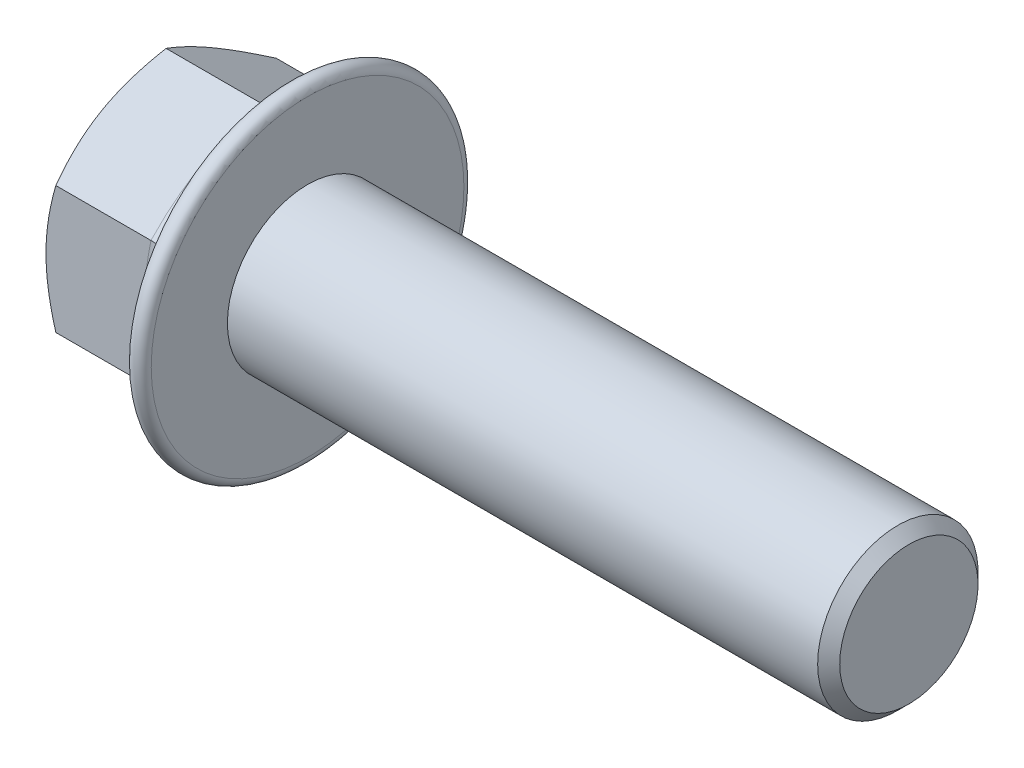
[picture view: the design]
ISO-10303-21;
HEADER;
FILE_DESCRIPTION(('STEP AP214'),'2;1');
FILE_NAME('part.step','',(''),(''),'','','');
FILE_SCHEMA(('AUTOMOTIVE_DESIGN { 1 0 10303 214 1 1 1 1 }'));
ENDSEC;
DATA;
#1=APPLICATION_CONTEXT('core data for automotive mechanical design processes');
#2=APPLICATION_PROTOCOL_DEFINITION('international standard','automotive_design',2000,#1);
#3=PRODUCT_CONTEXT('',#1,'mechanical');
#4=PRODUCT('Part','Part','',(#3));
#5=PRODUCT_RELATED_PRODUCT_CATEGORY('part','',(#4));
#6=PRODUCT_DEFINITION_FORMATION('','',#4);
#7=PRODUCT_DEFINITION_CONTEXT('part definition',#1,'design');
#8=PRODUCT_DEFINITION('design','',#6,#7);
#9=PRODUCT_DEFINITION_SHAPE('','',#8);
#10=(LENGTH_UNIT() NAMED_UNIT(*) SI_UNIT(.MILLI.,.METRE.));
#11=(NAMED_UNIT(*) PLANE_ANGLE_UNIT() SI_UNIT($,.RADIAN.));
#12=(NAMED_UNIT(*) SI_UNIT($,.STERADIAN.) SOLID_ANGLE_UNIT());
#13=UNCERTAINTY_MEASURE_WITH_UNIT(LENGTH_MEASURE(1.E-05),#10,'distance_accuracy_value','');
#14=(GEOMETRIC_REPRESENTATION_CONTEXT(3) GLOBAL_UNCERTAINTY_ASSIGNED_CONTEXT((#13)) GLOBAL_UNIT_ASSIGNED_CONTEXT((#10,
#11,#12)) REPRESENTATION_CONTEXT('',''));
#15=CARTESIAN_POINT('',(0.,0.,0.));
#16=DIRECTION('',(0.,0.,1.));
#17=DIRECTION('',(1.,0.,0.));
#18=AXIS2_PLACEMENT_3D('',#15,#16,#17);
#19=CARTESIAN_POINT('',(15.1,12.7017059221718,0.));
#20=DIRECTION('',(1.,0.,0.));
#21=DIRECTION('',(0.,0.,-1.));
#22=AXIS2_PLACEMENT_3D('',#19,#20,#21);
#23=PLANE('',#22);
#24=CARTESIAN_POINT('',(15.1,0.,0.));
#25=DIRECTION('',(1.,0.,0.));
#26=DIRECTION('',(0.,0.,-1.));
#27=AXIS2_PLACEMENT_3D('',#24,#25,#26);
#28=CIRCLE('',#27,8.);
#29=CARTESIAN_POINT('',(15.1,0.,-8.));
#30=VERTEX_POINT('',#29);
#31=EDGE_CURVE('E510',#30,#30,#28,.F.);
#32=ORIENTED_EDGE('',*,*,#31,.T.);
#33=EDGE_LOOP('',(#32));
#34=FACE_BOUND('',#33,.T.);
#35=CARTESIAN_POINT('',(15.1,0.,0.));
#36=DIRECTION('',(-1.,0.,0.));
#37=DIRECTION('',(0.,0.,1.));
#38=AXIS2_PLACEMENT_3D('',#35,#36,#37);
#39=CIRCLE('',#38,15.6);
#40=CARTESIAN_POINT('',(15.1,0.,15.6));
#41=VERTEX_POINT('',#40);
#42=EDGE_CURVE('E472',#41,#41,#39,.T.);
#43=ORIENTED_EDGE('',*,*,#42,.F.);
#44=EDGE_LOOP('',(#43));
#45=FACE_BOUND('',#44,.T.);
#46=ADVANCED_FACE('F43',(#34,#45),#23,.T.);
#47=CARTESIAN_POINT('',(0.,0.,0.));
#48=DIRECTION('',(-1.,0.,0.));
#49=DIRECTION('',(0.,0.,1.));
#50=AXIS2_PLACEMENT_3D('',#47,#48,#49);
#51=CYLINDRICAL_SURFACE('',#50,8.);
#52=ORIENTED_EDGE('',*,*,#31,.F.);
#53=EDGE_LOOP('',(#52));
#54=FACE_BOUND('',#53,.T.);
#55=CARTESIAN_POINT('',(73.9985,0.,0.));
#56=DIRECTION('',(-1.,0.,0.));
#57=DIRECTION('',(0.,0.,1.));
#58=AXIS2_PLACEMENT_3D('',#55,#56,#57);
#59=CIRCLE('',#58,8.);
#60=CARTESIAN_POINT('',(73.9985,0.,8.));
#61=VERTEX_POINT('',#60);
#62=EDGE_CURVE('E514',#61,#61,#59,.T.);
#63=ORIENTED_EDGE('',*,*,#62,.T.);
#64=EDGE_LOOP('',(#63));
#65=FACE_BOUND('',#64,.T.);
#66=ADVANCED_FACE('F614',(#54,#65),#51,.T.);
#67=CARTESIAN_POINT('',(75.1,0.,0.));
#68=DIRECTION('',(-1.,0.,0.));
#69=DIRECTION('',(0.,0.,1.));
#70=AXIS2_PLACEMENT_3D('',#67,#68,#69);
#71=CONICAL_SURFACE('',#70,6.8985,0.78539816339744);
#72=ORIENTED_EDGE('',*,*,#62,.F.);
#73=EDGE_LOOP('',(#72));
#74=FACE_BOUND('',#73,.T.);
#75=CARTESIAN_POINT('',(75.1,0.,0.));
#76=DIRECTION('',(-1.,0.,0.));
#77=DIRECTION('',(0.,0.,1.));
#78=AXIS2_PLACEMENT_3D('',#75,#76,#77);
#79=CIRCLE('',#78,6.8985);
#80=CARTESIAN_POINT('',(75.1,0.,6.8985));
#81=VERTEX_POINT('',#80);
#82=EDGE_CURVE('E600',#81,#81,#79,.T.);
#83=ORIENTED_EDGE('',*,*,#82,.T.);
#84=EDGE_LOOP('',(#83));
#85=FACE_BOUND('',#84,.T.);
#86=ADVANCED_FACE('F623',(#74,#85),#71,.T.);
#87=CARTESIAN_POINT('',(75.1,0.,0.));
#88=DIRECTION('',(-1.,0.,0.));
#89=DIRECTION('',(0.,0.,1.));
#90=AXIS2_PLACEMENT_3D('',#87,#88,#89);
#91=PLANE('',#90);
#92=ORIENTED_EDGE('',*,*,#82,.F.);
#93=EDGE_LOOP('',(#92));
#94=FACE_BOUND('',#93,.T.);
#95=ADVANCED_FACE('F231',(#94),#91,.F.);
#96=CARTESIAN_POINT('',(13.384322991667,0.,0.));
#97=DIRECTION('',(1.,0.,0.));
#98=DIRECTION('',(0.,0.,-1.));
#99=AXIS2_PLACEMENT_3D('',#96,#97,#98);
#100=CONICAL_SURFACE('',#99,15.9803564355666,1.13446401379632);
#101=CARTESIAN_POINT('',(11.5596455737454,10.6409962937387,-11.));
#102=CARTESIAN_POINT('',(12.9255632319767,10.2375579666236,-11.));
#103=CARTESIAN_POINT('',(13.3722611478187,10.105620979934,-12.345937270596));
#104=CARTESIAN_POINT('',(11.4305304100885,10.2037041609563,-11.));
#105=CARTESIAN_POINT('',(12.7912029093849,9.81274196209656,-11.));
#106=CARTESIAN_POINT('',(13.2431459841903,9.68149724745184,-12.3351734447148));
#107=CARTESIAN_POINT('',(11.3057081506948,9.76509659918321,-11.));
#108=CARTESIAN_POINT('',(12.660771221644,9.3863333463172,-11.));
#109=CARTESIAN_POINT('',(13.1183237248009,9.25708569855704,-12.3242034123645));
#110=CARTESIAN_POINT('',(11.0664512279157,8.88489794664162,-11.));
#111=CARTESIAN_POINT('',(12.4104363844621,8.53196876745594,-11.));
#112=CARTESIAN_POINT('',(12.8790668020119,8.40759481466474,-12.3021680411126));
#113=CARTESIAN_POINT('',(10.9520202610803,8.44330585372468,-11.));
#114=CARTESIAN_POINT('',(12.2904947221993,8.10402124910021,-11.));
#115=CARTESIAN_POINT('',(12.7646358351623,7.98251529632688,-12.2911026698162));
#116=CARTESIAN_POINT('',(10.7349947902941,7.55526586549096,-11.));
#117=CARTESIAN_POINT('',(12.0627180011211,7.24484434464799,-11.));
#118=CARTESIAN_POINT('',(12.5476103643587,7.13014121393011,-12.2691566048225));
#119=CARTESIAN_POINT('',(10.6324510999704,7.10880545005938,-11.));
#120=CARTESIAN_POINT('',(11.9548696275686,6.81356056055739,-11.));
#121=CARTESIAN_POINT('',(12.4450666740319,6.70284474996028,-12.258276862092));
#122=CARTESIAN_POINT('',(10.4419306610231,6.21280862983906,-11.));
#123=CARTESIAN_POINT('',(11.7542777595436,5.9495408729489,-11.));
#124=CARTESIAN_POINT('',(12.2545462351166,5.8479153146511,-12.2372354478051));
#125=CARTESIAN_POINT('',(10.3539525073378,5.76327252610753,-11.));
#126=CARTESIAN_POINT('',(11.6614471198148,5.51668928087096,-11.));
#127=CARTESIAN_POINT('',(12.1665680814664,5.42028237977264,-12.2270737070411));
#128=CARTESIAN_POINT('',(10.1969867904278,4.87337908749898,-11.));
#129=CARTESIAN_POINT('',(11.4956925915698,4.66129336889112,-11.));
#130=CARTESIAN_POINT('',(12.0096023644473,4.57628560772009,-12.2083200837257));
#131=CARTESIAN_POINT('',(10.1275507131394,4.43310153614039,-11.));
#132=CARTESIAN_POINT('',(11.4222119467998,4.23863121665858,-11.));
#133=CARTESIAN_POINT('',(11.9401662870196,4.15992916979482,-12.1996932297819));
#134=CARTESIAN_POINT('',(10.0066902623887,3.55005293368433,-11.));
#135=CARTESIAN_POINT('',(11.2942720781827,3.39227440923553,-11.));
#136=CARTESIAN_POINT('',(11.8193058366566,3.3270376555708,-12.1842941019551));
#137=CARTESIAN_POINT('',(9.95526596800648,3.10728187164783,-11.));
#138=CARTESIAN_POINT('',(11.2397180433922,2.96829897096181,-11.));
#139=CARTESIAN_POINT('',(11.7678815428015,2.91050257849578,-12.1775218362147));
#140=CARTESIAN_POINT('',(9.8722924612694,2.22075700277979,-11.));
#141=CARTESIAN_POINT('',(11.1517130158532,2.12056938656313,-11.));
#142=CARTESIAN_POINT('',(11.6849080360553,2.07816925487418,-12.1664198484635));
#143=CARTESIAN_POINT('',(9.84070353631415,1.77700695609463,-11.));
#144=CARTESIAN_POINT('',(11.1181411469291,1.69645468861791,-11.));
#145=CARTESIAN_POINT('',(11.6533191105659,1.66237120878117,-12.1620852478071));
#146=CARTESIAN_POINT('',(9.79845162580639,0.88850703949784,-11.));
#147=CARTESIAN_POINT('',(11.0732713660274,0.84811919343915,-11.));
#148=CARTESIAN_POINT('',(11.6110671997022,0.830739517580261,-12.1562559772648));
#149=CARTESIAN_POINT('',(9.7877882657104,0.443757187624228,-11.));
#150=CARTESIAN_POINT('',(11.0619277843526,0.423474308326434,-11.));
#151=CARTESIAN_POINT('',(11.6004038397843,0.414905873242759,-12.1547612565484));
#152=CARTESIAN_POINT('',(9.78782004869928,-0.446623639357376,-11.));
#153=CARTESIAN_POINT('',(11.0619615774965,-0.426210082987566,-11.));
#154=CARTESIAN_POINT('',(11.6004356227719,-0.417585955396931,-12.1547657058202));
#155=CARTESIAN_POINT('',(9.79855757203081,-0.892254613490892,-11.));
#156=CARTESIAN_POINT('',(11.0733840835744,-0.851697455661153,-11.));
#157=CARTESIAN_POINT('',(11.6111731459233,-0.834244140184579,-12.1562708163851));
#158=CARTESIAN_POINT('',(9.84103825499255,-1.7825096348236,-11.));
#159=CARTESIAN_POINT('',(11.118496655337,-1.70171175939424,-11.));
#160=CARTESIAN_POINT('',(11.6536538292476,-1.6675247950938,-12.1621312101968));
#161=CARTESIAN_POINT('',(9.87278180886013,-2.22713366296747,-11.));
#162=CARTESIAN_POINT('',(11.1522328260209,-2.12666516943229,-11.));
#163=CARTESIAN_POINT('',(11.6853973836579,-2.0841472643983,-12.1664865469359));
#164=CARTESIAN_POINT('',(9.95613528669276,-3.115400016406,-11.));
#165=CARTESIAN_POINT('',(11.2406400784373,-2.97606905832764,-11.));
#166=CARTESIAN_POINT('',(11.7687508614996,-2.91813348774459,-12.1776369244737));
#167=CARTESIAN_POINT('',(10.0077852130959,-3.55903854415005,-11.));
#168=CARTESIAN_POINT('',(11.2954329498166,-3.40088181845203,-11.));
#169=CARTESIAN_POINT('',(11.820400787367,-3.33549703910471,-12.1844368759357));
#170=CARTESIAN_POINT('',(10.129154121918,-4.44380840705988,-11.));
#171=CARTESIAN_POINT('',(11.4239089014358,-4.24890494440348,-11.));
#172=CARTESIAN_POINT('',(11.941769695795,-4.17004410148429,-12.1998942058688));
#173=CARTESIAN_POINT('',(10.1988730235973,-4.88493975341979,-11.));
#174=CARTESIAN_POINT('',(11.4976874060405,-4.67239710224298,-11.));
#175=CARTESIAN_POINT('',(12.0114885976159,-4.58722761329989,-12.2085515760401));
#176=CARTESIAN_POINT('',(10.3564610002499,-5.77657736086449,-11.));
#177=CARTESIAN_POINT('',(11.6640948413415,-5.52949439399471,-11.));
#178=CARTESIAN_POINT('',(12.1690765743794,-5.43292471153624,-12.2273669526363));
#179=CARTESIAN_POINT('',(10.444780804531,-6.22700328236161,-11.));
#180=CARTESIAN_POINT('',(11.7572832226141,-5.96321710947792,-11.));
#181=CARTESIAN_POINT('',(12.2573963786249,-5.86143082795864,-12.237559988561));
#182=CARTESIAN_POINT('',(10.6360189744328,-7.1247669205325,-11.));
#183=CARTESIAN_POINT('',(11.9586238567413,-6.82897274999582,-11.));
#184=CARTESIAN_POINT('',(12.4486345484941,-6.71810419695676,-12.2586607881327));
#185=CARTESIAN_POINT('',(10.7389387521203,-7.5721043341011,-11.));
#186=CARTESIAN_POINT('',(12.0668635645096,-7.26112112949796,-11.));
#187=CARTESIAN_POINT('',(12.5515543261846,-7.14627141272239,-12.2695686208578));
#188=CARTESIAN_POINT('',(10.9567359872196,-8.46187507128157,-11.));
#189=CARTESIAN_POINT('',(12.2954406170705,-8.12201010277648,-11.));
#190=CARTESIAN_POINT('',(12.7693515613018,-8.00037188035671,-12.2915659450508));
#191=CARTESIAN_POINT('',(11.0715622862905,-8.904321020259,-11.));
#192=CARTESIAN_POINT('',(12.4157910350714,-8.55080460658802,-11.));
#193=CARTESIAN_POINT('',(12.8841778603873,-8.42630705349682,-12.3026544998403));
#194=CARTESIAN_POINT('',(11.3116248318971,-9.78621842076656,-11.));
#195=CARTESIAN_POINT('',(12.6669566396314,-9.40685918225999,-11.));
#196=CARTESIAN_POINT('',(13.1242404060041,-9.27750557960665,-12.3247314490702));
#197=CARTESIAN_POINT('',(11.4368573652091,-10.225670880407,-11.));
#198=CARTESIAN_POINT('',(12.7978102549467,-9.83411006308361,-11.));
#199=CARTESIAN_POINT('',(13.2494729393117,-9.70276911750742,-12.3357198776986));
#200=CARTESIAN_POINT('',(11.5663866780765,-10.6638049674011,-11.));
#201=CARTESIAN_POINT('',(12.9325938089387,-10.2597638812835,-11.));
#202=CARTESIAN_POINT('',(13.3790022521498,-10.1277433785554,-12.346499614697));
#203=(BOUNDED_SURFACE() B_SPLINE_SURFACE(3,2,((#101,#102,#103),(#104,#105,#106),(#107,#108,
#109),(#110,#111,#112),(#113,#114,#115),(#116,#117,#118),(#119,#120,#121),(#122,#123,#124),
(#125,#126,#127),(#128,#129,#130),(#131,#132,#133),(#134,#135,#136),(#137,#138,#139),(#140,#141,
#142),(#143,#144,#145),(#146,#147,#148),(#149,#150,#151),(#152,#153,#154),(#155,#156,#157),
(#158,#159,#160),(#161,#162,#163),(#164,#165,#166),(#167,#168,#169),(#170,#171,#172),(#173,#174,
#175),(#176,#177,#178),(#179,#180,#181),(#182,#183,#184),(#185,#186,#187),(#188,#189,#190),
(#191,#192,#193),(#194,#195,#196),(#197,#198,#199),(#200,#201,#202)),.UNSPECIFIED.,.F.,.F.,
.F.) B_SPLINE_SURFACE_WITH_KNOTS((4,2,2,2,2,2,2,2,2,2,2,2,2,2,2,2,4),(3,3),(0.,1.36791223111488,
2.73630918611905,4.11035517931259,5.48426854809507,6.82109549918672,8.15792831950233,
9.49207604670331,10.8261998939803,12.1629683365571,13.4997618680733,14.8392558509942,
16.1787438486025,17.5554729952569,18.932335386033,20.3035094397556,21.6741963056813),(0.,1.),
.UNSPECIFIED.) GEOMETRIC_REPRESENTATION_ITEM() RATIONAL_B_SPLINE_SURFACE(((1.,0.814564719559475,
1.),(1.,0.816216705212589,1.),(1.,0.817894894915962,1.),(1.,0.82125557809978,1.),(1.,
0.822938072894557,1.),(1.,0.826264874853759,1.),(1.,0.827908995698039,1.),(1.,0.831079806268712,
1.),(1.,0.832606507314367,1.),(1.,0.835417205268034,1.),(1.,0.836706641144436,1.),(1.,
0.839004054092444,1.),(1.,0.840012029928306,1.),(1.,0.841662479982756,1.),(1.,0.842305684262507,
1.),(1.,0.84317032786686,1.),(1.,0.843391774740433,1.),(1.,0.843391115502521,1.),(1.,
0.843168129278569,1.),(1.,0.842298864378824,1.),(1.,0.841652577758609,1.),(1.,0.839994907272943,
1.),(1.,0.838982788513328,1.),(1.,0.836676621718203,1.),(1.,0.835382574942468,1.),(1.,
0.83256248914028,1.),(1.,0.831031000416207,1.),(1.,0.827851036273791,1.),(1.,0.826202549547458,
1.),(1.,0.82286770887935,1.),(1.,0.821181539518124,1.),(1.,0.817814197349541,1.),(1.,
0.816133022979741,1.),(1.,0.814478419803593,1.))) REPRESENTATION_ITEM('') SURFACE());
#204=CARTESIAN_POINT('',(13.3790022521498,-10.1277433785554,-12.346499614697));
#205=CARTESIAN_POINT('',(13.2494729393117,-9.70276911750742,-12.3357198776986));
#206=CARTESIAN_POINT('',(13.1242404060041,-9.27750557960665,-12.3247314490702));
#207=CARTESIAN_POINT('',(12.8841778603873,-8.42630705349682,-12.3026544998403));
#208=CARTESIAN_POINT('',(12.7693515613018,-8.00037188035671,-12.2915659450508));
#209=CARTESIAN_POINT('',(12.5515543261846,-7.14627141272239,-12.2695686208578));
#210=CARTESIAN_POINT('',(12.4486345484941,-6.71810419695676,-12.2586607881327));
#211=CARTESIAN_POINT('',(12.2573963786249,-5.86143082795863,-12.237559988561));
#212=CARTESIAN_POINT('',(12.1690765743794,-5.43292471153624,-12.2273669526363));
#213=CARTESIAN_POINT('',(12.0114885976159,-4.58722761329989,-12.2085515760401));
#214=CARTESIAN_POINT('',(11.941769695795,-4.17004410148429,-12.1998942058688));
#215=CARTESIAN_POINT('',(11.820400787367,-3.33549703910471,-12.1844368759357));
#216=CARTESIAN_POINT('',(11.7687508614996,-2.91813348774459,-12.1776369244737));
#217=CARTESIAN_POINT('',(11.6853973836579,-2.0841472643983,-12.1664865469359));
#218=CARTESIAN_POINT('',(11.6536538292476,-1.6675247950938,-12.1621312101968));
#219=CARTESIAN_POINT('',(11.6111731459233,-0.834244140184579,-12.1562708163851));
#220=CARTESIAN_POINT('',(11.6004356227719,-0.417585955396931,-12.1547657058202));
#221=CARTESIAN_POINT('',(11.6004038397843,0.414905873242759,-12.1547612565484));
#222=CARTESIAN_POINT('',(11.6110671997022,0.830739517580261,-12.1562559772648));
#223=CARTESIAN_POINT('',(11.6533191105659,1.66237120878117,-12.1620852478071));
#224=CARTESIAN_POINT('',(11.6849080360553,2.07816925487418,-12.1664198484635));
#225=CARTESIAN_POINT('',(11.7678815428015,2.91050257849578,-12.1775218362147));
#226=CARTESIAN_POINT('',(11.8193058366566,3.3270376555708,-12.1842941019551));
#227=CARTESIAN_POINT('',(11.9401662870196,4.15992916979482,-12.1996932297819));
#228=CARTESIAN_POINT('',(12.0096023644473,4.57628560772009,-12.2083200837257));
#229=CARTESIAN_POINT('',(12.1665680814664,5.42028237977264,-12.2270737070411));
#230=CARTESIAN_POINT('',(12.2545462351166,5.8479153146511,-12.2372354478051));
#231=CARTESIAN_POINT('',(12.4450666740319,6.70284474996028,-12.258276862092));
#232=CARTESIAN_POINT('',(12.5476103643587,7.13014121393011,-12.2691566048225));
#233=CARTESIAN_POINT('',(12.7646358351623,7.98251529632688,-12.2911026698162));
#234=CARTESIAN_POINT('',(12.8790668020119,8.40759481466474,-12.3021680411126));
#235=CARTESIAN_POINT('',(13.1183237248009,9.25708569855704,-12.3242034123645));
#236=CARTESIAN_POINT('',(13.2431459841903,9.68149724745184,-12.3351734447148));
#237=CARTESIAN_POINT('',(13.3722611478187,10.105620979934,-12.345937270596));
#238=B_SPLINE_CURVE_WITH_KNOTS('',3,(#204,#205,#206,#207,#208,#209,#210,#211,#212,#213,#214,
#215,#216,#217,#218,#219,#220,#221,#222,#223,#224,#225,#226,#227,#228,#229,#230,#231,#232,#233,
#234,#235,#236,#237),.UNSPECIFIED.,.F.,.F.,(4,2,2,2,2,2,2,2,2,2,2,2,2,2,2,2,4),(0.,
1.37068686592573,2.7418609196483,4.11872331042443,5.49545245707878,6.83494045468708,
8.17443443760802,9.51122796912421,10.847996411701,12.182120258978,13.516267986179,
14.8531008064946,16.1899277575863,17.5638411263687,18.9378871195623,20.3062840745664,
21.6741963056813),.UNSPECIFIED.);
#239=CARTESIAN_POINT('',(12.5382142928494,-7.08293523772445,-12.2680036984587));
#240=VERTEX_POINT('',#239);
#241=CARTESIAN_POINT('',(12.5382142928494,7.08293523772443,-12.2680036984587));
#242=VERTEX_POINT('',#241);
#243=EDGE_CURVE('E559',#240,#242,#238,.T.);
#244=ORIENTED_EDGE('',*,*,#243,.T.);
#245=CARTESIAN_POINT('',(11.5735039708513,14.8702068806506,3.75595383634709));
#246=CARTESIAN_POINT('',(12.9400163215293,14.6678691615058,3.40549462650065));
#247=CARTESIAN_POINT('',(13.3861195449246,15.7684313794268,2.61753972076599));
#248=CARTESIAN_POINT('',(11.443142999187,14.6500285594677,3.3745937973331));
#249=CARTESIAN_POINT('',(12.8043767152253,14.4539536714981,3.0349821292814));
#250=CARTESIAN_POINT('',(13.2557585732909,15.5454701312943,2.25301763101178));
#251=CARTESIAN_POINT('',(11.3171084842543,14.4291853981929,2.99208222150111));
#252=CARTESIAN_POINT('',(12.6726913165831,14.2392320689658,2.66307340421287));
#253=CARTESIAN_POINT('',(13.1297240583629,15.3221782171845,1.88834853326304));
#254=CARTESIAN_POINT('',(11.0755263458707,13.9859880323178,2.22444186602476));
#255=CARTESIAN_POINT('',(12.4199461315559,13.809004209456,1.91789689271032));
#256=CARTESIAN_POINT('',(12.8881419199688,14.8751633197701,1.1584734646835));
#257=CARTESIAN_POINT('',(10.9599825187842,13.7636333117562,1.83931219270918));
#258=CARTESIAN_POINT('',(12.2988476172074,13.5935029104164,1.5446376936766));
#259=CARTESIAN_POINT('',(12.7725980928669,14.651440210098,0.793267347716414));
#260=CARTESIAN_POINT('',(10.7408534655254,13.3164534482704,1.0647739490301));
#261=CARTESIAN_POINT('',(12.0688786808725,13.1608272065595,0.795221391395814));
#262=CARTESIAN_POINT('',(12.5534690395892,14.2030151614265,0.0608038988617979));
#263=CARTESIAN_POINT('',(10.6373204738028,13.091621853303,0.675354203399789));
#264=CARTESIAN_POINT('',(11.9599954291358,12.9436256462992,0.419017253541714));
#265=CARTESIAN_POINT('',(12.4499360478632,13.9783130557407,-0.306455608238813));
#266=CARTESIAN_POINT('',(10.445003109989,12.6403980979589,-0.106188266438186));
#267=CARTESIAN_POINT('',(11.7575202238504,12.5084855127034,-0.334667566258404));
#268=CARTESIAN_POINT('',(12.2576186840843,13.5293618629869,-1.04163160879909));
#269=CARTESIAN_POINT('',(10.3562172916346,12.4140060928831,-0.498310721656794));
#270=CARTESIAN_POINT('',(11.6638394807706,12.2904884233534,-0.712249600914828));
#271=CARTESIAN_POINT('',(12.1688328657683,13.3051127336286,-1.40954803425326));
#272=CARTESIAN_POINT('',(10.1979057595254,11.9658880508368,-1.27447393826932));
#273=CARTESIAN_POINT('',(11.4966667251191,11.8597328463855,-1.45834014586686));
#274=CARTESIAN_POINT('',(12.01052133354,12.8637174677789,-2.13625642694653));
#275=CARTESIAN_POINT('',(10.1279213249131,11.7442028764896,-1.65844392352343));
#276=CARTESIAN_POINT('',(11.4226055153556,11.6469146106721,-1.82695214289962));
#277=CARTESIAN_POINT('',(11.9405368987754,12.6465442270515,-2.49502397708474));
#278=CARTESIAN_POINT('',(10.0062196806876,11.299568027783,-2.42857407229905));
#279=CARTESIAN_POINT('',(11.2937751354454,11.2207552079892,-2.56508188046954));
#280=CARTESIAN_POINT('',(11.8188352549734,12.2137361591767,-3.21365649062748));
#281=CARTESIAN_POINT('',(9.95450254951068,11.0766183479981,-2.81473424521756));
#282=CARTESIAN_POINT('',(11.2389091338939,11.0072706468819,-2.93484798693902));
#283=CARTESIAN_POINT('',(11.7671181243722,11.9981013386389,-3.57352145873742));
#284=CARTESIAN_POINT('',(9.87123699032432,10.6302279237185,-3.58790514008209));
#285=CARTESIAN_POINT('',(11.1505933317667,10.580420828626,-3.67417355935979));
#286=CARTESIAN_POINT('',(11.6838525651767,11.5693586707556,-4.29383691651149));
#287=CARTESIAN_POINT('',(9.83964756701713,10.4067891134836,-3.97491251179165));
#288=CARTESIAN_POINT('',(11.1170198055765,10.3668711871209,-4.04405238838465));
#289=CARTESIAN_POINT('',(11.652263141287,11.3562465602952,-4.65428470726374));
#290=CARTESIAN_POINT('',(9.79770239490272,9.95941155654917,-4.7497931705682));
#291=CARTESIAN_POINT('',(11.0724752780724,9.93972359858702,-4.78389371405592));
#292=CARTESIAN_POINT('',(11.6103179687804,10.9325028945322,-5.37665300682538));
#293=CARTESIAN_POINT('',(9.78734623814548,9.73547281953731,-5.13766644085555));
#294=CARTESIAN_POINT('',(11.0614582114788,9.72590877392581,-5.15423185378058));
#295=CARTESIAN_POINT('',(11.5999618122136,10.7218712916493,-5.73857348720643));
#296=CARTESIAN_POINT('',(9.78829157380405,9.28836706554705,-5.91207632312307));
#297=CARTESIAN_POINT('',(11.0624625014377,9.29923871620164,-5.89324607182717));
#298=CARTESIAN_POINT('',(11.6009071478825,10.3039484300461,-6.46270063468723));
#299=CARTESIAN_POINT('',(9.79951969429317,9.06520000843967,-6.29861300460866));
#300=CARTESIAN_POINT('',(11.0744068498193,9.08615659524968,-6.26231513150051));
#301=CARTESIAN_POINT('',(11.6121352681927,10.0966482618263,-6.82490216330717));
#302=CARTESIAN_POINT('',(9.84302911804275,8.61938207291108,-7.07079231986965));
#303=CARTESIAN_POINT('',(11.1206109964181,8.66047991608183,-6.99960876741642));
#304=CARTESIAN_POINT('',(11.6556446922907,9.68453662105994,-7.55069929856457));
#305=CARTESIAN_POINT('',(9.87531080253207,8.39673120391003,-7.45643493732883));
#306=CARTESIAN_POINT('',(11.1549180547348,8.44767160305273,-7.36820357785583));
#307=CARTESIAN_POINT('',(11.6879263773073,9.47972519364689,-7.91429493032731));
#308=CARTESIAN_POINT('',(9.9597678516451,7.95192777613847,-8.22685707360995));
#309=CARTESIAN_POINT('',(11.2444921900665,8.02230824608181,-8.10495452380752));
#310=CARTESIAN_POINT('',(11.77238342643,9.07183688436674,-8.64335174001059));
#311=CARTESIAN_POINT('',(10.0119836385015,7.72977715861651,-8.6116332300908));
#312=CARTESIAN_POINT('',(11.2998824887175,7.80957215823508,-8.47342423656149));
#313=CARTESIAN_POINT('',(11.8245992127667,8.86876438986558,-9.00881520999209));
#314=CARTESIAN_POINT('',(10.1344910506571,7.2867398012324,-9.37899644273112));
#315=CARTESIAN_POINT('',(11.4295559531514,7.38490597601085,-9.20896764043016));
#316=CARTESIAN_POINT('',(11.9471066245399,8.46431058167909,-9.74050757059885));
#317=CARTESIAN_POINT('',(10.2047826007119,7.06585305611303,-9.76158350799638));
#318=CARTESIAN_POINT('',(11.50393517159,7.17283548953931,-9.57628449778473));
#319=CARTESIAN_POINT('',(12.017398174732,8.26292926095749,-10.1067364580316));
#320=CARTESIAN_POINT('',(10.3635332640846,6.61936549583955,-10.5349226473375));
#321=CARTESIAN_POINT('',(11.6715578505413,6.74360744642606,-10.3197292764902));
#322=CARTESIAN_POINT('',(12.1761488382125,7.8557607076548,-10.8498066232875));
#323=CARTESIAN_POINT('',(10.4524447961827,6.39380523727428,-10.9256044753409));
#324=CARTESIAN_POINT('',(11.765362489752,6.52639230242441,-10.6959569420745));
#325=CARTESIAN_POINT('',(12.2650603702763,7.65000743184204,-11.2266587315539));
#326=CARTESIAN_POINT('',(10.6448520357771,5.94423447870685,-11.704283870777));
#327=CARTESIAN_POINT('',(11.967916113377,6.09280880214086,-11.4469455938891));
#328=CARTESIAN_POINT('',(12.457467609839,7.23927992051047,-11.9804166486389));
#329=CARTESIAN_POINT('',(10.7483491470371,5.72022413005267,-12.0922811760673));
#330=CARTESIAN_POINT('',(12.0767524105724,5.87638362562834,-11.8218049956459));
#331=CARTESIAN_POINT('',(12.5609647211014,7.03430576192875,-12.3573224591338));
#332=CARTESIAN_POINT('',(10.9672745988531,5.27466865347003,-12.864005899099));
#333=CARTESIAN_POINT('',(12.3064912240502,5.44524755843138,-12.5685545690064));
#334=CARTESIAN_POINT('',(12.7798901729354,6.62563283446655,-13.1092636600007));
#335=CARTESIAN_POINT('',(11.0826513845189,5.0531171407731,-13.2477443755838));
#336=CARTESIAN_POINT('',(12.4274060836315,5.23051050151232,-12.9404900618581));
#337=CARTESIAN_POINT('',(12.8952669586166,6.42193231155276,-13.4843002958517));
#338=CARTESIAN_POINT('',(11.3237929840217,4.61151258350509,-14.0126259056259));
#339=CARTESIAN_POINT('',(12.6796748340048,4.80180341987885,-13.6830325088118));
#340=CARTESIAN_POINT('',(13.1364085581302,6.01477379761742,-14.2337340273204));
#341=CARTESIAN_POINT('',(11.4495541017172,4.39145903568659,-14.3937698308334));
#342=CARTESIAN_POINT('',(12.8110666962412,4.587838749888,-14.0536301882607));
#343=CARTESIAN_POINT('',(13.2621696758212,5.81131574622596,-14.6081313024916));
#344=CARTESIAN_POINT('',(11.5796005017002,4.17206449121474,-14.773772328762));
#345=CARTESIAN_POINT('',(12.9463739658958,4.37467306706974,-14.422843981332));
#346=CARTESIAN_POINT('',(13.3922160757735,5.60781914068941,-14.982170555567));
#347=(BOUNDED_SURFACE() B_SPLINE_SURFACE(3,2,((#245,#246,#247),(#248,#249,#250),(#251,#252,
#253),(#254,#255,#256),(#257,#258,#259),(#260,#261,#262),(#263,#264,#265),(#266,#267,#268),
(#269,#270,#271),(#272,#273,#274),(#275,#276,#277),(#278,#279,#280),(#281,#282,#283),(#284,#285,
#286),(#287,#288,#289),(#290,#291,#292),(#293,#294,#295),(#296,#297,#298),(#299,#300,#301),
(#302,#303,#304),(#305,#306,#307),(#308,#309,#310),(#311,#312,#313),(#314,#315,#316),(#317,#318,
#319),(#320,#321,#322),(#323,#324,#325),(#326,#327,#328),(#329,#330,#331),(#332,#333,#334),
(#335,#336,#337),(#338,#339,#340),(#341,#342,#343),(#344,#345,#346)),.UNSPECIFIED.,.F.,.F.,
.F.) B_SPLINE_SURFACE_WITH_KNOTS((4,2,2,2,2,2,2,2,2,2,2,2,2,2,2,2,4),(3,3),(0.,1.37778937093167,
2.75607536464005,4.1401469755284,5.52408276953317,6.87032435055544,8.21657171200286,
9.56006825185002,10.9035389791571,12.2424508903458,13.5813870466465,14.9230528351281,
16.2647130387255,17.6438299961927,19.0230797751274,20.3965778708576,21.7695891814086),(0.,1.),
.UNSPECIFIED.) GEOMETRIC_REPRESENTATION_ITEM() RATIONAL_B_SPLINE_SURFACE(((1.,0.814387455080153,
1.),(1.,0.81604981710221,1.),(1.,0.817739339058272,1.),(1.,0.821124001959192,1.),(1.,
0.8228191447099,1.),(1.,0.826172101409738,1.),(1.,0.827829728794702,1.),(1.,0.831026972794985,
1.),(1.,0.832566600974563,1.),(1.,0.835400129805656,1.),(1.,0.836699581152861,1.),(1.,
0.839013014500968,1.),(1.,0.840026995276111,1.),(1.,0.841683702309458,1.),(1.,0.842327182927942,
1.),(1.,0.843185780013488,1.),(1.,0.843400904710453,1.),(1.,0.843381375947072,1.),(1.,
0.843148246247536,1.),(1.,0.842258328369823,1.),(1.,0.841601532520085,1.),(1.,0.839923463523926,
1.),(1.,0.838901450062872,1.),(1.,0.836576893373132,1.),(1.,0.835274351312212,1.),(1.,
0.832438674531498,1.),(1.,0.830900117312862,1.),(1.,0.827707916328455,1.),(1.,0.826054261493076,
1.),(1.,0.822710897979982,1.),(1.,0.821021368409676,1.),(1.,0.817648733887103,1.),(1.,
0.815965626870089,1.),(1.,0.81430965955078,1.))) REPRESENTATION_ITEM('') SURFACE());
#348=CARTESIAN_POINT('',(13.3922160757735,5.60781914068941,-14.982170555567));
#349=CARTESIAN_POINT('',(13.2621696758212,5.81131574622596,-14.6081313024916));
#350=CARTESIAN_POINT('',(13.1364085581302,6.01477379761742,-14.2337340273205));
#351=CARTESIAN_POINT('',(12.8952669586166,6.42193231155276,-13.4843002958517));
#352=CARTESIAN_POINT('',(12.7798901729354,6.62563283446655,-13.1092636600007));
#353=CARTESIAN_POINT('',(12.5609647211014,7.03430576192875,-12.3573224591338));
#354=CARTESIAN_POINT('',(12.457467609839,7.23927992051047,-11.9804166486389));
#355=CARTESIAN_POINT('',(12.2650603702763,7.65000743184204,-11.2266587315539));
#356=CARTESIAN_POINT('',(12.1761488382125,7.8557607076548,-10.8498066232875));
#357=CARTESIAN_POINT('',(12.0173981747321,8.26292926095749,-10.1067364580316));
#358=CARTESIAN_POINT('',(11.9471066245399,8.46431058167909,-9.74050757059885));
#359=CARTESIAN_POINT('',(11.8245992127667,8.86876438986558,-9.00881520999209));
#360=CARTESIAN_POINT('',(11.77238342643,9.07183688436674,-8.64335174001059));
#361=CARTESIAN_POINT('',(11.6879263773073,9.47972519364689,-7.91429493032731));
#362=CARTESIAN_POINT('',(11.6556446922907,9.68453662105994,-7.55069929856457));
#363=CARTESIAN_POINT('',(11.6121352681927,10.0966482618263,-6.82490216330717));
#364=CARTESIAN_POINT('',(11.6009071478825,10.3039484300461,-6.46270063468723));
#365=CARTESIAN_POINT('',(11.5999618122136,10.7218712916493,-5.73857348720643));
#366=CARTESIAN_POINT('',(11.6103179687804,10.9325028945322,-5.37665300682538));
#367=CARTESIAN_POINT('',(11.652263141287,11.3562465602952,-4.65428470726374));
#368=CARTESIAN_POINT('',(11.6838525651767,11.5693586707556,-4.29383691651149));
#369=CARTESIAN_POINT('',(11.7671181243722,11.9981013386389,-3.57352145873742));
#370=CARTESIAN_POINT('',(11.8188352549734,12.2137361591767,-3.21365649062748));
#371=CARTESIAN_POINT('',(11.9405368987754,12.6465442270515,-2.49502397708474));
#372=CARTESIAN_POINT('',(12.01052133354,12.8637174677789,-2.13625642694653));
#373=CARTESIAN_POINT('',(12.1688328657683,13.3051127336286,-1.40954803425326));
#374=CARTESIAN_POINT('',(12.2576186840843,13.5293618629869,-1.04163160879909));
#375=CARTESIAN_POINT('',(12.4499360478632,13.9783130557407,-0.306455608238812));
#376=CARTESIAN_POINT('',(12.5534690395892,14.2030151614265,0.0608038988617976));
#377=CARTESIAN_POINT('',(12.7725980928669,14.651440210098,0.793267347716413));
#378=CARTESIAN_POINT('',(12.8881419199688,14.8751633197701,1.1584734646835));
#379=CARTESIAN_POINT('',(13.1297240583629,15.3221782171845,1.88834853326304));
#380=CARTESIAN_POINT('',(13.2557585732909,15.5454701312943,2.25301763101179));
#381=CARTESIAN_POINT('',(13.3861195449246,15.7684313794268,2.61753972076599));
#382=B_SPLINE_CURVE_WITH_KNOTS('',3,(#348,#349,#350,#351,#352,#353,#354,#355,#356,#357,#358,
#359,#360,#361,#362,#363,#364,#365,#366,#367,#368,#369,#370,#371,#372,#373,#374,#375,#376,#377,
#378,#379,#380,#381),.UNSPECIFIED.,.F.,.F.,(4,2,2,2,2,2,2,2,2,2,2,2,2,2,2,2,4),(0.,
1.373011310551,2.74650940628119,4.12575918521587,5.50487614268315,6.84653634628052,
8.18820213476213,9.52713829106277,10.8660502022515,12.2095209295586,13.5530174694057,
14.8992648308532,16.2455064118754,17.6294422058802,19.0135138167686,20.3917998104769,
21.7695891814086),.UNSPECIFIED.);
#383=CARTESIAN_POINT('',(12.5382142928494,14.1658704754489,0.));
#384=VERTEX_POINT('',#383);
#385=EDGE_CURVE('E564',#242,#384,#382,.T.);
#386=ORIENTED_EDGE('',*,*,#385,.T.);
#387=CARTESIAN_POINT('',(11.5735039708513,4.18235200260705,14.7559538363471));
#388=CARTESIAN_POINT('',(12.9400163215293,4.38468972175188,14.4054946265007));
#389=CARTESIAN_POINT('',(13.3861195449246,5.61735979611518,14.9646320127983));
#390=CARTESIAN_POINT('',(11.443142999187,4.40253032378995,14.3745937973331));
#391=CARTESIAN_POINT('',(12.8043767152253,4.59860521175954,14.0349821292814));
#392=CARTESIAN_POINT('',(13.2557585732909,5.82156456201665,14.5892808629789));
#393=CARTESIAN_POINT('',(11.3171084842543,4.62337348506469,13.9920822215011));
#394=CARTESIAN_POINT('',(12.672691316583,4.81332681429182,13.6630734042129));
#395=CARTESIAN_POINT('',(13.1297240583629,6.02573130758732,14.2135698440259));
#396=CARTESIAN_POINT('',(11.0755263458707,5.06657085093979,13.2244418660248));
#397=CARTESIAN_POINT('',(12.4199461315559,5.24355467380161,12.9178968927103));
#398=CARTESIAN_POINT('',(12.8881419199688,6.43431420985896,13.4615060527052));
#399=CARTESIAN_POINT('',(10.9599825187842,5.28892557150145,12.8393121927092));
#400=CARTESIAN_POINT('',(12.2988476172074,5.45905597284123,12.5446376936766));
#401=CARTESIAN_POINT('',(12.7725980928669,6.63873042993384,13.0851530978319));
#402=CARTESIAN_POINT('',(10.7408534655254,5.73610543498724,12.0647739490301));
#403=CARTESIAN_POINT('',(12.0688786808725,5.89173167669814,11.7952213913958));
#404=CARTESIAN_POINT('',(12.5534690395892,7.04884985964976,12.3305738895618));
#405=CARTESIAN_POINT('',(10.6373204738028,5.96093702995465,11.6753542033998));
#406=CARTESIAN_POINT('',(11.9599954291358,6.10893323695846,11.4190172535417));
#407=CARTESIAN_POINT('',(12.4499360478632,7.25455486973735,11.9523464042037));
#408=CARTESIAN_POINT('',(10.445003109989,6.41216078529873,10.8938117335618));
#409=CARTESIAN_POINT('',(11.7575202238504,6.54407337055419,10.6653324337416));
#410=CARTESIAN_POINT('',(12.2576186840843,7.66676036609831,11.1959552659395));
#411=CARTESIAN_POINT('',(10.3562172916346,6.63855279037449,10.5016892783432));
#412=CARTESIAN_POINT('',(11.6638394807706,6.76207045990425,10.2877503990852));
#413=CARTESIAN_POINT('',(12.1688328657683,7.87326077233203,10.8177916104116));
#414=CARTESIAN_POINT('',(10.1979057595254,7.08667083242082,9.72552606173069));
#415=CARTESIAN_POINT('',(11.4966667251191,7.19282603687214,9.54165985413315));
#416=CARTESIAN_POINT('',(12.01052133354,8.2819110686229,10.0721779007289));
#417=CARTESIAN_POINT('',(10.1279213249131,7.30835600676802,9.34155607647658));
#418=CARTESIAN_POINT('',(11.4226055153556,7.40564427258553,9.17304785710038));
#419=CARTESIAN_POINT('',(11.9405368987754,8.48402626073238,9.70471658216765));
#420=CARTESIAN_POINT('',(10.0062196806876,7.75299085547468,8.57142592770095));
#421=CARTESIAN_POINT('',(11.2937751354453,7.83180367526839,8.43491811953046));
#422=CARTESIAN_POINT('',(11.8188352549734,8.88997623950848,8.97057754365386));
#423=CARTESIAN_POINT('',(9.95450254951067,7.97594053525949,8.18526575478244));
#424=CARTESIAN_POINT('',(11.2389091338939,8.04528823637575,8.06515201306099));
#425=CARTESIAN_POINT('',(11.7671181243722,9.09381103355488,8.60389982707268));
#426=CARTESIAN_POINT('',(9.87123699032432,8.42233095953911,7.41209485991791));
#427=CARTESIAN_POINT('',(11.1505933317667,8.47213805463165,7.32582644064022));
#428=CARTESIAN_POINT('',(11.6838525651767,9.50325118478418,7.87244005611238));
#429=CARTESIAN_POINT('',(9.83964756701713,8.645769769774,7.02508748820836));
#430=CARTESIAN_POINT('',(11.1170198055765,8.6856876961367,6.95594761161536));
#431=CARTESIAN_POINT('',(11.652263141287,9.70885207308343,7.50765565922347));
#432=CARTESIAN_POINT('',(9.79770239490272,9.09314732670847,6.2502068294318));
#433=CARTESIAN_POINT('',(11.0724752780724,9.11283528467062,6.21610628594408));
#434=CARTESIAN_POINT('',(11.6103179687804,10.1225695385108,6.77949873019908));
#435=CARTESIAN_POINT('',(9.78734623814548,9.31708606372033,5.86233355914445));
#436=CARTESIAN_POINT('',(11.0614582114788,9.32665010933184,5.84576814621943));
#437=CARTESIAN_POINT('',(11.5999618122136,10.3306860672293,6.41612617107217));
#438=CARTESIAN_POINT('',(9.78829157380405,9.76419181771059,5.08792367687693));
#439=CARTESIAN_POINT('',(11.0624625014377,9.753320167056,5.10675392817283));
#440=CARTESIAN_POINT('',(11.6009071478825,10.748837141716,5.69213078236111));
#441=CARTESIAN_POINT('',(9.79951969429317,9.98735887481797,4.70138699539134));
#442=CARTESIAN_POINT('',(11.0744068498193,9.96640228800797,4.73768486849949));
#443=CARTESIAN_POINT('',(11.6121352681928,10.9588627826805,5.33150280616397));
#444=CARTESIAN_POINT('',(9.84302911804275,10.4331768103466,3.92920768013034));
#445=CARTESIAN_POINT('',(11.120610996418,10.3920789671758,4.00039123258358));
#446=CARTESIAN_POINT('',(11.6556446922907,11.3813657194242,4.61170508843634));
#447=CARTESIAN_POINT('',(9.87531080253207,10.6558276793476,3.54356506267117));
#448=CARTESIAN_POINT('',(11.1549180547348,10.6048872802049,3.63179642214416));
#449=CARTESIAN_POINT('',(11.6879263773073,11.5938430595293,4.25253537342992));
#450=CARTESIAN_POINT('',(9.95976785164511,11.1006311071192,2.77314292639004));
#451=CARTESIAN_POINT('',(11.2444921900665,11.0302506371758,2.89504547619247));
#452=CARTESIAN_POINT('',(11.77238342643,12.021280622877,3.53476533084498));
#453=CARTESIAN_POINT('',(10.0119836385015,11.3227817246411,2.38836676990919));
#454=CARTESIAN_POINT('',(11.2998824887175,11.2429867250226,2.52657576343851));
#455=CARTESIAN_POINT('',(11.8245992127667,12.2362450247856,3.17616765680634));
#456=CARTESIAN_POINT('',(10.1344910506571,11.7658190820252,1.62100355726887));
#457=CARTESIAN_POINT('',(11.4295559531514,11.6676529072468,1.79103235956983));
#458=CARTESIAN_POINT('',(11.9471066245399,12.6676822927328,2.46005420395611));
#459=CARTESIAN_POINT('',(10.2047826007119,11.9867058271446,1.23841649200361));
#460=CARTESIAN_POINT('',(11.50393517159,11.8797233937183,1.42371550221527));
#461=CARTESIAN_POINT('',(12.0173981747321,12.8841551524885,2.10253842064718));
#462=CARTESIAN_POINT('',(10.3635332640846,12.4331933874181,0.465077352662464));
#463=CARTESIAN_POINT('',(11.6715578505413,12.3089514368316,0.680270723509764));
#464=CARTESIAN_POINT('',(12.1761488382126,13.324088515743,1.37838502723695));
#465=CARTESIAN_POINT('',(10.4524447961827,12.6587536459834,0.0743955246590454));
#466=CARTESIAN_POINT('',(11.765362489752,12.5261665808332,0.304043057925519));
#467=CARTESIAN_POINT('',(12.2650603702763,13.5475753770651,1.01177140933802));
#468=CARTESIAN_POINT('',(10.6448520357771,13.1083244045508,-0.704283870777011));
#469=CARTESIAN_POINT('',(11.967916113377,12.9597500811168,-0.446945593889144));
#470=CARTESIAN_POINT('',(12.457467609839,13.9949851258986,0.279191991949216));
#471=CARTESIAN_POINT('',(10.7483491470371,13.332334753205,-1.09228117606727));
#472=CARTESIAN_POINT('',(12.0767524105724,13.1761752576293,-0.821804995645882));
#473=CARTESIAN_POINT('',(12.5609647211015,14.2189080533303,-0.0867737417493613));
#474=CARTESIAN_POINT('',(10.9672745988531,13.7778902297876,-1.86400589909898));
#475=CARTESIAN_POINT('',(12.3064912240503,13.6073113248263,-1.56855456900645));
#476=CARTESIAN_POINT('',(12.7798901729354,14.6657717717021,-0.816665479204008));
#477=CARTESIAN_POINT('',(11.0826513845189,13.9994417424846,-2.2477443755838));
#478=CARTESIAN_POINT('',(12.4274060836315,13.8220483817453,-1.94049006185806));
#479=CARTESIAN_POINT('',(12.8952669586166,14.888712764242,-1.18059362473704));
#480=CARTESIAN_POINT('',(11.3237929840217,14.4410462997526,-3.01262590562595));
#481=CARTESIAN_POINT('',(12.6796748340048,14.2507554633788,-2.68303250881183));
#482=CARTESIAN_POINT('',(13.1364085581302,15.3341621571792,-1.90792010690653));
#483=CARTESIAN_POINT('',(11.4495541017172,14.6610998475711,-3.39376983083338));
#484=CARTESIAN_POINT('',(12.8110666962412,14.4647201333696,-3.05363018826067));
#485=CARTESIAN_POINT('',(13.2621696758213,15.5566706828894,-2.27131858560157));
#486=CARTESIAN_POINT('',(11.5796005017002,14.8804943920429,-3.77377232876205));
#487=CARTESIAN_POINT('',(12.9463739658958,14.6778858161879,-3.42284398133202));
#488=CARTESIAN_POINT('',(13.3922160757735,15.778849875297,-2.63457144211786));
#489=(BOUNDED_SURFACE() B_SPLINE_SURFACE(3,2,((#387,#388,#389),(#390,#391,#392),(#393,#394,
#395),(#396,#397,#398),(#399,#400,#401),(#402,#403,#404),(#405,#406,#407),(#408,#409,#410),
(#411,#412,#413),(#414,#415,#416),(#417,#418,#419),(#420,#421,#422),(#423,#424,#425),(#426,#427,
#428),(#429,#430,#431),(#432,#433,#434),(#435,#436,#437),(#438,#439,#440),(#441,#442,#443),
(#444,#445,#446),(#447,#448,#449),(#450,#451,#452),(#453,#454,#455),(#456,#457,#458),(#459,#460,
#461),(#462,#463,#464),(#465,#466,#467),(#468,#469,#470),(#471,#472,#473),(#474,#475,#476),
(#477,#478,#479),(#480,#481,#482),(#483,#484,#485),(#486,#487,#488)),.UNSPECIFIED.,.F.,.F.,
.F.) B_SPLINE_SURFACE_WITH_KNOTS((4,2,2,2,2,2,2,2,2,2,2,2,2,2,2,2,4),(3,3),(0.,1.37778937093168,
2.75607536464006,4.14014697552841,5.52408276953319,6.87032435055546,8.21657171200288,
9.56006825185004,10.9035389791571,12.2424508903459,13.5813870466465,14.9230528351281,
16.2647130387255,17.6438299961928,19.0230797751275,20.3965778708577,21.7695891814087),(0.,1.),
.UNSPECIFIED.) GEOMETRIC_REPRESENTATION_ITEM() RATIONAL_B_SPLINE_SURFACE(((1.,0.814387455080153,
1.),(1.,0.81604981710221,1.),(1.,0.817739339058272,1.),(1.,0.821124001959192,1.),(1.,
0.8228191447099,1.),(1.,0.826172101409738,1.),(1.,0.827829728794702,1.),(1.,0.831026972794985,
1.),(1.,0.832566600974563,1.),(1.,0.835400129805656,1.),(1.,0.836699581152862,1.),(1.,
0.839013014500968,1.),(1.,0.840026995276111,1.),(1.,0.841683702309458,1.),(1.,0.842327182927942,
1.),(1.,0.843185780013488,1.),(1.,0.843400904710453,1.),(1.,0.843381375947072,1.),(1.,
0.843148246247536,1.),(1.,0.842258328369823,1.),(1.,0.841601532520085,1.),(1.,0.839923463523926,
1.),(1.,0.838901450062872,1.),(1.,0.836576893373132,1.),(1.,0.835274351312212,1.),(1.,
0.832438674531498,1.),(1.,0.830900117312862,1.),(1.,0.827707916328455,1.),(1.,0.826054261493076,
1.),(1.,0.822710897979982,1.),(1.,0.821021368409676,1.),(1.,0.817648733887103,1.),(1.,
0.815965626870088,1.),(1.,0.81430965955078,1.))) REPRESENTATION_ITEM('') SURFACE());
#490=CARTESIAN_POINT('',(13.3922160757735,15.778849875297,-2.63457144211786));
#491=CARTESIAN_POINT('',(13.2621696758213,15.5566706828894,-2.27131858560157));
#492=CARTESIAN_POINT('',(13.1364085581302,15.3341621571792,-1.90792010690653));
#493=CARTESIAN_POINT('',(12.8952669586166,14.888712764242,-1.18059362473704));
#494=CARTESIAN_POINT('',(12.7798901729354,14.6657717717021,-0.816665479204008));
#495=CARTESIAN_POINT('',(12.5609647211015,14.2189080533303,-0.086773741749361));
#496=CARTESIAN_POINT('',(12.457467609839,13.9949851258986,0.279191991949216));
#497=CARTESIAN_POINT('',(12.2650603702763,13.5475753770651,1.01177140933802));
#498=CARTESIAN_POINT('',(12.1761488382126,13.324088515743,1.37838502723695));
#499=CARTESIAN_POINT('',(12.0173981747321,12.8841551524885,2.10253842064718));
#500=CARTESIAN_POINT('',(11.9471066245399,12.6676822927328,2.46005420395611));
#501=CARTESIAN_POINT('',(11.8245992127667,12.2362450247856,3.17616765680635));
#502=CARTESIAN_POINT('',(11.77238342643,12.021280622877,3.53476533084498));
#503=CARTESIAN_POINT('',(11.6879263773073,11.5938430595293,4.25253537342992));
#504=CARTESIAN_POINT('',(11.6556446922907,11.3813657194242,4.61170508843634));
#505=CARTESIAN_POINT('',(11.6121352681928,10.9588627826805,5.33150280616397));
#506=CARTESIAN_POINT('',(11.6009071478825,10.748837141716,5.69213078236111));
#507=CARTESIAN_POINT('',(11.5999618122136,10.3306860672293,6.41612617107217));
#508=CARTESIAN_POINT('',(11.6103179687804,10.1225695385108,6.77949873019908));
#509=CARTESIAN_POINT('',(11.652263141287,9.70885207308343,7.50765565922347));
#510=CARTESIAN_POINT('',(11.6838525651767,9.50325118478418,7.87244005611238));
#511=CARTESIAN_POINT('',(11.7671181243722,9.09381103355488,8.60389982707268));
#512=CARTESIAN_POINT('',(11.8188352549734,8.88997623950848,8.97057754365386));
#513=CARTESIAN_POINT('',(11.9405368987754,8.48402626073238,9.70471658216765));
#514=CARTESIAN_POINT('',(12.01052133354,8.2819110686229,10.0721779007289));
#515=CARTESIAN_POINT('',(12.1688328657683,7.87326077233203,10.8177916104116));
#516=CARTESIAN_POINT('',(12.2576186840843,7.66676036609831,11.1959552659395));
#517=CARTESIAN_POINT('',(12.4499360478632,7.25455486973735,11.9523464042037));
#518=CARTESIAN_POINT('',(12.5534690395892,7.04884985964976,12.3305738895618));
#519=CARTESIAN_POINT('',(12.7725980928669,6.63873042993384,13.0851530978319));
#520=CARTESIAN_POINT('',(12.8881419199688,6.43431420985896,13.4615060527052));
#521=CARTESIAN_POINT('',(13.1297240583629,6.02573130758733,14.2135698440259));
#522=CARTESIAN_POINT('',(13.2557585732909,5.82156456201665,14.5892808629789));
#523=CARTESIAN_POINT('',(13.3861195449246,5.61735979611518,14.9646320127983));
#524=B_SPLINE_CURVE_WITH_KNOTS('',3,(#490,#491,#492,#493,#494,#495,#496,#497,#498,#499,#500,
#501,#502,#503,#504,#505,#506,#507,#508,#509,#510,#511,#512,#513,#514,#515,#516,#517,#518,#519,
#520,#521,#522,#523),.UNSPECIFIED.,.F.,.F.,(4,2,2,2,2,2,2,2,2,2,2,2,2,2,2,2,4),(0.,
1.373011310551,2.7465094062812,4.12575918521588,5.50487614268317,6.84653634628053,
8.18820213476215,9.52713829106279,10.8660502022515,12.2095209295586,13.5530174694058,
14.8992648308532,16.2455064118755,17.6294422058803,19.0135138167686,20.391799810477,
21.7695891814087),.UNSPECIFIED.);
#525=CARTESIAN_POINT('',(12.5382142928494,7.08293523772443,12.2680036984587));
#526=VERTEX_POINT('',#525);
#527=EDGE_CURVE('E530',#384,#526,#524,.T.);
#528=ORIENTED_EDGE('',*,*,#527,.T.);
#529=CARTESIAN_POINT('',(11.5586752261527,-10.6377106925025,11.));
#530=CARTESIAN_POINT('',(12.9245511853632,-10.2343592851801,11.));
#531=CARTESIAN_POINT('',(13.371290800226,-10.1024343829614,12.3458562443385));
#532=CARTESIAN_POINT('',(11.4296471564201,-10.2006329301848,11.));
#533=CARTESIAN_POINT('',(12.7902803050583,-9.80975417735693,11.));
#534=CARTESIAN_POINT('',(13.2422627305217,-9.6785234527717,12.3350969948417));
#535=CARTESIAN_POINT('',(11.3049096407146,-9.76224073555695,11.));
#536=CARTESIAN_POINT('',(12.6599362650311,-9.38355782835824,11.));
#537=CARTESIAN_POINT('',(13.1175252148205,-9.25432504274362,12.3241320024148));
#538=CARTESIAN_POINT('',(11.0658152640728,-8.88247550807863,11.));
#539=CARTESIAN_POINT('',(12.4097699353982,-8.52961931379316,11.));
#540=CARTESIAN_POINT('',(12.8784308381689,-8.40526131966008,12.3021073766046));
#541=CARTESIAN_POINT('',(10.9514620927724,-8.44110147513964,11.));
#542=CARTESIAN_POINT('',(12.2899091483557,-8.10188549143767,11.));
#543=CARTESIAN_POINT('',(12.7640776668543,-7.98039582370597,12.2910477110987));
#544=CARTESIAN_POINT('',(10.7345836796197,-7.55350352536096,11.));
#545=CARTESIAN_POINT('',(12.0622856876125,-7.24314045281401,11.));
#546=CARTESIAN_POINT('',(12.5471992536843,-7.12845331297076,12.2691135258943));
#547=CARTESIAN_POINT('',(10.6321091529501,-7.10726711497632,11.));
#548=CARTESIAN_POINT('',(11.9545096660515,-6.81207483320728,11.));
#549=CARTESIAN_POINT('',(12.4447247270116,-6.70137440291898,12.2582399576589));
#550=CARTESIAN_POINT('',(10.4417143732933,-6.21172145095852,11.));
#551=CARTESIAN_POINT('',(11.7540495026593,-5.94849300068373,11.));
#552=CARTESIAN_POINT('',(12.2543299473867,-5.84688048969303,12.2372106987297));
#553=CARTESIAN_POINT('',(10.3537927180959,-5.76241249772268,11.));
#554=CARTESIAN_POINT('',(11.6612783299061,-5.51586119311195,11.));
#555=CARTESIAN_POINT('',(12.1664082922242,-5.41946552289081,12.2270549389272));
#556=CARTESIAN_POINT('',(10.1969212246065,-4.87296269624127,11.));
#557=CARTESIAN_POINT('',(11.4956230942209,-4.66089301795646,11.));
#558=CARTESIAN_POINT('',(12.0095367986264,-4.57589184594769,12.2083119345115));
#559=CARTESIAN_POINT('',(10.1275235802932,-4.43290149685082,11.));
#560=CARTESIAN_POINT('',(11.4221831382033,-4.23843893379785,11.));
#561=CARTESIAN_POINT('',(11.9401391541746,-4.1597405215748,12.1996897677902));
#562=CARTESIAN_POINT('',(10.0067221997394,-3.55028807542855,11.));
#563=CARTESIAN_POINT('',(11.2943058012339,-3.39249919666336,11.));
#564=CARTESIAN_POINT('',(11.819337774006,-3.32725941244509,12.1842981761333));
#565=CARTESIAN_POINT('',(9.95531854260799,-3.10773584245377,11.));
#566=CARTESIAN_POINT('',(11.2397737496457,-2.96873317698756,11.));
#567=CARTESIAN_POINT('',(11.7679341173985,-2.91092962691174,12.1775287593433));
#568=CARTESIAN_POINT('',(9.87236586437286,-2.22164860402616,11.));
#569=CARTESIAN_POINT('',(11.1517908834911,-2.12142123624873,11.));
#570=CARTESIAN_POINT('',(11.6849814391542,-2.07900552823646,12.1664297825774));
#571=CARTESIAN_POINT('',(9.84077721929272,-1.77811735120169,11.));
#572=CARTESIAN_POINT('',(11.1182193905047,-1.6975153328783,11.));
#573=CARTESIAN_POINT('',(11.6533927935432,-1.66341141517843,12.1620953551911));
#574=CARTESIAN_POINT('',(9.79850442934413,-0.890055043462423,11.));
#575=CARTESIAN_POINT('',(11.0733274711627,-0.849596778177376,11.));
#576=CARTESIAN_POINT('',(11.6111200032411,-0.832187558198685,12.156263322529));
#577=CARTESIAN_POINT('',(9.78781991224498,-0.445524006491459,11.));
#578=CARTESIAN_POINT('',(11.0619614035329,-0.425160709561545,11.));
#579=CARTESIAN_POINT('',(11.6004354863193,-0.416557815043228,12.1547656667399));
#580=CARTESIAN_POINT('',(9.78778833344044,0.444589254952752,11.));
#581=CARTESIAN_POINT('',(11.0619278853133,0.424268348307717,11.));
#582=CARTESIAN_POINT('',(11.6004039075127,0.415683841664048,12.1547612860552));
#583=CARTESIAN_POINT('',(9.79849173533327,0.890171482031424,11.));
#584=CARTESIAN_POINT('',(11.0733140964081,0.849708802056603,11.));
#585=CARTESIAN_POINT('',(11.6111073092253,0.832295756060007,12.1562616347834));
#586=CARTESIAN_POINT('',(9.84090087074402,1.78033077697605,11.));
#587=CARTESIAN_POINT('',(11.1183507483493,1.69963028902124,11.));
#588=CARTESIAN_POINT('',(11.6535164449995,1.66548396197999,12.1621123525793));
#589=CARTESIAN_POINT('',(9.8726069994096,2.22490782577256,11.));
#590=CARTESIAN_POINT('',(11.1520472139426,2.12453772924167,11.));
#591=CARTESIAN_POINT('',(11.6852225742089,2.0820602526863,12.1664627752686));
#592=CARTESIAN_POINT('',(9.95588372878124,3.11308125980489,11.));
#593=CARTESIAN_POINT('',(11.2403733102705,2.97384993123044,11.));
#594=CARTESIAN_POINT('',(11.7684993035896,2.91595362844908,12.1776036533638));
#595=CARTESIAN_POINT('',(10.0074943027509,3.55667385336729,11.));
#596=CARTESIAN_POINT('',(11.2951246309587,3.39861698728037,11.));
#597=CARTESIAN_POINT('',(11.8201098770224,3.33327051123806,12.1843990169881));
#598=CARTESIAN_POINT('',(10.128784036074,4.44135328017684,11.));
#599=CARTESIAN_POINT('',(11.4235172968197,4.24654937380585,11.));
#600=CARTESIAN_POINT('',(11.9413996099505,4.16772442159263,12.1998478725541));
#601=CARTESIAN_POINT('',(10.1984631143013,4.88244012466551,11.));
#602=CARTESIAN_POINT('',(11.4972540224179,4.66999656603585,11.));
#603=CARTESIAN_POINT('',(12.0110786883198,4.58486144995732,12.2085013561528));
#604=CARTESIAN_POINT('',(10.3559702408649,5.77398503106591,11.));
#605=CARTESIAN_POINT('',(11.6635769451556,5.52699967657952,11.));
#606=CARTESIAN_POINT('',(12.1685858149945,5.43046116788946,12.2273096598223));
#607=CARTESIAN_POINT('',(10.4442489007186,6.22436280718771,11.));
#608=CARTESIAN_POINT('',(11.756722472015,5.96067334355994,11.));
#609=CARTESIAN_POINT('',(12.2568644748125,5.8589163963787,12.2374995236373));
#610=CARTESIAN_POINT('',(10.6354057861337,7.12203094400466,11.));
#611=CARTESIAN_POINT('',(11.9579787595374,6.82633115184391,11.));
#612=CARTESIAN_POINT('',(12.4480213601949,6.7154882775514,12.2585948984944));
#613=CARTESIAN_POINT('',(10.7382854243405,7.56932100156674,11.));
#614=CARTESIAN_POINT('',(12.0661769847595,7.25843087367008,11.));
#615=CARTESIAN_POINT('',(12.5509009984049,7.14360489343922,12.2695004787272));
#616=CARTESIAN_POINT('',(10.9560042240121,8.45899886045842,11.));
#617=CARTESIAN_POINT('',(12.2946732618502,8.11922397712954,11.));
#618=CARTESIAN_POINT('',(12.7686197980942,7.99760579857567,12.2914941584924));
#619=CARTESIAN_POINT('',(11.0707922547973,8.90139927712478,11.));
#620=CARTESIAN_POINT('',(12.4149844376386,8.54797137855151,11.));
#621=CARTESIAN_POINT('',(12.8834078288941,8.42349200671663,12.3025813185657));
#622=CARTESIAN_POINT('',(11.3107797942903,9.78320578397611,11.));
#623=CARTESIAN_POINT('',(12.6660733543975,9.40393172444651,11.));
#624=CARTESIAN_POINT('',(13.1233953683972,9.27459283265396,12.3246561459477));
#625=CARTESIAN_POINT('',(11.4359755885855,10.2226128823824,11.));
#626=CARTESIAN_POINT('',(12.7968895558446,9.83113558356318,11.));
#627=CARTESIAN_POINT('',(13.2485911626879,9.69980763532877,12.335643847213));
#628=CARTESIAN_POINT('',(11.5654689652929,10.6607015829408,11.));
#629=CARTESIAN_POINT('',(12.9316367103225,10.2567424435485,11.));
#630=CARTESIAN_POINT('',(13.3780845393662,10.124733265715,12.3464231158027));
#631=(BOUNDED_SURFACE() B_SPLINE_SURFACE(3,2,((#529,#530,#531),(#532,#533,#534),(#535,#536,
#537),(#538,#539,#540),(#541,#542,#543),(#544,#545,#546),(#547,#548,#549),(#550,#551,#552),
(#553,#554,#555),(#556,#557,#558),(#559,#560,#561),(#562,#563,#564),(#565,#566,#567),(#568,#569,
#570),(#571,#572,#573),(#574,#575,#576),(#577,#578,#579),(#580,#581,#582),(#583,#584,#585),
(#586,#587,#588),(#589,#590,#591),(#592,#593,#594),(#595,#596,#597),(#598,#599,#600),(#601,#602,
#603),(#604,#605,#606),(#607,#608,#609),(#610,#611,#612),(#613,#614,#615),(#616,#617,#618),
(#619,#620,#621),(#622,#623,#624),(#625,#626,#627),(#628,#629,#630)),.UNSPECIFIED.,.F.,.F.,
.F.) B_SPLINE_SURFACE_WITH_KNOTS((4,2,2,2,2,2,2,2,2,2,2,2,2,2,2,2,4),(3,3),(0.,1.36722137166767,
2.73492664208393,4.10827146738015,5.48148388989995,6.81765221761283,8.1538264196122,
9.48732009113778,10.8207900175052,12.1574099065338,13.4940549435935,14.833398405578,
16.172735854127,17.5492994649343,18.9259963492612,20.2970092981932,21.6675350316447),(0.,1.),
.UNSPECIFIED.) GEOMETRIC_REPRESENTATION_ITEM() RATIONAL_B_SPLINE_SURFACE(((1.,0.814577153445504,
1.),(1.,0.816228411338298,1.),(1.,0.817905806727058,1.),(1.,0.821264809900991,1.),(1.,
0.822946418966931,1.),(1.,0.826271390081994,1.),(1.,0.827914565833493,1.),(1.,0.831083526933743,
1.),(1.,0.832609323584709,1.),(1.,0.835418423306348,1.),(1.,0.836707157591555,1.),(1.,
0.839003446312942,1.),(1.,0.840010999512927,1.),(1.,0.841661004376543,1.),(1.,0.842304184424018,
1.),(1.,0.843169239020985,1.),(1.,0.843391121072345,1.),(1.,0.843391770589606,1.),(1.,
0.84316949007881,1.),(1.,0.842301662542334,1.),(1.,0.841656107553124,1.),(1.,0.839999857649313,
1.),(1.,0.838988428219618,1.),(1.,0.83668354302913,1.),(1.,0.835390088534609,1.),(1.,
0.832571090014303,1.),(1.,0.831040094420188,1.),(1.,0.827860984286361,1.),(1.,0.826212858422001,
1.),(1.,0.822878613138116,1.),(1.,0.821192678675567,1.),(1.,0.817825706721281,1.),(1.,
0.816144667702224,1.),(1.,0.814490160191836,1.))) REPRESENTATION_ITEM('') SURFACE());
#632=CARTESIAN_POINT('',(13.3780845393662,10.124733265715,12.3464231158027));
#633=CARTESIAN_POINT('',(13.2485911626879,9.69980763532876,12.335643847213));
#634=CARTESIAN_POINT('',(13.1233953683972,9.27459283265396,12.3246561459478));
#635=CARTESIAN_POINT('',(12.8834078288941,8.42349200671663,12.3025813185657));
#636=CARTESIAN_POINT('',(12.7686197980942,7.99760579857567,12.2914941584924));
#637=CARTESIAN_POINT('',(12.5509009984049,7.14360489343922,12.2695004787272));
#638=CARTESIAN_POINT('',(12.4480213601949,6.7154882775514,12.2585948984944));
#639=CARTESIAN_POINT('',(12.2568644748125,5.8589163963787,12.2374995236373));
#640=CARTESIAN_POINT('',(12.1685858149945,5.43046116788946,12.2273096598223));
#641=CARTESIAN_POINT('',(12.0110786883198,4.58486144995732,12.2085013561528));
#642=CARTESIAN_POINT('',(11.9413996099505,4.16772442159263,12.1998478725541));
#643=CARTESIAN_POINT('',(11.8201098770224,3.33327051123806,12.1843990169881));
#644=CARTESIAN_POINT('',(11.7684993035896,2.91595362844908,12.1776036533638));
#645=CARTESIAN_POINT('',(11.6852225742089,2.0820602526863,12.1664627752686));
#646=CARTESIAN_POINT('',(11.6535164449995,1.66548396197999,12.1621123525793));
#647=CARTESIAN_POINT('',(11.6111073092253,0.832295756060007,12.1562616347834));
#648=CARTESIAN_POINT('',(11.6004039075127,0.415683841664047,12.1547612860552));
#649=CARTESIAN_POINT('',(11.6004354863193,-0.416557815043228,12.1547656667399));
#650=CARTESIAN_POINT('',(11.6111200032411,-0.832187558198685,12.156263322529));
#651=CARTESIAN_POINT('',(11.6533927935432,-1.66341141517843,12.1620953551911));
#652=CARTESIAN_POINT('',(11.6849814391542,-2.07900552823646,12.1664297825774));
#653=CARTESIAN_POINT('',(11.7679341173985,-2.91092962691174,12.1775287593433));
#654=CARTESIAN_POINT('',(11.819337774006,-3.32725941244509,12.1842981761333));
#655=CARTESIAN_POINT('',(11.9401391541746,-4.1597405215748,12.1996897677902));
#656=CARTESIAN_POINT('',(12.0095367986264,-4.57589184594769,12.2083119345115));
#657=CARTESIAN_POINT('',(12.1664082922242,-5.41946552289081,12.2270549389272));
#658=CARTESIAN_POINT('',(12.2543299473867,-5.84688048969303,12.2372106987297));
#659=CARTESIAN_POINT('',(12.4447247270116,-6.70137440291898,12.2582399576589));
#660=CARTESIAN_POINT('',(12.5471992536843,-7.12845331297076,12.2691135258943));
#661=CARTESIAN_POINT('',(12.7640776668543,-7.98039582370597,12.2910477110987));
#662=CARTESIAN_POINT('',(12.8784308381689,-8.40526131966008,12.3021073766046));
#663=CARTESIAN_POINT('',(13.1175252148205,-9.25432504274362,12.3241320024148));
#664=CARTESIAN_POINT('',(13.2422627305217,-9.6785234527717,12.3350969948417));
#665=CARTESIAN_POINT('',(13.371290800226,-10.1024343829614,12.3458562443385));
#666=B_SPLINE_CURVE_WITH_KNOTS('',3,(#632,#633,#634,#635,#636,#637,#638,#639,#640,#641,#642,
#643,#644,#645,#646,#647,#648,#649,#650,#651,#652,#653,#654,#655,#656,#657,#658,#659,#660,#661,
#662,#663,#664,#665),.UNSPECIFIED.,.F.,.F.,(4,2,2,2,2,2,2,2,2,2,2,2,2,2,2,2,4),(0.,
1.37052573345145,2.74153868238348,4.11823556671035,5.49479917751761,6.83413662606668,
8.17348008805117,9.51012512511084,10.8467450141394,12.1802149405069,13.5137086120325,
14.8498828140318,16.1860511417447,17.5592635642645,18.9326083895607,20.300313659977,
21.6675350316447),.UNSPECIFIED.);
#667=CARTESIAN_POINT('',(12.5382142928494,-7.08293523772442,12.2680036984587));
#668=VERTEX_POINT('',#667);
#669=EDGE_CURVE('E531',#526,#668,#666,.T.);
#670=ORIENTED_EDGE('',*,*,#669,.T.);
#671=CARTESIAN_POINT('',(11.5735039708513,-14.8702068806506,-3.75595383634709));
#672=CARTESIAN_POINT('',(12.9400163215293,-14.6678691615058,-3.40549462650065));
#673=CARTESIAN_POINT('',(13.3861195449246,-15.7684313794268,-2.61753972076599));
#674=CARTESIAN_POINT('',(11.443142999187,-14.6500285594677,-3.3745937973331));
#675=CARTESIAN_POINT('',(12.8043767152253,-14.4539536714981,-3.0349821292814));
#676=CARTESIAN_POINT('',(13.2557585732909,-15.5454701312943,-2.25301763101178));
#677=CARTESIAN_POINT('',(11.3171084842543,-14.4291853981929,-2.99208222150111));
#678=CARTESIAN_POINT('',(12.672691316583,-14.2392320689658,-2.66307340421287));
#679=CARTESIAN_POINT('',(13.1297240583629,-15.3221782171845,-1.88834853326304));
#680=CARTESIAN_POINT('',(11.0755263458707,-13.9859880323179,-2.22444186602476));
#681=CARTESIAN_POINT('',(12.4199461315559,-13.809004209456,-1.91789689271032));
#682=CARTESIAN_POINT('',(12.8881419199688,-14.8751633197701,-1.1584734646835));
#683=CARTESIAN_POINT('',(10.9599825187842,-13.7636333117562,-1.83931219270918));
#684=CARTESIAN_POINT('',(12.2988476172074,-13.5935029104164,-1.5446376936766));
#685=CARTESIAN_POINT('',(12.7725980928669,-14.651440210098,-0.793267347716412));
#686=CARTESIAN_POINT('',(10.7408534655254,-13.3164534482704,-1.06477394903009));
#687=CARTESIAN_POINT('',(12.0688786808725,-13.1608272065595,-0.795221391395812));
#688=CARTESIAN_POINT('',(12.5534690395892,-14.2030151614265,-0.0608038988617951));
#689=CARTESIAN_POINT('',(10.6373204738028,-13.091621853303,-0.675354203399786));
#690=CARTESIAN_POINT('',(11.9599954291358,-12.9436256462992,-0.419017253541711));
#691=CARTESIAN_POINT('',(12.4499360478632,-13.9783130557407,0.306455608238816));
#692=CARTESIAN_POINT('',(10.445003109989,-12.6403980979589,0.106188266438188));
#693=CARTESIAN_POINT('',(11.7575202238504,-12.5084855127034,0.334667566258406));
#694=CARTESIAN_POINT('',(12.2576186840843,-13.5293618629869,1.0416316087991));
#695=CARTESIAN_POINT('',(10.3562172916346,-12.4140060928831,0.498310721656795));
#696=CARTESIAN_POINT('',(11.6638394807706,-12.2904884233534,0.712249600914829));
#697=CARTESIAN_POINT('',(12.1688328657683,-13.3051127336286,1.40954803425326));
#698=CARTESIAN_POINT('',(10.1979057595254,-11.9658880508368,1.27447393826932));
#699=CARTESIAN_POINT('',(11.4966667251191,-11.8597328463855,1.45834014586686));
#700=CARTESIAN_POINT('',(12.01052133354,-12.8637174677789,2.13625642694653));
#701=CARTESIAN_POINT('',(10.1279213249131,-11.7442028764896,1.65844392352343));
#702=CARTESIAN_POINT('',(11.4226055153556,-11.6469146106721,1.82695214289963));
#703=CARTESIAN_POINT('',(11.9405368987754,-12.6465442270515,2.49502397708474));
#704=CARTESIAN_POINT('',(10.0062196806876,-11.299568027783,2.42857407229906));
#705=CARTESIAN_POINT('',(11.2937751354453,-11.2207552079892,2.56508188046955));
#706=CARTESIAN_POINT('',(11.8188352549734,-12.2137361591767,3.21365649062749));
#707=CARTESIAN_POINT('',(9.95450254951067,-11.0766183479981,2.81473424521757));
#708=CARTESIAN_POINT('',(11.2389091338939,-11.0072706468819,2.93484798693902));
#709=CARTESIAN_POINT('',(11.7671181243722,-11.9981013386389,3.57352145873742));
#710=CARTESIAN_POINT('',(9.87123699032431,-10.6302279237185,3.5879051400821));
#711=CARTESIAN_POINT('',(11.1505933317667,-10.580420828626,3.67417355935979));
#712=CARTESIAN_POINT('',(11.6838525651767,-11.5693586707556,4.29383691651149));
#713=CARTESIAN_POINT('',(9.83964756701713,-10.4067891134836,3.97491251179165));
#714=CARTESIAN_POINT('',(11.1170198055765,-10.3668711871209,4.04405238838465));
#715=CARTESIAN_POINT('',(11.652263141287,-11.3562465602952,4.65428470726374));
#716=CARTESIAN_POINT('',(9.79770239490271,-9.95941155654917,4.7497931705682));
#717=CARTESIAN_POINT('',(11.0724752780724,-9.93972359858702,4.78389371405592));
#718=CARTESIAN_POINT('',(11.6103179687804,-10.9325028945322,5.37665300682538));
#719=CARTESIAN_POINT('',(9.78734623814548,-9.7354728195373,5.13766644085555));
#720=CARTESIAN_POINT('',(11.0614582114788,-9.7259087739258,5.15423185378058));
#721=CARTESIAN_POINT('',(11.5999618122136,-10.7218712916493,5.73857348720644));
#722=CARTESIAN_POINT('',(9.78829157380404,-9.28836706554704,5.91207632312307));
#723=CARTESIAN_POINT('',(11.0624625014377,-9.29923871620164,5.89324607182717));
#724=CARTESIAN_POINT('',(11.6009071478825,-10.3039484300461,6.46270063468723));
#725=CARTESIAN_POINT('',(9.79951969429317,-9.06520000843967,6.29861300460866));
#726=CARTESIAN_POINT('',(11.0744068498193,-9.08615659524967,6.26231513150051));
#727=CARTESIAN_POINT('',(11.6121352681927,-10.0966482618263,6.82490216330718));
#728=CARTESIAN_POINT('',(9.84302911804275,-8.61938207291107,7.07079231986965));
#729=CARTESIAN_POINT('',(11.120610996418,-8.66047991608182,6.99960876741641));
#730=CARTESIAN_POINT('',(11.6556446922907,-9.68453662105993,7.55069929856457));
#731=CARTESIAN_POINT('',(9.87531080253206,-8.39673120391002,7.45643493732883));
#732=CARTESIAN_POINT('',(11.1549180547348,-8.44767160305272,7.36820357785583));
#733=CARTESIAN_POINT('',(11.6879263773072,-9.47972519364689,7.91429493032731));
#734=CARTESIAN_POINT('',(9.9597678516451,-7.95192777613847,8.22685707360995));
#735=CARTESIAN_POINT('',(11.2444921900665,-8.0223082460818,8.10495452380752));
#736=CARTESIAN_POINT('',(11.77238342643,-9.07183688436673,8.64335174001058));
#737=CARTESIAN_POINT('',(10.0119836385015,-7.7297771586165,8.6116332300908));
#738=CARTESIAN_POINT('',(11.2998824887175,-7.80957215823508,8.47342423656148));
#739=CARTESIAN_POINT('',(11.8245992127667,-8.86876438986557,9.00881520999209));
#740=CARTESIAN_POINT('',(10.1344910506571,-7.2867398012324,9.37899644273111));
#741=CARTESIAN_POINT('',(11.4295559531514,-7.38490597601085,9.20896764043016));
#742=CARTESIAN_POINT('',(11.9471066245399,-8.46431058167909,9.74050757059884));
#743=CARTESIAN_POINT('',(10.2047826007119,-7.06585305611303,9.76158350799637));
#744=CARTESIAN_POINT('',(11.50393517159,-7.1728354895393,9.57628449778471));
#745=CARTESIAN_POINT('',(12.017398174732,-8.26292926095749,10.1067364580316));
#746=CARTESIAN_POINT('',(10.3635332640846,-6.61936549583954,10.5349226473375));
#747=CARTESIAN_POINT('',(11.6715578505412,-6.74360744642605,10.3197292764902));
#748=CARTESIAN_POINT('',(12.1761488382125,-7.8557607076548,10.8498066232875));
#749=CARTESIAN_POINT('',(10.4524447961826,-6.39380523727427,10.9256044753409));
#750=CARTESIAN_POINT('',(11.765362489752,-6.5263923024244,10.6959569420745));
#751=CARTESIAN_POINT('',(12.2650603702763,-7.65000743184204,11.2266587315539));
#752=CARTESIAN_POINT('',(10.6448520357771,-5.94423447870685,11.704283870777));
#753=CARTESIAN_POINT('',(11.967916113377,-6.09280880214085,11.4469455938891));
#754=CARTESIAN_POINT('',(12.457467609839,-7.23927992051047,11.9804166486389));
#755=CARTESIAN_POINT('',(10.7483491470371,-5.72022413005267,12.0922811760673));
#756=CARTESIAN_POINT('',(12.0767524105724,-5.87638362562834,11.8218049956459));
#757=CARTESIAN_POINT('',(12.5609647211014,-7.03430576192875,12.3573224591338));
#758=CARTESIAN_POINT('',(10.9672745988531,-5.27466865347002,12.864005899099));
#759=CARTESIAN_POINT('',(12.3064912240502,-5.44524755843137,12.5685545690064));
#760=CARTESIAN_POINT('',(12.7798901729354,-6.62563283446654,13.1092636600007));
#761=CARTESIAN_POINT('',(11.0826513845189,-5.05311714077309,13.2477443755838));
#762=CARTESIAN_POINT('',(12.4274060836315,-5.23051050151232,12.940490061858));
#763=CARTESIAN_POINT('',(12.8952669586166,-6.42193231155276,13.4843002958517));
#764=CARTESIAN_POINT('',(11.3237929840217,-4.61151258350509,14.0126259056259));
#765=CARTESIAN_POINT('',(12.6796748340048,-4.80180341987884,13.6830325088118));
#766=CARTESIAN_POINT('',(13.1364085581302,-6.01477379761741,14.2337340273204));
#767=CARTESIAN_POINT('',(11.4495541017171,-4.39145903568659,14.3937698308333));
#768=CARTESIAN_POINT('',(12.8110666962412,-4.587838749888,14.0536301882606));
#769=CARTESIAN_POINT('',(13.2621696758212,-5.81131574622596,14.6081313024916));
#770=CARTESIAN_POINT('',(11.5796005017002,-4.17206449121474,14.773772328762));
#771=CARTESIAN_POINT('',(12.9463739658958,-4.37467306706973,14.422843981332));
#772=CARTESIAN_POINT('',(13.3922160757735,-5.6078191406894,14.982170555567));
#773=(BOUNDED_SURFACE() B_SPLINE_SURFACE(3,2,((#671,#672,#673),(#674,#675,#676),(#677,#678,
#679),(#680,#681,#682),(#683,#684,#685),(#686,#687,#688),(#689,#690,#691),(#692,#693,#694),
(#695,#696,#697),(#698,#699,#700),(#701,#702,#703),(#704,#705,#706),(#707,#708,#709),(#710,#711,
#712),(#713,#714,#715),(#716,#717,#718),(#719,#720,#721),(#722,#723,#724),(#725,#726,#727),
(#728,#729,#730),(#731,#732,#733),(#734,#735,#736),(#737,#738,#739),(#740,#741,#742),(#743,#744,
#745),(#746,#747,#748),(#749,#750,#751),(#752,#753,#754),(#755,#756,#757),(#758,#759,#760),
(#761,#762,#763),(#764,#765,#766),(#767,#768,#769),(#770,#771,#772)),.UNSPECIFIED.,.F.,.F.,
.F.) B_SPLINE_SURFACE_WITH_KNOTS((4,2,2,2,2,2,2,2,2,2,2,2,2,2,2,2,4),(3,3),(0.,1.37778937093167,
2.75607536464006,4.1401469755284,5.52408276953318,6.87032435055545,8.21657171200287,
9.56006825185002,10.9035389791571,12.2424508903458,13.5813870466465,14.9230528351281,
16.2647130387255,17.6438299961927,19.0230797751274,20.3965778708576,21.7695891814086),(0.,1.),
.UNSPECIFIED.) GEOMETRIC_REPRESENTATION_ITEM() RATIONAL_B_SPLINE_SURFACE(((1.,0.814387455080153,
1.),(1.,0.816049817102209,1.),(1.,0.817739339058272,1.),(1.,0.821124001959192,1.),(1.,
0.8228191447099,1.),(1.,0.826172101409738,1.),(1.,0.827829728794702,1.),(1.,0.831026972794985,
1.),(1.,0.832566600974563,1.),(1.,0.835400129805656,1.),(1.,0.836699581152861,1.),(1.,
0.839013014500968,1.),(1.,0.840026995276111,1.),(1.,0.841683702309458,1.),(1.,0.842327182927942,
1.),(1.,0.843185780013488,1.),(1.,0.843400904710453,1.),(1.,0.843381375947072,1.),(1.,
0.843148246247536,1.),(1.,0.842258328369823,1.),(1.,0.841601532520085,1.),(1.,0.839923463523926,
1.),(1.,0.838901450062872,1.),(1.,0.836576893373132,1.),(1.,0.835274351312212,1.),(1.,
0.832438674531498,1.),(1.,0.830900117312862,1.),(1.,0.827707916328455,1.),(1.,0.826054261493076,
1.),(1.,0.822710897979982,1.),(1.,0.821021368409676,1.),(1.,0.817648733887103,1.),(1.,
0.815965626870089,1.),(1.,0.814309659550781,1.))) REPRESENTATION_ITEM('') SURFACE());
#774=CARTESIAN_POINT('',(13.3922160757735,-5.6078191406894,14.982170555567));
#775=CARTESIAN_POINT('',(13.2621696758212,-5.81131574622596,14.6081313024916));
#776=CARTESIAN_POINT('',(13.1364085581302,-6.01477379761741,14.2337340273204));
#777=CARTESIAN_POINT('',(12.8952669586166,-6.42193231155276,13.4843002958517));
#778=CARTESIAN_POINT('',(12.7798901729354,-6.62563283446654,13.1092636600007));
#779=CARTESIAN_POINT('',(12.5609647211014,-7.03430576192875,12.3573224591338));
#780=CARTESIAN_POINT('',(12.457467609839,-7.23927992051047,11.9804166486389));
#781=CARTESIAN_POINT('',(12.2650603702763,-7.65000743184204,11.2266587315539));
#782=CARTESIAN_POINT('',(12.1761488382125,-7.8557607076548,10.8498066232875));
#783=CARTESIAN_POINT('',(12.017398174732,-8.26292926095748,10.1067364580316));
#784=CARTESIAN_POINT('',(11.9471066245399,-8.46431058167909,9.74050757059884));
#785=CARTESIAN_POINT('',(11.8245992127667,-8.86876438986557,9.00881520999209));
#786=CARTESIAN_POINT('',(11.77238342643,-9.07183688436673,8.64335174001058));
#787=CARTESIAN_POINT('',(11.6879263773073,-9.47972519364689,7.91429493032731));
#788=CARTESIAN_POINT('',(11.6556446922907,-9.68453662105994,7.55069929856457));
#789=CARTESIAN_POINT('',(11.6121352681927,-10.0966482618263,6.82490216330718));
#790=CARTESIAN_POINT('',(11.6009071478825,-10.3039484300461,6.46270063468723));
#791=CARTESIAN_POINT('',(11.5999618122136,-10.7218712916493,5.73857348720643));
#792=CARTESIAN_POINT('',(11.6103179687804,-10.9325028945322,5.37665300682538));
#793=CARTESIAN_POINT('',(11.652263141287,-11.3562465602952,4.65428470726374));
#794=CARTESIAN_POINT('',(11.6838525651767,-11.5693586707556,4.29383691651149));
#795=CARTESIAN_POINT('',(11.7671181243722,-11.9981013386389,3.57352145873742));
#796=CARTESIAN_POINT('',(11.8188352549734,-12.2137361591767,3.21365649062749));
#797=CARTESIAN_POINT('',(11.9405368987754,-12.6465442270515,2.49502397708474));
#798=CARTESIAN_POINT('',(12.01052133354,-12.8637174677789,2.13625642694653));
#799=CARTESIAN_POINT('',(12.1688328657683,-13.3051127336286,1.40954803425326));
#800=CARTESIAN_POINT('',(12.2576186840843,-13.5293618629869,1.0416316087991));
#801=CARTESIAN_POINT('',(12.4499360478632,-13.9783130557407,0.306455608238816));
#802=CARTESIAN_POINT('',(12.5534690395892,-14.2030151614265,-0.0608038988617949));
#803=CARTESIAN_POINT('',(12.7725980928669,-14.651440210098,-0.793267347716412));
#804=CARTESIAN_POINT('',(12.8881419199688,-14.8751633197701,-1.1584734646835));
#805=CARTESIAN_POINT('',(13.1297240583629,-15.3221782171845,-1.88834853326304));
#806=CARTESIAN_POINT('',(13.2557585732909,-15.5454701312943,-2.25301763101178));
#807=CARTESIAN_POINT('',(13.3861195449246,-15.7684313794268,-2.61753972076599));
#808=B_SPLINE_CURVE_WITH_KNOTS('',3,(#774,#775,#776,#777,#778,#779,#780,#781,#782,#783,#784,
#785,#786,#787,#788,#789,#790,#791,#792,#793,#794,#795,#796,#797,#798,#799,#800,#801,#802,#803,
#804,#805,#806,#807),.UNSPECIFIED.,.F.,.F.,(4,2,2,2,2,2,2,2,2,2,2,2,2,2,2,2,4),(0.,
1.373011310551,2.74650940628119,4.12575918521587,5.50487614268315,6.84653634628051,
8.18820213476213,9.52713829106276,10.8660502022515,12.2095209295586,13.5530174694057,
14.8992648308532,16.2455064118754,17.6294422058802,19.0135138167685,20.3917998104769,
21.7695891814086),.UNSPECIFIED.);
#809=CARTESIAN_POINT('',(12.5382142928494,-14.1658704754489,0.));
#810=VERTEX_POINT('',#809);
#811=EDGE_CURVE('E550',#668,#810,#808,.T.);
#812=ORIENTED_EDGE('',*,*,#811,.T.);
#813=CARTESIAN_POINT('',(11.5735039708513,-4.18235200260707,-14.7559538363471));
#814=CARTESIAN_POINT('',(12.9400163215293,-4.38468972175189,-14.4054946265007));
#815=CARTESIAN_POINT('',(13.3861195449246,-5.61735979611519,-14.9646320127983));
#816=CARTESIAN_POINT('',(11.4431429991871,-4.40253032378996,-14.3745937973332));
#817=CARTESIAN_POINT('',(12.8043767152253,-4.59860521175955,-14.0349821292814));
#818=CARTESIAN_POINT('',(13.2557585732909,-5.82156456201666,-14.589280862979));
#819=CARTESIAN_POINT('',(11.3171084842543,-4.62337348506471,-13.9920822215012));
#820=CARTESIAN_POINT('',(12.6726913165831,-4.81332681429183,-13.6630734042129));
#821=CARTESIAN_POINT('',(13.1297240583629,-6.02573130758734,-14.2135698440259));
#822=CARTESIAN_POINT('',(11.0755263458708,-5.0665708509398,-13.2244418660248));
#823=CARTESIAN_POINT('',(12.419946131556,-5.24355467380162,-12.9178968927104));
#824=CARTESIAN_POINT('',(12.8881419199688,-6.43431420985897,-13.4615060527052));
#825=CARTESIAN_POINT('',(10.9599825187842,-5.28892557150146,-12.8393121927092));
#826=CARTESIAN_POINT('',(12.2988476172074,-5.45905597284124,-12.5446376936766));
#827=CARTESIAN_POINT('',(12.7725980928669,-6.63873042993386,-13.0851530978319));
#828=CARTESIAN_POINT('',(10.7408534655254,-5.73610543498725,-12.0647739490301));
#829=CARTESIAN_POINT('',(12.0688786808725,-5.89173167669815,-11.7952213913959));
#830=CARTESIAN_POINT('',(12.5534690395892,-7.04884985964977,-12.3305738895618));
#831=CARTESIAN_POINT('',(10.6373204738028,-5.96093702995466,-11.6753542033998));
#832=CARTESIAN_POINT('',(11.9599954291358,-6.10893323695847,-11.4190172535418));
#833=CARTESIAN_POINT('',(12.4499360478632,-7.25455486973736,-11.9523464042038));
#834=CARTESIAN_POINT('',(10.445003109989,-6.41216078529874,-10.8938117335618));
#835=CARTESIAN_POINT('',(11.7575202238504,-6.5440733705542,-10.6653324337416));
#836=CARTESIAN_POINT('',(12.2576186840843,-7.66676036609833,-11.1959552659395));
#837=CARTESIAN_POINT('',(10.3562172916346,-6.63855279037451,-10.5016892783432));
#838=CARTESIAN_POINT('',(11.6638394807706,-6.76207045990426,-10.2877503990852));
#839=CARTESIAN_POINT('',(12.1688328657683,-7.87326077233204,-10.8177916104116));
#840=CARTESIAN_POINT('',(10.1979057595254,-7.08667083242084,-9.72552606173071));
#841=CARTESIAN_POINT('',(11.4966667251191,-7.19282603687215,-9.54165985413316));
#842=CARTESIAN_POINT('',(12.01052133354,-8.28191106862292,-10.0721779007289));
#843=CARTESIAN_POINT('',(10.1279213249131,-7.30835600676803,-9.34155607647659));
#844=CARTESIAN_POINT('',(11.4226055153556,-7.40564427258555,-9.1730478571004));
#845=CARTESIAN_POINT('',(11.9405368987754,-8.4840262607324,-9.70471658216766));
#846=CARTESIAN_POINT('',(10.0062196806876,-7.75299085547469,-8.57142592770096));
#847=CARTESIAN_POINT('',(11.2937751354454,-7.83180367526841,-8.43491811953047));
#848=CARTESIAN_POINT('',(11.8188352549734,-8.88997623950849,-8.97057754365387));
#849=CARTESIAN_POINT('',(9.95450254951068,-7.97594053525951,-8.18526575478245));
#850=CARTESIAN_POINT('',(11.2389091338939,-8.04528823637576,-8.065152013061));
#851=CARTESIAN_POINT('',(11.7671181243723,-9.09381103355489,-8.60389982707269));
#852=CARTESIAN_POINT('',(9.87123699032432,-8.42233095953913,-7.41209485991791));
#853=CARTESIAN_POINT('',(11.1505933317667,-8.47213805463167,-7.32582644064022));
#854=CARTESIAN_POINT('',(11.6838525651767,-9.50325118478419,-7.87244005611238));
#855=CARTESIAN_POINT('',(9.83964756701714,-8.64576976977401,-7.02508748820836));
#856=CARTESIAN_POINT('',(11.1170198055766,-8.68568769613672,-6.95594761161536));
#857=CARTESIAN_POINT('',(11.652263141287,-9.70885207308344,-7.50765565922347));
#858=CARTESIAN_POINT('',(9.79770239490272,-9.09314732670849,-6.2502068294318));
#859=CARTESIAN_POINT('',(11.0724752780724,-9.11283528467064,-6.21610628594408));
#860=CARTESIAN_POINT('',(11.6103179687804,-10.1225695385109,-6.77949873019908));
#861=CARTESIAN_POINT('',(9.78734623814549,-9.31708606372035,-5.86233355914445));
#862=CARTESIAN_POINT('',(11.0614582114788,-9.32665010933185,-5.84576814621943));
#863=CARTESIAN_POINT('',(11.5999618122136,-10.3306860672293,-6.41612617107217));
#864=CARTESIAN_POINT('',(9.78829157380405,-9.76419181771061,-5.08792367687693));
#865=CARTESIAN_POINT('',(11.0624625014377,-9.75332016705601,-5.10675392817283));
#866=CARTESIAN_POINT('',(11.6009071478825,-10.748837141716,-5.6921307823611));
#867=CARTESIAN_POINT('',(9.79951969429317,-9.98735887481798,-4.70138699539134));
#868=CARTESIAN_POINT('',(11.0744068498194,-9.96640228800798,-4.73768486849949));
#869=CARTESIAN_POINT('',(11.6121352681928,-10.9588627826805,-5.33150280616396));
#870=CARTESIAN_POINT('',(9.84302911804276,-10.4331768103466,-3.92920768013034));
#871=CARTESIAN_POINT('',(11.1206109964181,-10.3920789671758,-4.00039123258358));
#872=CARTESIAN_POINT('',(11.6556446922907,-11.3813657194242,-4.61170508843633));
#873=CARTESIAN_POINT('',(9.87531080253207,-10.6558276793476,-3.54356506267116));
#874=CARTESIAN_POINT('',(11.1549180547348,-10.6048872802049,-3.63179642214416));
#875=CARTESIAN_POINT('',(11.6879263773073,-11.5938430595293,-4.25253537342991));
#876=CARTESIAN_POINT('',(9.95976785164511,-11.1006311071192,-2.77314292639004));
#877=CARTESIAN_POINT('',(11.2444921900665,-11.0302506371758,-2.89504547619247));
#878=CARTESIAN_POINT('',(11.77238342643,-12.021280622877,-3.53476533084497));
#879=CARTESIAN_POINT('',(10.0119836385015,-11.3227817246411,-2.38836676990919));
#880=CARTESIAN_POINT('',(11.2998824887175,-11.2429867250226,-2.5265757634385));
#881=CARTESIAN_POINT('',(11.8245992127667,-12.2362450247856,-3.17616765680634));
#882=CARTESIAN_POINT('',(10.1344910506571,-11.7658190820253,-1.62100355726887));
#883=CARTESIAN_POINT('',(11.4295559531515,-11.6676529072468,-1.79103235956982));
#884=CARTESIAN_POINT('',(11.9471066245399,-12.6676822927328,-2.46005420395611));
#885=CARTESIAN_POINT('',(10.2047826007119,-11.9867058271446,-1.23841649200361));
#886=CARTESIAN_POINT('',(11.50393517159,-11.8797233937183,-1.42371550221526));
#887=CARTESIAN_POINT('',(12.0173981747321,-12.8841551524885,-2.10253842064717));
#888=CARTESIAN_POINT('',(10.3635332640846,-12.4331933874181,-0.465077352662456));
#889=CARTESIAN_POINT('',(11.6715578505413,-12.3089514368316,-0.680270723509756));
#890=CARTESIAN_POINT('',(12.1761488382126,-13.324088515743,-1.37838502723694));
#891=CARTESIAN_POINT('',(10.4524447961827,-12.6587536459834,-0.0743955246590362));
#892=CARTESIAN_POINT('',(11.765362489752,-12.5261665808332,-0.30404305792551));
#893=CARTESIAN_POINT('',(12.2650603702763,-13.5475753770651,-1.011771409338));
#894=CARTESIAN_POINT('',(10.6448520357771,-13.1083244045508,0.70428387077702));
#895=CARTESIAN_POINT('',(11.967916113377,-12.9597500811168,0.446945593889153));
#896=CARTESIAN_POINT('',(12.457467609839,-13.9949851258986,-0.279191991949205));
#897=CARTESIAN_POINT('',(10.7483491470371,-13.332334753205,1.09228117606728));
#898=CARTESIAN_POINT('',(12.0767524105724,-13.1761752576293,0.82180499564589));
#899=CARTESIAN_POINT('',(12.5609647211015,-14.2189080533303,0.0867737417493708));
#900=CARTESIAN_POINT('',(10.9672745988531,-13.7778902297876,1.86400589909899));
#901=CARTESIAN_POINT('',(12.3064912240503,-13.6073113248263,1.56855456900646));
#902=CARTESIAN_POINT('',(12.7798901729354,-14.6657717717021,0.816665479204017));
#903=CARTESIAN_POINT('',(11.0826513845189,-13.9994417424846,2.24774437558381));
#904=CARTESIAN_POINT('',(12.4274060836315,-13.8220483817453,1.94049006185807));
#905=CARTESIAN_POINT('',(12.8952669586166,-14.888712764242,1.18059362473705));
#906=CARTESIAN_POINT('',(11.3237929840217,-14.4410462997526,3.01262590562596));
#907=CARTESIAN_POINT('',(12.6796748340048,-14.2507554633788,2.68303250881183));
#908=CARTESIAN_POINT('',(13.1364085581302,-15.3341621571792,1.90792010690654));
#909=CARTESIAN_POINT('',(11.4495541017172,-14.6610998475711,3.39376983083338));
#910=CARTESIAN_POINT('',(12.8110666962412,-14.4647201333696,3.05363018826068));
#911=CARTESIAN_POINT('',(13.2621696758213,-15.5566706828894,2.27131858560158));
#912=CARTESIAN_POINT('',(11.5796005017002,-14.8804943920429,3.77377232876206));
#913=CARTESIAN_POINT('',(12.9463739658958,-14.6778858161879,3.42284398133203));
#914=CARTESIAN_POINT('',(13.3922160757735,-15.778849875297,2.63457144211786));
#915=(BOUNDED_SURFACE() B_SPLINE_SURFACE(3,2,((#813,#814,#815),(#816,#817,#818),(#819,#820,
#821),(#822,#823,#824),(#825,#826,#827),(#828,#829,#830),(#831,#832,#833),(#834,#835,#836),
(#837,#838,#839),(#840,#841,#842),(#843,#844,#845),(#846,#847,#848),(#849,#850,#851),(#852,#853,
#854),(#855,#856,#857),(#858,#859,#860),(#861,#862,#863),(#864,#865,#866),(#867,#868,#869),
(#870,#871,#872),(#873,#874,#875),(#876,#877,#878),(#879,#880,#881),(#882,#883,#884),(#885,#886,
#887),(#888,#889,#890),(#891,#892,#893),(#894,#895,#896),(#897,#898,#899),(#900,#901,#902),
(#903,#904,#905),(#906,#907,#908),(#909,#910,#911),(#912,#913,#914)),.UNSPECIFIED.,.F.,.F.,
.F.) B_SPLINE_SURFACE_WITH_KNOTS((4,2,2,2,2,2,2,2,2,2,2,2,2,2,2,2,4),(3,3),(0.,1.37778937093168,
2.75607536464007,4.14014697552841,5.5240827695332,6.87032435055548,8.2165717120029,
9.56006825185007,10.9035389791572,12.2424508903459,13.5813870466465,14.9230528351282,
16.2647130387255,17.6438299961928,19.0230797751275,20.3965778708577,21.7695891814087),(0.,1.),
.UNSPECIFIED.) GEOMETRIC_REPRESENTATION_ITEM() RATIONAL_B_SPLINE_SURFACE(((1.,0.814387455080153,
1.),(1.,0.816049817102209,1.),(1.,0.817739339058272,1.),(1.,0.821124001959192,1.),(1.,
0.8228191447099,1.),(1.,0.826172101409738,1.),(1.,0.827829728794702,1.),(1.,0.831026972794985,
1.),(1.,0.832566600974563,1.),(1.,0.835400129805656,1.),(1.,0.836699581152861,1.),(1.,
0.839013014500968,1.),(1.,0.840026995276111,1.),(1.,0.841683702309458,1.),(1.,0.842327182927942,
1.),(1.,0.843185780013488,1.),(1.,0.843400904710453,1.),(1.,0.843381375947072,1.),(1.,
0.843148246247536,1.),(1.,0.842258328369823,1.),(1.,0.841601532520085,1.),(1.,0.839923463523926,
1.),(1.,0.838901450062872,1.),(1.,0.836576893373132,1.),(1.,0.835274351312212,1.),(1.,
0.832438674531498,1.),(1.,0.830900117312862,1.),(1.,0.827707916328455,1.),(1.,0.826054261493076,
1.),(1.,0.822710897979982,1.),(1.,0.821021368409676,1.),(1.,0.817648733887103,1.),(1.,
0.815965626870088,1.),(1.,0.81430965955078,1.))) REPRESENTATION_ITEM('') SURFACE());
#916=CARTESIAN_POINT('',(13.3922160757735,-15.778849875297,2.63457144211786));
#917=CARTESIAN_POINT('',(13.2621696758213,-15.5566706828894,2.27131858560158));
#918=CARTESIAN_POINT('',(13.1364085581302,-15.3341621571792,1.90792010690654));
#919=CARTESIAN_POINT('',(12.8952669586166,-14.888712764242,1.18059362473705));
#920=CARTESIAN_POINT('',(12.7798901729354,-14.6657717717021,0.816665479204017));
#921=CARTESIAN_POINT('',(12.5609647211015,-14.2189080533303,0.0867737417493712));
#922=CARTESIAN_POINT('',(12.457467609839,-13.9949851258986,-0.279191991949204));
#923=CARTESIAN_POINT('',(12.2650603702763,-13.5475753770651,-1.011771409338));
#924=CARTESIAN_POINT('',(12.1761488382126,-13.324088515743,-1.37838502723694));
#925=CARTESIAN_POINT('',(12.0173981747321,-12.8841551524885,-2.10253842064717));
#926=CARTESIAN_POINT('',(11.9471066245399,-12.6676822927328,-2.46005420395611));
#927=CARTESIAN_POINT('',(11.8245992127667,-12.2362450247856,-3.17616765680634));
#928=CARTESIAN_POINT('',(11.77238342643,-12.021280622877,-3.53476533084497));
#929=CARTESIAN_POINT('',(11.6879263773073,-11.5938430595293,-4.25253537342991));
#930=CARTESIAN_POINT('',(11.6556446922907,-11.3813657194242,-4.61170508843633));
#931=CARTESIAN_POINT('',(11.6121352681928,-10.9588627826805,-5.33150280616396));
#932=CARTESIAN_POINT('',(11.6009071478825,-10.748837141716,-5.6921307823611));
#933=CARTESIAN_POINT('',(11.5999618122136,-10.3306860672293,-6.41612617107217));
#934=CARTESIAN_POINT('',(11.6103179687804,-10.1225695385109,-6.77949873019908));
#935=CARTESIAN_POINT('',(11.652263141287,-9.70885207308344,-7.50765565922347));
#936=CARTESIAN_POINT('',(11.6838525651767,-9.50325118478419,-7.87244005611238));
#937=CARTESIAN_POINT('',(11.7671181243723,-9.09381103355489,-8.60389982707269));
#938=CARTESIAN_POINT('',(11.8188352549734,-8.88997623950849,-8.97057754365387));
#939=CARTESIAN_POINT('',(11.9405368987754,-8.4840262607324,-9.70471658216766));
#940=CARTESIAN_POINT('',(12.01052133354,-8.28191106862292,-10.0721779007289));
#941=CARTESIAN_POINT('',(12.1688328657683,-7.87326077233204,-10.8177916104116));
#942=CARTESIAN_POINT('',(12.2576186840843,-7.66676036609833,-11.1959552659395));
#943=CARTESIAN_POINT('',(12.4499360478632,-7.25455486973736,-11.9523464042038));
#944=CARTESIAN_POINT('',(12.5534690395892,-7.04884985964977,-12.3305738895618));
#945=CARTESIAN_POINT('',(12.7725980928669,-6.63873042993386,-13.0851530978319));
#946=CARTESIAN_POINT('',(12.8881419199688,-6.43431420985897,-13.4615060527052));
#947=CARTESIAN_POINT('',(13.1297240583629,-6.02573130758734,-14.2135698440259));
#948=CARTESIAN_POINT('',(13.2557585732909,-5.82156456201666,-14.589280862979));
#949=CARTESIAN_POINT('',(13.3861195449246,-5.61735979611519,-14.9646320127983));
#950=B_SPLINE_CURVE_WITH_KNOTS('',3,(#916,#917,#918,#919,#920,#921,#922,#923,#924,#925,#926,
#927,#928,#929,#930,#931,#932,#933,#934,#935,#936,#937,#938,#939,#940,#941,#942,#943,#944,#945,
#946,#947,#948,#949),.UNSPECIFIED.,.F.,.F.,(4,2,2,2,2,2,2,2,2,2,2,2,2,2,2,2,4),(0.,
1.373011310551,2.74650940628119,4.12575918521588,5.50487614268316,6.84653634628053,
8.18820213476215,9.52713829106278,10.8660502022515,12.2095209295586,13.5530174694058,
14.8992648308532,16.2455064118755,17.6294422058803,19.0135138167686,20.391799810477,
21.7695891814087),.UNSPECIFIED.);
#951=EDGE_CURVE('E551',#810,#240,#950,.T.);
#952=ORIENTED_EDGE('',*,*,#951,.T.);
#953=EDGE_LOOP('',(#244,#386,#528,#670,#812,#952));
#954=FACE_BOUND('',#953,.T.);
#955=CARTESIAN_POINT('',(13.384322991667,0.,0.));
#956=DIRECTION('',(-1.,0.,0.));
#957=DIRECTION('',(0.,0.,1.));
#958=AXIS2_PLACEMENT_3D('',#955,#956,#957);
#959=CIRCLE('',#958,15.9803564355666);
#960=CARTESIAN_POINT('',(13.384322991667,0.,15.9803564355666));
#961=VERTEX_POINT('',#960);
#962=EDGE_CURVE('E461',#961,#961,#959,.T.);
#963=ORIENTED_EDGE('',*,*,#962,.T.);
#964=EDGE_LOOP('',(#963));
#965=FACE_BOUND('',#964,.T.);
#966=ADVANCED_FACE('F281',(#954,#965),#100,.T.);
#967=CARTESIAN_POINT('',(14.2,0.,0.));
#968=DIRECTION('',(-1.,0.,0.));
#969=DIRECTION('',(0.,0.,1.));
#970=AXIS2_PLACEMENT_3D('',#967,#968,#969);
#971=TOROIDAL_SURFACE('',#970,15.6,0.899999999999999);
#972=ORIENTED_EDGE('',*,*,#962,.F.);
#973=EDGE_LOOP('',(#972));
#974=FACE_BOUND('',#973,.T.);
#975=ORIENTED_EDGE('',*,*,#42,.T.);
#976=EDGE_LOOP('',(#975));
#977=FACE_BOUND('',#976,.T.);
#978=ADVANCED_FACE('F233',(#974,#977),#971,.T.);
#979=CARTESIAN_POINT('',(0.,12.7017059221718,0.));
#980=DIRECTION('',(1.,0.,0.));
#981=DIRECTION('',(0.,0.,-1.));
#982=AXIS2_PLACEMENT_3D('',#979,#980,#981);
#983=PLANE('',#982);
#984=CARTESIAN_POINT('',(0.,0.,0.));
#985=DIRECTION('',(1.,0.,0.));
#986=DIRECTION('',(0.,0.,-1.));
#987=AXIS2_PLACEMENT_3D('',#984,#985,#986);
#988=CIRCLE('',#987,11.);
#989=CARTESIAN_POINT('',(0.,0.,-11.));
#990=VERTEX_POINT('',#989);
#991=CARTESIAN_POINT('',(0.,9.52627944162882,-5.50000000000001));
#992=VERTEX_POINT('',#991);
#993=EDGE_CURVE('E506',#990,#992,#988,.T.);
#994=ORIENTED_EDGE('',*,*,#993,.F.);
#995=CARTESIAN_POINT('',(0.,-9.52627944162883,-5.5));
#996=VERTEX_POINT('',#995);
#997=EDGE_CURVE('E163',#996,#990,#988,.T.);
#998=ORIENTED_EDGE('',*,*,#997,.F.);
#999=CARTESIAN_POINT('',(0.,-9.52627944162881,5.50000000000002));
#1000=VERTEX_POINT('',#999);
#1001=EDGE_CURVE('E527',#1000,#996,#988,.T.);
#1002=ORIENTED_EDGE('',*,*,#1001,.F.);
#1003=CARTESIAN_POINT('',(0.,0.,11.));
#1004=VERTEX_POINT('',#1003);
#1005=EDGE_CURVE('E494',#1004,#1000,#988,.T.);
#1006=ORIENTED_EDGE('',*,*,#1005,.F.);
#1007=CARTESIAN_POINT('',(0.,0.,0.));
#1008=DIRECTION('',(-1.,0.,0.));
#1009=DIRECTION('',(0.,0.,1.));
#1010=AXIS2_PLACEMENT_3D('',#1007,#1008,#1009);
#1011=CIRCLE('',#1010,11.);
#1012=CARTESIAN_POINT('',(0.,9.52627944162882,5.50000000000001));
#1013=VERTEX_POINT('',#1012);
#1014=EDGE_CURVE('E164',#1004,#1013,#1011,.T.);
#1015=ORIENTED_EDGE('',*,*,#1014,.T.);
#1016=EDGE_CURVE('E489',#992,#1013,#988,.T.);
#1017=ORIENTED_EDGE('',*,*,#1016,.F.);
#1018=EDGE_LOOP('',(#994,#998,#1002,#1006,#1015,#1017));
#1019=FACE_BOUND('',#1018,.T.);
#1020=ADVANCED_FACE('F490',(#1019),#983,.F.);
#1021=CARTESIAN_POINT('',(0.,0.,0.));
#1022=DIRECTION('',(1.,0.,0.));
#1023=DIRECTION('',(0.,0.,-1.));
#1024=AXIS2_PLACEMENT_3D('',#1021,#1022,#1023);
#1025=CONICAL_SURFACE('',#1024,11.,1.0471975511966);
#1026=CARTESIAN_POINT('',(0.98254703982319,6.35073749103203,11.0002));
#1027=CARTESIAN_POINT('',(0.901959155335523,6.49034297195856,10.7583962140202));
#1028=CARTESIAN_POINT('',(0.825028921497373,6.63046897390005,10.515690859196));
#1029=CARTESIAN_POINT('',(0.679498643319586,6.91184468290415,10.0283338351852));
#1030=CARTESIAN_POINT('',(0.610901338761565,7.05309474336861,9.78368155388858));
#1031=CARTESIAN_POINT('',(0.418936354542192,7.47912088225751,9.0457826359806));
#1032=CARTESIAN_POINT('',(0.30974772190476,7.76557875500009,8.54962304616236));
#1033=CARTESIAN_POINT('',(0.181714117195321,8.19424982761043,7.80714296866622));
#1034=CARTESIAN_POINT('',(0.145242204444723,8.33518236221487,7.56304065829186));
#1035=CARTESIAN_POINT('',(0.0840813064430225,8.61769996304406,7.07370581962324));
#1036=CARTESIAN_POINT('',(0.0593925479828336,8.7592850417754,6.82847326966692));
#1037=CARTESIAN_POINT('',(0.0224303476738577,9.0426912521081,6.33759931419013));
#1038=CARTESIAN_POINT('',(0.010142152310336,9.18451190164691,6.0919587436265));
#1039=CARTESIAN_POINT('',(-0.0017570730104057,9.46828461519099,5.60044998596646));
#1040=CARTESIAN_POINT('',(-0.0013684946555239,9.61023667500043,5.35458180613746));
#1041=CARTESIAN_POINT('',(0.0112011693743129,9.8756168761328,4.89492981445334));
#1042=CARTESIAN_POINT('',(0.0218490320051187,9.99906394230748,4.68111322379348));
#1043=CARTESIAN_POINT('',(0.0525316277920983,10.2456741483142,4.25397181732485));
#1044=CARTESIAN_POINT('',(0.0725670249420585,10.3688372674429,4.04064703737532));
#1045=CARTESIAN_POINT('',(0.121675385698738,10.6148126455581,3.61460518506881));
#1046=CARTESIAN_POINT('',(0.15075581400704,10.7376245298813,3.40188876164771));
#1047=CARTESIAN_POINT('',(0.217443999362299,10.9826725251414,2.97745318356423));
#1048=CARTESIAN_POINT('',(0.255052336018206,11.1049085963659,2.76573409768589));
#1049=CARTESIAN_POINT('',(0.38161991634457,11.4759630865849,2.12304886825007));
#1050=CARTESIAN_POINT('',(0.483199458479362,11.7237069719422,1.69394387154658));
#1051=CARTESIAN_POINT('',(0.713743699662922,12.2155005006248,0.842132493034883));
#1052=CARTESIAN_POINT('',(0.842654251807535,12.4595564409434,0.419415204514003));
#1053=CARTESIAN_POINT('',(0.982547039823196,12.7018213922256,-0.000199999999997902));
#1054=B_SPLINE_CURVE_WITH_KNOTS('',3,(#1026,#1027,#1028,#1029,#1030,#1031,#1032,#1033,#1034,
#1035,#1036,#1037,#1038,#1039,#1040,#1041,#1042,#1043,#1044,#1045,#1046,#1047,#1048,#1049,#1050,
#1051,#1052,#1053),.UNSPECIFIED.,.F.,.F.,(4,2,2,2,2,2,2,2,2,2,2,2,2,4),(0.,0.871755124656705,
1.74379610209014,3.49159027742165,4.34403665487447,5.19649943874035,6.04794680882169,
6.89936787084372,7.64056020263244,8.38180496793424,9.1236630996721,9.86557166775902,
11.3820155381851,12.8954827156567),.UNSPECIFIED.);
#1055=CARTESIAN_POINT('',(0.982480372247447,12.7017059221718,0.));
#1056=VERTEX_POINT('',#1055);
#1057=EDGE_CURVE('E197',#1013,#1056,#1054,.T.);
#1058=ORIENTED_EDGE('',*,*,#1057,.T.);
#1059=CARTESIAN_POINT('',(0.982547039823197,12.7018213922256,0.0002));
#1060=CARTESIAN_POINT('',(0.90195915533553,12.5622159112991,-0.241603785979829));
#1061=CARTESIAN_POINT('',(0.82502892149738,12.4220899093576,-0.484309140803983));
#1062=CARTESIAN_POINT('',(0.679498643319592,12.1407142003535,-0.971666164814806));
#1063=CARTESIAN_POINT('',(0.610901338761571,11.999464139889,-1.21631844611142));
#1064=CARTESIAN_POINT('',(0.418936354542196,11.5734380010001,-1.9542173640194));
#1065=CARTESIAN_POINT('',(0.309747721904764,11.2869801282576,-2.45037695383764));
#1066=CARTESIAN_POINT('',(0.181714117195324,10.8583090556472,-3.19285703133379));
#1067=CARTESIAN_POINT('',(0.145242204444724,10.7173765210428,-3.43695934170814));
#1068=CARTESIAN_POINT('',(0.0840813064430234,10.4348589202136,-3.92629418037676));
#1069=CARTESIAN_POINT('',(0.0593925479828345,10.2932738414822,-4.17152673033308));
#1070=CARTESIAN_POINT('',(0.0224303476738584,10.0098676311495,-4.66240068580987));
#1071=CARTESIAN_POINT('',(0.0101421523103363,9.86804698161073,-4.9080412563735));
#1072=CARTESIAN_POINT('',(-0.00175707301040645,9.58427426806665,-5.39955001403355));
#1073=CARTESIAN_POINT('',(-0.00136849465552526,9.44232220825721,-5.64541819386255));
#1074=CARTESIAN_POINT('',(0.0112011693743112,9.17694200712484,-6.10507018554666));
#1075=CARTESIAN_POINT('',(0.0218490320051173,9.05349494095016,-6.31888677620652));
#1076=CARTESIAN_POINT('',(0.0525316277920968,8.80688473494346,-6.74602818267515));
#1077=CARTESIAN_POINT('',(0.0725670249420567,8.68372161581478,-6.95935296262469));
#1078=CARTESIAN_POINT('',(0.121675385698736,8.43774623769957,-7.3853948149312));
#1079=CARTESIAN_POINT('',(0.150755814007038,8.31493435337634,-7.5981112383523));
#1080=CARTESIAN_POINT('',(0.217443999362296,8.06988635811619,-8.02254681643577));
#1081=CARTESIAN_POINT('',(0.255052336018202,7.94765028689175,-8.23426590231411));
#1082=CARTESIAN_POINT('',(0.381619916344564,7.57659579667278,-8.87695113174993));
#1083=CARTESIAN_POINT('',(0.483199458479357,7.3288519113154,-9.30605612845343));
#1084=CARTESIAN_POINT('',(0.713743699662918,6.83705838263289,-10.1578675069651));
#1085=CARTESIAN_POINT('',(0.84265425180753,6.59300244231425,-10.580584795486));
#1086=CARTESIAN_POINT('',(0.982547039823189,6.35073749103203,-11.0002));
#1087=B_SPLINE_CURVE_WITH_KNOTS('',3,(#1059,#1060,#1061,#1062,#1063,#1064,#1065,#1066,#1067,
#1068,#1069,#1070,#1071,#1072,#1073,#1074,#1075,#1076,#1077,#1078,#1079,#1080,#1081,#1082,#1083,
#1084,#1085,#1086),.UNSPECIFIED.,.F.,.F.,(4,2,2,2,2,2,2,2,2,2,2,2,2,4),(0.,0.871755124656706,
1.74379610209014,3.49159027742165,4.34403665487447,5.19649943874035,6.0479468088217,
6.89936787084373,7.64056020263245,8.38180496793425,9.1236630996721,9.86557166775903,
11.3820155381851,12.8954827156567),.UNSPECIFIED.);
#1088=EDGE_CURVE('E177',#1056,#992,#1087,.T.);
#1089=ORIENTED_EDGE('',*,*,#1088,.T.);
#1090=ORIENTED_EDGE('',*,*,#1016,.T.);
#1091=EDGE_LOOP('',(#1058,#1089,#1090));
#1092=FACE_BOUND('',#1091,.T.);
#1093=ADVANCED_FACE('F501',(#1092),#1025,.T.);
#1094=CARTESIAN_POINT('',(5.45962897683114,-17.2470997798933,11.));
#1095=CARTESIAN_POINT('',(5.34231348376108,-17.0060889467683,11.));
#1096=CARTESIAN_POINT('',(5.2255689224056,-16.7648003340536,11.));
#1097=CARTESIAN_POINT('',(4.99335060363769,-16.2816096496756,11.));
#1098=CARTESIAN_POINT('',(4.87787685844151,-16.0397075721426,11.));
#1099=CARTESIAN_POINT('',(4.53352602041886,-15.3129324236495,11.));
#1100=CARTESIAN_POINT('',(4.30675272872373,-14.8270588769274,11.));
#1101=CARTESIAN_POINT('',(3.85897116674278,-13.8495672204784,11.));
#1102=CARTESIAN_POINT('',(3.63799941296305,-13.3579323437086,11.));
#1103=CARTESIAN_POINT('',(3.20484722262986,-12.3708181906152,11.));
#1104=CARTESIAN_POINT('',(2.99266638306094,-11.8753390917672,11.));
#1105=CARTESIAN_POINT('',(2.57247367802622,-10.8630233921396,11.));
#1106=CARTESIAN_POINT('',(2.36484129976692,-10.3460284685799,11.));
#1107=CARTESIAN_POINT('',(1.96483982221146,-9.30605625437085,11.));
#1108=CARTESIAN_POINT('',(1.77247240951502,-8.78307830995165,11.));
#1109=CARTESIAN_POINT('',(1.40791696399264,-7.73124436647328,11.));
#1110=CARTESIAN_POINT('',(1.23568964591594,-7.20240209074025,11.));
#1111=CARTESIAN_POINT('',(0.916805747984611,-6.1370840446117,11.));
#1112=CARTESIAN_POINT('',(0.770141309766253,-5.60061067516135,11.));
#1113=CARTESIAN_POINT('',(0.574935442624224,-4.79156898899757,11.));
#1114=CARTESIAN_POINT('',(0.514137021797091,-4.52194135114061,11.));
#1115=CARTESIAN_POINT('',(0.401508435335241,-3.98080971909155,11.));
#1116=CARTESIAN_POINT('',(0.349678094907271,-3.70930576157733,11.));
#1117=CARTESIAN_POINT('',(0.255888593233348,-3.16459510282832,11.));
#1118=CARTESIAN_POINT('',(0.21392923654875,-2.89138843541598,11.));
#1119=CARTESIAN_POINT('',(0.140711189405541,-2.34354612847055,11.));
#1120=CARTESIAN_POINT('',(0.109452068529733,-2.0689105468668,11.));
#1121=CARTESIAN_POINT('',(0.0586581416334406,-1.52226132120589,11.));
#1122=CARTESIAN_POINT('',(0.0389718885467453,-1.25026183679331,11.));
#1123=CARTESIAN_POINT('',(0.011128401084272,-0.705673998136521,11.));
#1124=CARTESIAN_POINT('',(0.00297097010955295,-0.433085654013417,11.));
#1125=CARTESIAN_POINT('',(-0.00161987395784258,0.112191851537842,11.));
#1126=CARTESIAN_POINT('',(0.0019466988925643,0.384881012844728,11.));
#1127=CARTESIAN_POINT('',(0.0207143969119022,0.929861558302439,11.));
#1128=CARTESIAN_POINT('',(0.0359160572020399,1.20215292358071,11.));
#1129=CARTESIAN_POINT('',(0.0856729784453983,1.85095047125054,11.));
#1130=CARTESIAN_POINT('',(0.125437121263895,2.22706614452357,11.));
#1131=CARTESIAN_POINT('',(0.225037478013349,2.9766103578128,11.));
#1132=CARTESIAN_POINT('',(0.284876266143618,3.35003854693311,11.));
#1133=CARTESIAN_POINT('',(0.491340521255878,4.46580768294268,11.));
#1134=CARTESIAN_POINT('',(0.664879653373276,5.2032402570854,11.));
#1135=CARTESIAN_POINT('',(0.967143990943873,6.3061295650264,11.));
#1136=CARTESIAN_POINT('',(1.07633089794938,6.67727137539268,11.));
#1137=CARTESIAN_POINT('',(1.30638118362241,7.41595393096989,11.));
#1138=CARTESIAN_POINT('',(1.4272446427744,7.78349465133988,11.));
#1139=CARTESIAN_POINT('',(1.6786811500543,8.51508385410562,11.));
#1140=CARTESIAN_POINT('',(1.80925124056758,8.87913336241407,11.));
#1141=CARTESIAN_POINT('',(2.07853139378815,9.60419403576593,11.));
#1142=CARTESIAN_POINT('',(2.21724133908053,9.96520524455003,11.));
#1143=CARTESIAN_POINT('',(2.56570982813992,10.8471449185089,11.));
#1144=CARTESIAN_POINT('',(2.77923741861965,11.3665818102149,11.));
#1145=CARTESIAN_POINT('',(3.21741982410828,12.4007561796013,11.));
#1146=CARTESIAN_POINT('',(3.44207546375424,12.915493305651,11.));
#1147=CARTESIAN_POINT('',(3.90018345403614,13.9411926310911,11.));
#1148=CARTESIAN_POINT('',(4.13363815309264,14.4521537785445,11.));
#1149=CARTESIAN_POINT('',(4.60748399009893,15.4708244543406,11.));
#1150=CARTESIAN_POINT('',(4.84787494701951,15.9785340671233,11.));
#1151=CARTESIAN_POINT('',(5.334544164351,16.9919001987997,11.));
#1152=CARTESIAN_POINT('',(5.58082941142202,17.497553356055,11.));
#1153=CARTESIAN_POINT('',(6.07795336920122,18.5066162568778,11.));
#1154=CARTESIAN_POINT('',(6.3287921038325,19.0100259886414,11.));
#1155=CARTESIAN_POINT('',(6.83417262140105,20.0148835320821,11.));
#1156=CARTESIAN_POINT('',(7.08871382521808,20.5163316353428,11.));
#1157=CARTESIAN_POINT('',(7.60090805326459,21.5176369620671,11.));
#1158=CARTESIAN_POINT('',(7.85856109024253,22.0174941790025,11.));
#1159=CARTESIAN_POINT('',(8.58894370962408,23.4254623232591,11.));
#1160=CARTESIAN_POINT('',(9.06467783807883,24.3320145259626,11.));
#1161=CARTESIAN_POINT('',(10.0225256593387,26.1417834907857,11.));
#1162=CARTESIAN_POINT('',(10.5046396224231,27.0450001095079,11.));
#1163=CARTESIAN_POINT('',(11.472364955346,28.8463130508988,11.));
#1164=CARTESIAN_POINT('',(11.9579628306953,29.7444166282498,11.));
#1165=CARTESIAN_POINT('',(12.6891583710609,31.0900134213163,11.));
#1166=CARTESIAN_POINT('',(12.9333491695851,31.5382722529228,11.));
#1167=CARTESIAN_POINT('',(13.4225690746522,32.4343313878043,11.));
#1168=CARTESIAN_POINT('',(13.6675981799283,32.8821316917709,11.));
#1169=CARTESIAN_POINT('',(13.9129970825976,33.3297293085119,11.));
#1170=B_SPLINE_CURVE_WITH_KNOTS('',3,(#1094,#1095,#1096,#1097,#1098,#1099,#1100,#1101,#1102,
#1103,#1104,#1105,#1106,#1107,#1108,#1109,#1110,#1111,#1112,#1113,#1114,#1115,#1116,#1117,#1118,
#1119,#1120,#1121,#1122,#1123,#1124,#1125,#1126,#1127,#1128,#1129,#1130,#1131,#1132,#1133,#1134,
#1135,#1136,#1137,#1138,#1139,#1140,#1141,#1142,#1143,#1144,#1145,#1146,#1147,#1148,#1149,#1150,
#1151,#1152,#1153,#1154,#1155,#1156,#1157,#1158,#1159,#1160,#1161,#1162,#1163,#1164,#1165,#1166,
#1167,#1168,#1169),.UNSPECIFIED.,.F.,.F.,(4,2,2,2,2,2,2,2,2,2,2,2,2,2,2,2,2,2,2,2,2,2,2,2,2,2,2,
2,2,2,2,2,2,2,2,2,2,4),(0.,0.804139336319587,1.6082863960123,3.21680897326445,4.83377623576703,
6.45066928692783,8.12187818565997,9.79327147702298,11.4613481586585,13.12891114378,
13.9579782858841,14.7870292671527,15.6160638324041,16.4450650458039,17.262961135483,
18.0808432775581,18.8987244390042,19.7166432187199,20.8506417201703,21.984785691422,
24.2542515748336,25.4147583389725,26.5752731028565,27.7354356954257,28.8955815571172,
30.5802397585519,32.2650229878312,33.950259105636,35.6354512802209,37.3227509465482,
39.0100594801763,40.6971068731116,42.384161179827,45.4555127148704,48.526994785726,
51.5899154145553,53.1212821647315,54.652646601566),.UNSPECIFIED.);
#1171=CARTESIAN_POINT('',(0.982480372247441,6.35085296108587,11.));
#1172=VERTEX_POINT('',#1171);
#1173=EDGE_CURVE('E255',#1004,#1172,#1170,.T.);
#1174=ORIENTED_EDGE('',*,*,#1173,.T.);
#1175=EDGE_CURVE('E252',#1172,#1013,#1054,.T.);
#1176=ORIENTED_EDGE('',*,*,#1175,.T.);
#1177=ORIENTED_EDGE('',*,*,#1014,.F.);
#1178=EDGE_LOOP('',(#1174,#1176,#1177));
#1179=FACE_BOUND('',#1178,.T.);
#1180=ADVANCED_FACE('F230',(#1179),#1025,.T.);
#1181=CARTESIAN_POINT('',(0.982480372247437,-6.35085296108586,11.));
#1182=VERTEX_POINT('',#1181);
#1183=EDGE_CURVE('E591',#1182,#1004,#1170,.T.);
#1184=ORIENTED_EDGE('',*,*,#1183,.T.);
#1185=ORIENTED_EDGE('',*,*,#1005,.T.);
#1186=CARTESIAN_POINT('',(0.982547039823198,-12.7018213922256,-0.000200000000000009));
#1187=CARTESIAN_POINT('',(0.901959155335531,-12.5622159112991,0.241603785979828));
#1188=CARTESIAN_POINT('',(0.82502892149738,-12.4220899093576,0.484309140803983));
#1189=CARTESIAN_POINT('',(0.679498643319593,-12.1407142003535,0.971666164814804));
#1190=CARTESIAN_POINT('',(0.610901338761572,-11.999464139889,1.21631844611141));
#1191=CARTESIAN_POINT('',(0.418936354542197,-11.5734380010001,1.9542173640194));
#1192=CARTESIAN_POINT('',(0.309747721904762,-11.2869801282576,2.45037695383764));
#1193=CARTESIAN_POINT('',(0.181714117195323,-10.8583090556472,3.19285703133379));
#1194=CARTESIAN_POINT('',(0.145242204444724,-10.7173765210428,3.43695934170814));
#1195=CARTESIAN_POINT('',(0.084081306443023,-10.4348589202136,3.92629418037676));
#1196=CARTESIAN_POINT('',(0.0593925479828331,-10.2932738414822,4.17152673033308));
#1197=CARTESIAN_POINT('',(0.0224303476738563,-10.0098676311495,4.66240068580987));
#1198=CARTESIAN_POINT('',(0.0101421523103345,-9.86804698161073,4.9080412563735));
#1199=CARTESIAN_POINT('',(-0.00175707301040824,-9.58427426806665,5.39955001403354));
#1200=CARTESIAN_POINT('',(-0.00136849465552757,-9.44232220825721,5.64541819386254));
#1201=CARTESIAN_POINT('',(0.0112011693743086,-9.17694200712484,6.10507018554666));
#1202=CARTESIAN_POINT('',(0.0218490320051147,-9.05349494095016,6.31888677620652));
#1203=CARTESIAN_POINT('',(0.0525316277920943,-8.80688473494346,6.74602818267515));
#1204=CARTESIAN_POINT('',(0.0725670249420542,-8.68372161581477,6.95935296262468));
#1205=CARTESIAN_POINT('',(0.121675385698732,-8.43774623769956,7.3853948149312));
#1206=CARTESIAN_POINT('',(0.150755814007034,-8.31493435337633,7.5981112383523));
#1207=CARTESIAN_POINT('',(0.217443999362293,-8.06988635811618,8.02254681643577));
#1208=CARTESIAN_POINT('',(0.2550523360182,-7.94765028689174,8.23426590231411));
#1209=CARTESIAN_POINT('',(0.381619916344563,-7.57659579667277,8.87695113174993));
#1210=CARTESIAN_POINT('',(0.483199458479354,-7.3288519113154,9.30605612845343));
#1211=CARTESIAN_POINT('',(0.713743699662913,-6.83705838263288,10.1578675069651));
#1212=CARTESIAN_POINT('',(0.842654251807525,-6.59300244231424,10.580584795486));
#1213=CARTESIAN_POINT('',(0.982547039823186,-6.35073749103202,11.0002));
#1214=B_SPLINE_CURVE_WITH_KNOTS('',3,(#1186,#1187,#1188,#1189,#1190,#1191,#1192,#1193,#1194,
#1195,#1196,#1197,#1198,#1199,#1200,#1201,#1202,#1203,#1204,#1205,#1206,#1207,#1208,#1209,#1210,
#1211,#1212,#1213),.UNSPECIFIED.,.F.,.F.,(4,2,2,2,2,2,2,2,2,2,2,2,2,4),(0.,0.871755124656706,
1.74379610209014,3.49159027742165,4.34403665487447,5.19649943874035,6.0479468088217,
6.89936787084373,7.64056020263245,8.38180496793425,9.12366309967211,9.86557166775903,
11.3820155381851,12.8954827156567),.UNSPECIFIED.);
#1215=EDGE_CURVE('E200',#1000,#1182,#1214,.T.);
#1216=ORIENTED_EDGE('',*,*,#1215,.T.);
#1217=EDGE_LOOP('',(#1184,#1185,#1216));
#1218=FACE_BOUND('',#1217,.T.);
#1219=ADVANCED_FACE('F224',(#1218),#1025,.T.);
#1220=CARTESIAN_POINT('',(0.982480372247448,-12.7017059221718,0.));
#1221=VERTEX_POINT('',#1220);
#1222=EDGE_CURVE('E186',#1221,#1000,#1214,.T.);
#1223=ORIENTED_EDGE('',*,*,#1222,.T.);
#1224=ORIENTED_EDGE('',*,*,#1001,.T.);
#1225=CARTESIAN_POINT('',(0.982547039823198,-6.35073749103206,-11.0002));
#1226=CARTESIAN_POINT('',(0.901959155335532,-6.49034297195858,-10.7583962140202));
#1227=CARTESIAN_POINT('',(0.825028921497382,-6.63046897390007,-10.515690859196));
#1228=CARTESIAN_POINT('',(0.679498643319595,-6.91184468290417,-10.0283338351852));
#1229=CARTESIAN_POINT('',(0.610901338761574,-7.05309474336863,-9.78368155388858));
#1230=CARTESIAN_POINT('',(0.418936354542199,-7.47912088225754,-9.0457826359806));
#1231=CARTESIAN_POINT('',(0.309747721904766,-7.76557875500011,-8.54962304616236));
#1232=CARTESIAN_POINT('',(0.181714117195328,-8.19424982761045,-7.80714296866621));
#1233=CARTESIAN_POINT('',(0.145242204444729,-8.33518236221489,-7.56304065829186));
#1234=CARTESIAN_POINT('',(0.0840813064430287,-8.61769996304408,-7.07370581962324));
#1235=CARTESIAN_POINT('',(0.0593925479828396,-8.75928504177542,-6.82847326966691));
#1236=CARTESIAN_POINT('',(0.0224303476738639,-9.04269125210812,-6.33759931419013));
#1237=CARTESIAN_POINT('',(0.0101421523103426,-9.18451190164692,-6.0919587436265));
#1238=CARTESIAN_POINT('',(-0.00175707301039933,-9.46828461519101,-5.60044998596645));
#1239=CARTESIAN_POINT('',(-0.00136849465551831,-9.61023667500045,-5.35458180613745));
#1240=CARTESIAN_POINT('',(0.0112011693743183,-9.87561687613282,-4.89492981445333));
#1241=CARTESIAN_POINT('',(0.0218490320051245,-9.9990639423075,-4.68111322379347));
#1242=CARTESIAN_POINT('',(0.052531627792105,-10.2456741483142,-4.25397181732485));
#1243=CARTESIAN_POINT('',(0.0725670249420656,-10.3688372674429,-4.04064703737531));
#1244=CARTESIAN_POINT('',(0.121675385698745,-10.6148126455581,-3.6146051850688));
#1245=CARTESIAN_POINT('',(0.150755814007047,-10.7376245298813,-3.4018887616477));
#1246=CARTESIAN_POINT('',(0.217443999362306,-10.9826725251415,-2.97745318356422));
#1247=CARTESIAN_POINT('',(0.255052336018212,-11.1049085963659,-2.76573409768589));
#1248=CARTESIAN_POINT('',(0.381619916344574,-11.4759630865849,-2.12304886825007));
#1249=CARTESIAN_POINT('',(0.483199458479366,-11.7237069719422,-1.69394387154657));
#1250=CARTESIAN_POINT('',(0.713743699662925,-12.2155005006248,-0.842132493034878));
#1251=CARTESIAN_POINT('',(0.842654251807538,-12.4595564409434,-0.419415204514));
#1252=CARTESIAN_POINT('',(0.982547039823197,-12.7018213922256,0.000199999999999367));
#1253=B_SPLINE_CURVE_WITH_KNOTS('',3,(#1225,#1226,#1227,#1228,#1229,#1230,#1231,#1232,#1233,
#1234,#1235,#1236,#1237,#1238,#1239,#1240,#1241,#1242,#1243,#1244,#1245,#1246,#1247,#1248,#1249,
#1250,#1251,#1252),.UNSPECIFIED.,.F.,.F.,(4,2,2,2,2,2,2,2,2,2,2,2,2,4),(0.,0.871755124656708,
1.74379610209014,3.49159027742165,4.34403665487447,5.19649943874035,6.0479468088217,
6.89936787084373,7.64056020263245,8.38180496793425,9.1236630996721,9.86557166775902,
11.3820155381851,12.8954827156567),.UNSPECIFIED.);
#1254=EDGE_CURVE('E167',#996,#1221,#1253,.T.);
#1255=ORIENTED_EDGE('',*,*,#1254,.T.);
#1256=EDGE_LOOP('',(#1223,#1224,#1255));
#1257=FACE_BOUND('',#1256,.T.);
#1258=ADVANCED_FACE('F226',(#1257),#1025,.T.);
#1259=CARTESIAN_POINT('',(0.98248037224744,6.35085296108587,-11.));
#1260=VERTEX_POINT('',#1259);
#1261=EDGE_CURVE('E175',#992,#1260,#1087,.T.);
#1262=ORIENTED_EDGE('',*,*,#1261,.T.);
#1263=CARTESIAN_POINT('',(5.45962897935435,-17.2470997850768,-11.));
#1264=CARTESIAN_POINT('',(5.34231348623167,-17.0060889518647,-11.));
#1265=CARTESIAN_POINT('',(5.2255689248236,-16.7648003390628,-11.));
#1266=CARTESIAN_POINT('',(4.9933506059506,-16.2816096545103,-11.));
#1267=CARTESIAN_POINT('',(4.87787686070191,-16.03970757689,-11.));
#1268=CARTESIAN_POINT('',(4.53352602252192,-15.3129324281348,-11.));
#1269=CARTESIAN_POINT('',(4.30675273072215,-14.8270588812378,-11.));
#1270=CARTESIAN_POINT('',(3.85897116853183,-13.8495672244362,-11.));
#1271=CARTESIAN_POINT('',(3.63799941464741,-13.3579323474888,-11.));
#1272=CARTESIAN_POINT('',(3.20484722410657,-12.3708181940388,-11.));
#1273=CARTESIAN_POINT('',(2.99266638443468,-11.875339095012,-11.));
#1274=CARTESIAN_POINT('',(2.57247367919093,-10.8630233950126,-11.));
#1275=CARTESIAN_POINT('',(2.3648413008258,-10.3460284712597,-11.));
#1276=CARTESIAN_POINT('',(1.96483982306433,-9.3060562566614,-11.));
#1277=CARTESIAN_POINT('',(1.7724724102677,-8.78307831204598,-11.));
#1278=CARTESIAN_POINT('',(1.40791696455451,-7.73124436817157,-11.));
#1279=CARTESIAN_POINT('',(1.23568964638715,-7.20240209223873,-11.));
#1280=CARTESIAN_POINT('',(0.91680574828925,-6.13708404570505,-11.));
#1281=CARTESIAN_POINT('',(0.770141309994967,-5.60061067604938,-11.));
#1282=CARTESIAN_POINT('',(0.574935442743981,-4.79156898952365,-11.));
#1283=CARTESIAN_POINT('',(0.514137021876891,-4.52194135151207,-11.));
#1284=CARTESIAN_POINT('',(0.401508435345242,-3.98080971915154,-11.));
#1285=CARTESIAN_POINT('',(0.34967809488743,-3.70930576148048,-11.));
#1286=CARTESIAN_POINT('',(0.255888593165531,-3.16459510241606,-11.));
#1287=CARTESIAN_POINT('',(0.213929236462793,-2.89138843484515,-11.));
#1288=CARTESIAN_POINT('',(0.140711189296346,-2.3435461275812,-11.));
#1289=CARTESIAN_POINT('',(0.10945206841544,-2.06891054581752,-11.));
#1290=CARTESIAN_POINT('',(0.058658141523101,-1.52226131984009,-11.));
#1291=CARTESIAN_POINT('',(0.0389718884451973,-1.25026183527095,-11.));
#1292=CARTESIAN_POINT('',(0.0111284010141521,-0.705673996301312,-11.));
#1293=CARTESIAN_POINT('',(0.00297097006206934,-0.433085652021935,-11.));
#1294=CARTESIAN_POINT('',(-0.00161987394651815,0.112191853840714,-11.));
#1295=CARTESIAN_POINT('',(0.00194669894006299,0.384881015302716,-11.));
#1296=CARTESIAN_POINT('',(0.0207143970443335,0.929861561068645,-11.));
#1297=CARTESIAN_POINT('',(0.0359160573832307,1.20215292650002,-11.));
#1298=CARTESIAN_POINT('',(0.0856729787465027,1.85095047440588,-11.));
#1299=CARTESIAN_POINT('',(0.125437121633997,2.22706614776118,-11.));
#1300=CARTESIAN_POINT('',(0.225037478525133,2.9766103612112,-11.));
#1301=CARTESIAN_POINT('',(0.284876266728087,3.35003855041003,-11.));
#1302=CARTESIAN_POINT('',(0.491340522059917,4.46580768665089,-11.));
#1303=CARTESIAN_POINT('',(0.664879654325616,5.20324026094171,-11.));
#1304=CARTESIAN_POINT('',(0.967143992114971,6.30612956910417,-11.));
#1305=CARTESIAN_POINT('',(1.07633089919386,6.67727137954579,-11.));
#1306=CARTESIAN_POINT('',(1.30638118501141,7.41595393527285,-11.));
#1307=CARTESIAN_POINT('',(1.42724464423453,7.78349465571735,-11.));
#1308=CARTESIAN_POINT('',(1.67868115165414,8.51508385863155,-11.));
#1309=CARTESIAN_POINT('',(1.809251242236,8.87913336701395,-11.));
#1310=CARTESIAN_POINT('',(2.07853139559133,9.60419404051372,-11.));
#1311=CARTESIAN_POINT('',(2.21724134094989,9.96520524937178,-11.));
#1312=CARTESIAN_POINT('',(2.56570983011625,10.847144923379,-11.));
#1313=CARTESIAN_POINT('',(2.77923742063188,11.366581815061,-11.));
#1314=CARTESIAN_POINT('',(3.21741982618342,12.4007561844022,-11.));
#1315=CARTESIAN_POINT('',(3.44207546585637,12.9154933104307,-11.));
#1316=CARTESIAN_POINT('',(3.90018345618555,13.9411926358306,-11.));
#1317=CARTESIAN_POINT('',(4.13363815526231,14.452153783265,-11.));
#1318=CARTESIAN_POINT('',(4.60748399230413,15.4708244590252,-11.));
#1319=CARTESIAN_POINT('',(4.84787494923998,15.9785340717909,-11.));
#1320=CARTESIAN_POINT('',(5.33454416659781,16.991900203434,-11.));
#1321=CARTESIAN_POINT('',(5.5808294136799,17.4975533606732,-11.));
#1322=CARTESIAN_POINT('',(6.07795337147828,18.5066162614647,-11.));
#1323=CARTESIAN_POINT('',(6.32879210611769,19.0100259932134,-11.));
#1324=CARTESIAN_POINT('',(6.83417262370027,20.0148835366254,-11.));
#1325=CARTESIAN_POINT('',(7.08871382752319,20.5163316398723,-11.));
#1326=CARTESIAN_POINT('',(7.60090805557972,21.5176369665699,-11.));
#1327=CARTESIAN_POINT('',(7.85856109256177,22.0174941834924,-11.));
#1328=CARTESIAN_POINT('',(8.58894371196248,23.425462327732,-11.));
#1329=CARTESIAN_POINT('',(9.06467784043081,24.3320145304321,-11.));
#1330=CARTESIAN_POINT('',(10.022525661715,26.1417834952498,-11.));
#1331=CARTESIAN_POINT('',(10.5046396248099,27.04500011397,-11.));
#1332=CARTESIAN_POINT('',(11.4723649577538,28.8463130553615,-11.));
#1333=CARTESIAN_POINT('',(11.9579628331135,29.744416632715,-11.));
#1334=CARTESIAN_POINT('',(12.6891583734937,31.0900134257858,-11.));
#1335=CARTESIAN_POINT('',(12.9333491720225,31.5382722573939,-11.));
#1336=CARTESIAN_POINT('',(13.4225690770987,32.4343313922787,-11.));
#1337=CARTESIAN_POINT('',(13.6675981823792,32.882131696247,-11.));
#1338=CARTESIAN_POINT('',(13.9129970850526,33.3297293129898,-11.));
#1339=B_SPLINE_CURVE_WITH_KNOTS('',3,(#1263,#1264,#1265,#1266,#1267,#1268,#1269,#1270,#1271,
#1272,#1273,#1274,#1275,#1276,#1277,#1278,#1279,#1280,#1281,#1282,#1283,#1284,#1285,#1286,#1287,
#1288,#1289,#1290,#1291,#1292,#1293,#1294,#1295,#1296,#1297,#1298,#1299,#1300,#1301,#1302,#1303,
#1304,#1305,#1306,#1307,#1308,#1309,#1310,#1311,#1312,#1313,#1314,#1315,#1316,#1317,#1318,#1319,
#1320,#1321,#1322,#1323,#1324,#1325,#1326,#1327,#1328,#1329,#1330,#1331,#1332,#1333,#1334,#1335,
#1336,#1337,#1338),.UNSPECIFIED.,.F.,.F.,(4,2,2,2,2,2,2,2,2,2,2,2,2,2,2,2,2,2,2,2,2,2,2,2,2,2,2,
2,2,2,2,2,2,2,2,2,2,4),(0.,0.804139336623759,1.60828639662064,3.21680897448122,4.83377623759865,
6.45066928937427,8.12187818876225,9.79327148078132,11.4613481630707,13.1289111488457,
13.9579782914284,14.7870292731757,15.6160638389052,16.4450650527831,17.2629611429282,
18.0808432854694,18.8987244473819,19.716643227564,20.8506417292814,21.9847857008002,
24.254251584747,25.414758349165,26.575273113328,27.7354357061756,28.8955815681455,
30.5802397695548,32.2650229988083,33.9502591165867,35.6354512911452,37.3227509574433,
39.0100594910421,40.6971068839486,42.3841611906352,45.4555127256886,48.526994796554,
51.5899154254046,53.1212821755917,54.6526466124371),.UNSPECIFIED.);
#1340=EDGE_CURVE('E165',#1260,#990,#1339,.F.);
#1341=ORIENTED_EDGE('',*,*,#1340,.T.);
#1342=ORIENTED_EDGE('',*,*,#993,.T.);
#1343=EDGE_LOOP('',(#1262,#1341,#1342));
#1344=FACE_BOUND('',#1343,.T.);
#1345=ADVANCED_FACE('F504',(#1344),#1025,.T.);
#1346=CARTESIAN_POINT('',(0.982480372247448,-6.3508529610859,-11.));
#1347=VERTEX_POINT('',#1346);
#1348=EDGE_CURVE('E156',#1347,#996,#1253,.T.);
#1349=ORIENTED_EDGE('',*,*,#1348,.T.);
#1350=ORIENTED_EDGE('',*,*,#997,.T.);
#1351=EDGE_CURVE('E143',#990,#1347,#1339,.F.);
#1352=ORIENTED_EDGE('',*,*,#1351,.T.);
#1353=EDGE_LOOP('',(#1349,#1350,#1352));
#1354=FACE_BOUND('',#1353,.T.);
#1355=ADVANCED_FACE('F159',(#1354),#1025,.T.);
#1356=CARTESIAN_POINT('',(15.1,6.35085296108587,-11.));
#1357=DIRECTION('',(0.,0.,1.));
#1358=DIRECTION('',(0.,-1.,0.));
#1359=AXIS2_PLACEMENT_3D('',#1356,#1357,#1358);
#1360=PLANE('',#1359);
#1361=DIRECTION('',(-1.,0.,0.));
#1362=VECTOR('',#1361,1.);
#1363=CARTESIAN_POINT('',(15.1,6.35085296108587,-11.));
#1364=LINE('',#1363,#1362);
#1365=CARTESIAN_POINT('',(10.4725099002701,6.35085296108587,-11.));
#1366=VERTEX_POINT('',#1365);
#1367=EDGE_CURVE('E155',#1366,#1260,#1364,.T.);
#1368=ORIENTED_EDGE('',*,*,#1367,.F.);
#1369=CARTESIAN_POINT('',(11.5596455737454,10.6409962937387,-11.));
#1370=CARTESIAN_POINT('',(11.4305304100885,10.2037041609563,-11.));
#1371=CARTESIAN_POINT('',(11.3057081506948,9.76509659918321,-11.));
#1372=CARTESIAN_POINT('',(11.0664512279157,8.88489794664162,-11.));
#1373=CARTESIAN_POINT('',(10.9520202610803,8.44330585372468,-11.));
#1374=CARTESIAN_POINT('',(10.7349947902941,7.55526586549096,-11.));
#1375=CARTESIAN_POINT('',(10.6324510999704,7.10880545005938,-11.));
#1376=CARTESIAN_POINT('',(10.4419306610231,6.21280862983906,-11.));
#1377=CARTESIAN_POINT('',(10.3539525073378,5.76327252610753,-11.));
#1378=CARTESIAN_POINT('',(10.1969867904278,4.87337908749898,-11.));
#1379=CARTESIAN_POINT('',(10.1275507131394,4.43310153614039,-11.));
#1380=CARTESIAN_POINT('',(10.0066902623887,3.55005293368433,-11.));
#1381=CARTESIAN_POINT('',(9.95526596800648,3.10728187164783,-11.));
#1382=CARTESIAN_POINT('',(9.8722924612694,2.22075700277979,-11.));
#1383=CARTESIAN_POINT('',(9.84070353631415,1.77700695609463,-11.));
#1384=CARTESIAN_POINT('',(9.79845162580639,0.88850703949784,-11.));
#1385=CARTESIAN_POINT('',(9.7877882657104,0.443757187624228,-11.));
#1386=CARTESIAN_POINT('',(9.78782004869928,-0.446623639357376,-11.));
#1387=CARTESIAN_POINT('',(9.79855757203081,-0.892254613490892,-11.));
#1388=CARTESIAN_POINT('',(9.84103825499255,-1.7825096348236,-11.));
#1389=CARTESIAN_POINT('',(9.87278180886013,-2.22713366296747,-11.));
#1390=CARTESIAN_POINT('',(9.95613528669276,-3.115400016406,-11.));
#1391=CARTESIAN_POINT('',(10.0077852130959,-3.55903854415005,-11.));
#1392=CARTESIAN_POINT('',(10.129154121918,-4.44380840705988,-11.));
#1393=CARTESIAN_POINT('',(10.1988730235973,-4.88493975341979,-11.));
#1394=CARTESIAN_POINT('',(10.3564610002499,-5.77657736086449,-11.));
#1395=CARTESIAN_POINT('',(10.444780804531,-6.22700328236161,-11.));
#1396=CARTESIAN_POINT('',(10.6360189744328,-7.1247669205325,-11.));
#1397=CARTESIAN_POINT('',(10.7389387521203,-7.5721043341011,-11.));
#1398=CARTESIAN_POINT('',(10.9567359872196,-8.46187507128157,-11.));
#1399=CARTESIAN_POINT('',(11.0715622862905,-8.904321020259,-11.));
#1400=CARTESIAN_POINT('',(11.3116248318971,-9.78621842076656,-11.));
#1401=CARTESIAN_POINT('',(11.4368573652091,-10.225670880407,-11.));
#1402=CARTESIAN_POINT('',(11.5663866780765,-10.6638049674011,-11.));
#1403=B_SPLINE_CURVE_WITH_KNOTS('',3,(#1369,#1370,#1371,#1372,#1373,#1374,#1375,#1376,#1377,
#1378,#1379,#1380,#1381,#1382,#1383,#1384,#1385,#1386,#1387,#1388,#1389,#1390,#1391,#1392,#1393,
#1394,#1395,#1396,#1397,#1398,#1399,#1400,#1401,#1402),.UNSPECIFIED.,.F.,.F.,(4,2,2,2,2,2,2,2,2,
2,2,2,2,2,2,2,4),(0.,1.36791223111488,2.73630918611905,4.11035517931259,5.48426854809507,
6.82109549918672,8.15792831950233,9.49207604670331,10.8261998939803,12.1629683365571,
13.4997618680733,14.8392558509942,16.1787438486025,17.5554729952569,18.932335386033,
20.3035094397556,21.6741963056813),.UNSPECIFIED.);
#1404=CARTESIAN_POINT('',(10.4725099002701,-6.3508529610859,-11.));
#1405=VERTEX_POINT('',#1404);
#1406=EDGE_CURVE('E149',#1366,#1405,#1403,.T.);
#1407=ORIENTED_EDGE('',*,*,#1406,.T.);
#1408=DIRECTION('',(-1.,0.,0.));
#1409=VECTOR('',#1408,1.);
#1410=CARTESIAN_POINT('',(15.1,-6.3508529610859,-11.));
#1411=LINE('',#1410,#1409);
#1412=EDGE_CURVE('E138',#1405,#1347,#1411,.T.);
#1413=ORIENTED_EDGE('',*,*,#1412,.T.);
#1414=ORIENTED_EDGE('',*,*,#1351,.F.);
#1415=ORIENTED_EDGE('',*,*,#1340,.F.);
#1416=EDGE_LOOP('',(#1368,#1407,#1413,#1414,#1415));
#1417=FACE_BOUND('',#1416,.T.);
#1418=ADVANCED_FACE('F141',(#1417),#1360,.F.);
#1419=CARTESIAN_POINT('',(15.1,-6.3508529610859,-11.));
#1420=DIRECTION('',(0.,0.866025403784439,0.5));
#1421=DIRECTION('',(0.,-0.5,0.866025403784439));
#1422=AXIS2_PLACEMENT_3D('',#1419,#1420,#1421);
#1423=PLANE('',#1422);
#1424=ORIENTED_EDGE('',*,*,#1412,.F.);
#1425=CARTESIAN_POINT('',(11.5735039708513,-4.18235200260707,-14.7559538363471));
#1426=CARTESIAN_POINT('',(11.4431429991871,-4.40253032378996,-14.3745937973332));
#1427=CARTESIAN_POINT('',(11.3171084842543,-4.62337348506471,-13.9920822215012));
#1428=CARTESIAN_POINT('',(11.0755263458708,-5.0665708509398,-13.2244418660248));
#1429=CARTESIAN_POINT('',(10.9599825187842,-5.28892557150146,-12.8393121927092));
#1430=CARTESIAN_POINT('',(10.7408534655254,-5.73610543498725,-12.0647739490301));
#1431=CARTESIAN_POINT('',(10.6373204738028,-5.96093702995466,-11.6753542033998));
#1432=CARTESIAN_POINT('',(10.445003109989,-6.41216078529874,-10.8938117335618));
#1433=CARTESIAN_POINT('',(10.3562172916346,-6.63855279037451,-10.5016892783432));
#1434=CARTESIAN_POINT('',(10.1979057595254,-7.08667083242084,-9.72552606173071));
#1435=CARTESIAN_POINT('',(10.1279213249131,-7.30835600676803,-9.34155607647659));
#1436=CARTESIAN_POINT('',(10.0062196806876,-7.75299085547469,-8.57142592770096));
#1437=CARTESIAN_POINT('',(9.95450254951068,-7.97594053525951,-8.18526575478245));
#1438=CARTESIAN_POINT('',(9.87123699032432,-8.42233095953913,-7.41209485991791));
#1439=CARTESIAN_POINT('',(9.83964756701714,-8.64576976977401,-7.02508748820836));
#1440=CARTESIAN_POINT('',(9.79770239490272,-9.09314732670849,-6.2502068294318));
#1441=CARTESIAN_POINT('',(9.78734623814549,-9.31708606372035,-5.86233355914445));
#1442=CARTESIAN_POINT('',(9.78829157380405,-9.76419181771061,-5.08792367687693));
#1443=CARTESIAN_POINT('',(9.79951969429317,-9.98735887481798,-4.70138699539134));
#1444=CARTESIAN_POINT('',(9.84302911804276,-10.4331768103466,-3.92920768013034));
#1445=CARTESIAN_POINT('',(9.87531080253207,-10.6558276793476,-3.54356506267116));
#1446=CARTESIAN_POINT('',(9.95976785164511,-11.1006311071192,-2.77314292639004));
#1447=CARTESIAN_POINT('',(10.0119836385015,-11.3227817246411,-2.38836676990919));
#1448=CARTESIAN_POINT('',(10.1344910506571,-11.7658190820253,-1.62100355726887));
#1449=CARTESIAN_POINT('',(10.2047826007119,-11.9867058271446,-1.23841649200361));
#1450=CARTESIAN_POINT('',(10.3635332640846,-12.4331933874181,-0.465077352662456));
#1451=CARTESIAN_POINT('',(10.4524447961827,-12.6587536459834,-0.0743955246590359));
#1452=CARTESIAN_POINT('',(10.6448520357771,-13.1083244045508,0.70428387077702));
#1453=CARTESIAN_POINT('',(10.7483491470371,-13.332334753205,1.09228117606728));
#1454=CARTESIAN_POINT('',(10.9672745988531,-13.7778902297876,1.86400589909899));
#1455=CARTESIAN_POINT('',(11.0826513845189,-13.9994417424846,2.24774437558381));
#1456=CARTESIAN_POINT('',(11.3237929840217,-14.4410462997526,3.01262590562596));
#1457=CARTESIAN_POINT('',(11.4495541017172,-14.6610998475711,3.39376983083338));
#1458=CARTESIAN_POINT('',(11.5796005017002,-14.8804943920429,3.77377232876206));
#1459=B_SPLINE_CURVE_WITH_KNOTS('',3,(#1425,#1426,#1427,#1428,#1429,#1430,#1431,#1432,#1433,
#1434,#1435,#1436,#1437,#1438,#1439,#1440,#1441,#1442,#1443,#1444,#1445,#1446,#1447,#1448,#1449,
#1450,#1451,#1452,#1453,#1454,#1455,#1456,#1457,#1458),.UNSPECIFIED.,.F.,.F.,(4,2,2,2,2,2,2,2,2,
2,2,2,2,2,2,2,4),(0.,1.37778937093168,2.75607536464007,4.14014697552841,5.5240827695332,
6.87032435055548,8.2165717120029,9.56006825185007,10.9035389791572,12.2424508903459,
13.5813870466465,14.9230528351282,16.2647130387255,17.6438299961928,19.0230797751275,
20.3965778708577,21.7695891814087),.UNSPECIFIED.);
#1460=CARTESIAN_POINT('',(10.4725099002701,-12.7017059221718,0.));
#1461=VERTEX_POINT('',#1460);
#1462=EDGE_CURVE('E402',#1405,#1461,#1459,.T.);
#1463=ORIENTED_EDGE('',*,*,#1462,.T.);
#1464=DIRECTION('',(-1.,0.,0.));
#1465=VECTOR('',#1464,1.);
#1466=CARTESIAN_POINT('',(15.1,-12.7017059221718,0.));
#1467=LINE('',#1466,#1465);
#1468=EDGE_CURVE('E154',#1461,#1221,#1467,.T.);
#1469=ORIENTED_EDGE('',*,*,#1468,.T.);
#1470=ORIENTED_EDGE('',*,*,#1254,.F.);
#1471=ORIENTED_EDGE('',*,*,#1348,.F.);
#1472=EDGE_LOOP('',(#1424,#1463,#1469,#1470,#1471));
#1473=FACE_BOUND('',#1472,.T.);
#1474=ADVANCED_FACE('F166',(#1473),#1423,.F.);
#1475=CARTESIAN_POINT('',(15.1,-12.7017059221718,0.));
#1476=DIRECTION('',(0.,0.866025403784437,-0.500000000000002));
#1477=DIRECTION('',(0.,0.500000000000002,0.866025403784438));
#1478=AXIS2_PLACEMENT_3D('',#1475,#1476,#1477);
#1479=PLANE('',#1478);
#1480=ORIENTED_EDGE('',*,*,#1468,.F.);
#1481=CARTESIAN_POINT('',(11.5735039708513,-14.8702068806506,-3.75595383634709));
#1482=CARTESIAN_POINT('',(11.443142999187,-14.6500285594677,-3.3745937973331));
#1483=CARTESIAN_POINT('',(11.3171084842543,-14.4291853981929,-2.99208222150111));
#1484=CARTESIAN_POINT('',(11.0755263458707,-13.9859880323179,-2.22444186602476));
#1485=CARTESIAN_POINT('',(10.9599825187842,-13.7636333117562,-1.83931219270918));
#1486=CARTESIAN_POINT('',(10.7408534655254,-13.3164534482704,-1.06477394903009));
#1487=CARTESIAN_POINT('',(10.6373204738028,-13.091621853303,-0.675354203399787));
#1488=CARTESIAN_POINT('',(10.445003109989,-12.6403980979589,0.106188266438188));
#1489=CARTESIAN_POINT('',(10.3562172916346,-12.4140060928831,0.498310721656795));
#1490=CARTESIAN_POINT('',(10.1979057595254,-11.9658880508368,1.27447393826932));
#1491=CARTESIAN_POINT('',(10.1279213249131,-11.7442028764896,1.65844392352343));
#1492=CARTESIAN_POINT('',(10.0062196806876,-11.299568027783,2.42857407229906));
#1493=CARTESIAN_POINT('',(9.95450254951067,-11.0766183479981,2.81473424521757));
#1494=CARTESIAN_POINT('',(9.87123699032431,-10.6302279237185,3.5879051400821));
#1495=CARTESIAN_POINT('',(9.83964756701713,-10.4067891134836,3.97491251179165));
#1496=CARTESIAN_POINT('',(9.79770239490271,-9.95941155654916,4.7497931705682));
#1497=CARTESIAN_POINT('',(9.78734623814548,-9.7354728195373,5.13766644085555));
#1498=CARTESIAN_POINT('',(9.78829157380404,-9.28836706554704,5.91207632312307));
#1499=CARTESIAN_POINT('',(9.79951969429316,-9.06520000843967,6.29861300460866));
#1500=CARTESIAN_POINT('',(9.84302911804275,-8.61938207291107,7.07079231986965));
#1501=CARTESIAN_POINT('',(9.87531080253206,-8.39673120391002,7.45643493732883));
#1502=CARTESIAN_POINT('',(9.9597678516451,-7.95192777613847,8.22685707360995));
#1503=CARTESIAN_POINT('',(10.0119836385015,-7.7297771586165,8.6116332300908));
#1504=CARTESIAN_POINT('',(10.1344910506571,-7.2867398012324,9.37899644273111));
#1505=CARTESIAN_POINT('',(10.2047826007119,-7.06585305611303,9.76158350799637));
#1506=CARTESIAN_POINT('',(10.3635332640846,-6.61936549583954,10.5349226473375));
#1507=CARTESIAN_POINT('',(10.4524447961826,-6.39380523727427,10.9256044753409));
#1508=CARTESIAN_POINT('',(10.6448520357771,-5.94423447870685,11.704283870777));
#1509=CARTESIAN_POINT('',(10.7483491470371,-5.72022413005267,12.0922811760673));
#1510=CARTESIAN_POINT('',(10.9672745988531,-5.27466865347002,12.864005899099));
#1511=CARTESIAN_POINT('',(11.0826513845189,-5.05311714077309,13.2477443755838));
#1512=CARTESIAN_POINT('',(11.3237929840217,-4.61151258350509,14.0126259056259));
#1513=CARTESIAN_POINT('',(11.4495541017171,-4.39145903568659,14.3937698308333));
#1514=CARTESIAN_POINT('',(11.5796005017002,-4.17206449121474,14.773772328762));
#1515=B_SPLINE_CURVE_WITH_KNOTS('',3,(#1481,#1482,#1483,#1484,#1485,#1486,#1487,#1488,#1489,
#1490,#1491,#1492,#1493,#1494,#1495,#1496,#1497,#1498,#1499,#1500,#1501,#1502,#1503,#1504,#1505,
#1506,#1507,#1508,#1509,#1510,#1511,#1512,#1513,#1514),.UNSPECIFIED.,.F.,.F.,(4,2,2,2,2,2,2,2,2,
2,2,2,2,2,2,2,4),(0.,1.37778937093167,2.75607536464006,4.1401469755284,5.52408276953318,
6.87032435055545,8.21657171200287,9.56006825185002,10.9035389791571,12.2424508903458,
13.5813870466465,14.9230528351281,16.2647130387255,17.6438299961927,19.0230797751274,
20.3965778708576,21.7695891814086),.UNSPECIFIED.);
#1516=CARTESIAN_POINT('',(10.47250990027,-6.35085296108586,11.));
#1517=VERTEX_POINT('',#1516);
#1518=EDGE_CURVE('E71',#1461,#1517,#1515,.T.);
#1519=ORIENTED_EDGE('',*,*,#1518,.T.);
#1520=DIRECTION('',(-1.,0.,0.));
#1521=VECTOR('',#1520,1.);
#1522=CARTESIAN_POINT('',(15.1,-6.35085296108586,11.));
#1523=LINE('',#1522,#1521);
#1524=EDGE_CURVE('E516',#1517,#1182,#1523,.T.);
#1525=ORIENTED_EDGE('',*,*,#1524,.T.);
#1526=ORIENTED_EDGE('',*,*,#1215,.F.);
#1527=ORIENTED_EDGE('',*,*,#1222,.F.);
#1528=EDGE_LOOP('',(#1480,#1519,#1525,#1526,#1527));
#1529=FACE_BOUND('',#1528,.T.);
#1530=ADVANCED_FACE('F385',(#1529),#1479,.F.);
#1531=CARTESIAN_POINT('',(15.1,6.35085296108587,11.));
#1532=DIRECTION('',(0.,0.,-1.));
#1533=DIRECTION('',(-1.,0.,0.));
#1534=AXIS2_PLACEMENT_3D('',#1531,#1532,#1533);
#1535=PLANE('',#1534);
#1536=ORIENTED_EDGE('',*,*,#1524,.F.);
#1537=CARTESIAN_POINT('',(11.5586752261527,-10.6377106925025,11.));
#1538=CARTESIAN_POINT('',(11.4296471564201,-10.2006329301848,11.));
#1539=CARTESIAN_POINT('',(11.3049096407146,-9.76224073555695,11.));
#1540=CARTESIAN_POINT('',(11.0658152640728,-8.88247550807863,11.));
#1541=CARTESIAN_POINT('',(10.9514620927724,-8.44110147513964,11.));
#1542=CARTESIAN_POINT('',(10.7345836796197,-7.55350352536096,11.));
#1543=CARTESIAN_POINT('',(10.6321091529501,-7.10726711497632,11.));
#1544=CARTESIAN_POINT('',(10.4417143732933,-6.21172145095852,11.));
#1545=CARTESIAN_POINT('',(10.3537927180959,-5.76241249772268,11.));
#1546=CARTESIAN_POINT('',(10.1969212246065,-4.87296269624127,11.));
#1547=CARTESIAN_POINT('',(10.1275235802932,-4.43290149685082,11.));
#1548=CARTESIAN_POINT('',(10.0067221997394,-3.55028807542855,11.));
#1549=CARTESIAN_POINT('',(9.95531854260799,-3.10773584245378,11.));
#1550=CARTESIAN_POINT('',(9.87236586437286,-2.22164860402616,11.));
#1551=CARTESIAN_POINT('',(9.84077721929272,-1.77811735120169,11.));
#1552=CARTESIAN_POINT('',(9.79850442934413,-0.890055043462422,11.));
#1553=CARTESIAN_POINT('',(9.78781991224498,-0.445524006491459,11.));
#1554=CARTESIAN_POINT('',(9.78778833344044,0.444589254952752,11.));
#1555=CARTESIAN_POINT('',(9.79849173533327,0.890171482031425,11.));
#1556=CARTESIAN_POINT('',(9.84090087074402,1.78033077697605,11.));
#1557=CARTESIAN_POINT('',(9.8726069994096,2.22490782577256,11.));
#1558=CARTESIAN_POINT('',(9.95588372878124,3.11308125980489,11.));
#1559=CARTESIAN_POINT('',(10.0074943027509,3.55667385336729,11.));
#1560=CARTESIAN_POINT('',(10.128784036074,4.44135328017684,11.));
#1561=CARTESIAN_POINT('',(10.1984631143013,4.88244012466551,11.));
#1562=CARTESIAN_POINT('',(10.3559702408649,5.77398503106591,11.));
#1563=CARTESIAN_POINT('',(10.4442489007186,6.22436280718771,11.));
#1564=CARTESIAN_POINT('',(10.6354057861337,7.12203094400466,11.));
#1565=CARTESIAN_POINT('',(10.7382854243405,7.56932100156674,11.));
#1566=CARTESIAN_POINT('',(10.9560042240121,8.45899886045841,11.));
#1567=CARTESIAN_POINT('',(11.0707922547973,8.90139927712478,11.));
#1568=CARTESIAN_POINT('',(11.3107797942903,9.78320578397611,11.));
#1569=CARTESIAN_POINT('',(11.4359755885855,10.2226128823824,11.));
#1570=CARTESIAN_POINT('',(11.5654689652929,10.6607015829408,11.));
#1571=B_SPLINE_CURVE_WITH_KNOTS('',3,(#1537,#1538,#1539,#1540,#1541,#1542,#1543,#1544,#1545,
#1546,#1547,#1548,#1549,#1550,#1551,#1552,#1553,#1554,#1555,#1556,#1557,#1558,#1559,#1560,#1561,
#1562,#1563,#1564,#1565,#1566,#1567,#1568,#1569,#1570),.UNSPECIFIED.,.F.,.F.,(4,2,2,2,2,2,2,2,2,
2,2,2,2,2,2,2,4),(0.,1.36722137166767,2.73492664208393,4.10827146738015,5.48148388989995,
6.81765221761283,8.1538264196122,9.48732009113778,10.8207900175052,12.1574099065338,
13.4940549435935,14.833398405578,16.172735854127,17.5492994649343,18.9259963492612,
20.2970092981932,21.6675350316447),.UNSPECIFIED.);
#1572=CARTESIAN_POINT('',(10.4725099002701,6.35085296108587,11.));
#1573=VERTEX_POINT('',#1572);
#1574=EDGE_CURVE('E56',#1517,#1573,#1571,.T.);
#1575=ORIENTED_EDGE('',*,*,#1574,.T.);
#1576=DIRECTION('',(-1.,0.,0.));
#1577=VECTOR('',#1576,1.);
#1578=CARTESIAN_POINT('',(15.1,6.35085296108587,11.));
#1579=LINE('',#1578,#1577);
#1580=EDGE_CURVE('E524',#1573,#1172,#1579,.T.);
#1581=ORIENTED_EDGE('',*,*,#1580,.T.);
#1582=ORIENTED_EDGE('',*,*,#1173,.F.);
#1583=ORIENTED_EDGE('',*,*,#1183,.F.);
#1584=EDGE_LOOP('',(#1536,#1575,#1581,#1582,#1583));
#1585=FACE_BOUND('',#1584,.T.);
#1586=ADVANCED_FACE('F264',(#1585),#1535,.F.);
#1587=CARTESIAN_POINT('',(15.1,12.7017059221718,0.));
#1588=DIRECTION('',(0.,-0.866025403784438,-0.500000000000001));
#1589=DIRECTION('',(0.,0.500000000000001,-0.866025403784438));
#1590=AXIS2_PLACEMENT_3D('',#1587,#1588,#1589);
#1591=PLANE('',#1590);
#1592=ORIENTED_EDGE('',*,*,#1580,.F.);
#1593=CARTESIAN_POINT('',(11.5735039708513,4.18235200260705,14.7559538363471));
#1594=CARTESIAN_POINT('',(11.443142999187,4.40253032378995,14.3745937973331));
#1595=CARTESIAN_POINT('',(11.3171084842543,4.6233734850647,13.9920822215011));
#1596=CARTESIAN_POINT('',(11.0755263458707,5.06657085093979,13.2244418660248));
#1597=CARTESIAN_POINT('',(10.9599825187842,5.28892557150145,12.8393121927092));
#1598=CARTESIAN_POINT('',(10.7408534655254,5.73610543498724,12.0647739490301));
#1599=CARTESIAN_POINT('',(10.6373204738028,5.96093702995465,11.6753542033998));
#1600=CARTESIAN_POINT('',(10.445003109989,6.41216078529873,10.8938117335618));
#1601=CARTESIAN_POINT('',(10.3562172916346,6.63855279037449,10.5016892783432));
#1602=CARTESIAN_POINT('',(10.1979057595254,7.08667083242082,9.72552606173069));
#1603=CARTESIAN_POINT('',(10.1279213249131,7.30835600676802,9.34155607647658));
#1604=CARTESIAN_POINT('',(10.0062196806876,7.75299085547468,8.57142592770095));
#1605=CARTESIAN_POINT('',(9.95450254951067,7.97594053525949,8.18526575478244));
#1606=CARTESIAN_POINT('',(9.87123699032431,8.42233095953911,7.41209485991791));
#1607=CARTESIAN_POINT('',(9.83964756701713,8.64576976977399,7.02508748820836));
#1608=CARTESIAN_POINT('',(9.79770239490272,9.09314732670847,6.2502068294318));
#1609=CARTESIAN_POINT('',(9.78734623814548,9.31708606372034,5.86233355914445));
#1610=CARTESIAN_POINT('',(9.78829157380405,9.7641918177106,5.08792367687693));
#1611=CARTESIAN_POINT('',(9.79951969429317,9.98735887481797,4.70138699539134));
#1612=CARTESIAN_POINT('',(9.84302911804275,10.4331768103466,3.92920768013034));
#1613=CARTESIAN_POINT('',(9.87531080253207,10.6558276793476,3.54356506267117));
#1614=CARTESIAN_POINT('',(9.95976785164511,11.1006311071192,2.77314292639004));
#1615=CARTESIAN_POINT('',(10.0119836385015,11.3227817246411,2.38836676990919));
#1616=CARTESIAN_POINT('',(10.1344910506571,11.7658190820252,1.62100355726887));
#1617=CARTESIAN_POINT('',(10.2047826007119,11.9867058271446,1.23841649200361));
#1618=CARTESIAN_POINT('',(10.3635332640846,12.4331933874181,0.465077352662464));
#1619=CARTESIAN_POINT('',(10.4524447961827,12.6587536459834,0.0743955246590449));
#1620=CARTESIAN_POINT('',(10.6448520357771,13.1083244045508,-0.704283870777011));
#1621=CARTESIAN_POINT('',(10.7483491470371,13.332334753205,-1.09228117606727));
#1622=CARTESIAN_POINT('',(10.9672745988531,13.7778902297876,-1.86400589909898));
#1623=CARTESIAN_POINT('',(11.0826513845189,13.9994417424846,-2.2477443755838));
#1624=CARTESIAN_POINT('',(11.3237929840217,14.4410462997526,-3.01262590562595));
#1625=CARTESIAN_POINT('',(11.4495541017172,14.6610998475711,-3.39376983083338));
#1626=CARTESIAN_POINT('',(11.5796005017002,14.8804943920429,-3.77377232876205));
#1627=B_SPLINE_CURVE_WITH_KNOTS('',3,(#1593,#1594,#1595,#1596,#1597,#1598,#1599,#1600,#1601,
#1602,#1603,#1604,#1605,#1606,#1607,#1608,#1609,#1610,#1611,#1612,#1613,#1614,#1615,#1616,#1617,
#1618,#1619,#1620,#1621,#1622,#1623,#1624,#1625,#1626),.UNSPECIFIED.,.F.,.F.,(4,2,2,2,2,2,2,2,2,
2,2,2,2,2,2,2,4),(0.,1.37778937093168,2.75607536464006,4.14014697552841,5.52408276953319,
6.87032435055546,8.21657171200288,9.56006825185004,10.9035389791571,12.2424508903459,
13.5813870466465,14.9230528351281,16.2647130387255,17.6438299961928,19.0230797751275,
20.3965778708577,21.7695891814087),.UNSPECIFIED.);
#1628=CARTESIAN_POINT('',(10.4725099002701,12.7017059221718,0.));
#1629=VERTEX_POINT('',#1628);
#1630=EDGE_CURVE('E11',#1573,#1629,#1627,.T.);
#1631=ORIENTED_EDGE('',*,*,#1630,.T.);
#1632=DIRECTION('',(-1.,0.,0.));
#1633=VECTOR('',#1632,1.);
#1634=CARTESIAN_POINT('',(15.1,12.7017059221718,0.));
#1635=LINE('',#1634,#1633);
#1636=EDGE_CURVE('E499',#1629,#1056,#1635,.T.);
#1637=ORIENTED_EDGE('',*,*,#1636,.T.);
#1638=ORIENTED_EDGE('',*,*,#1057,.F.);
#1639=ORIENTED_EDGE('',*,*,#1175,.F.);
#1640=EDGE_LOOP('',(#1592,#1631,#1637,#1638,#1639));
#1641=FACE_BOUND('',#1640,.T.);
#1642=ADVANCED_FACE('F256',(#1641),#1591,.F.);
#1643=CARTESIAN_POINT('',(15.1,6.35085296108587,-11.));
#1644=DIRECTION('',(0.,-0.866025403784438,0.500000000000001));
#1645=DIRECTION('',(0.,-0.500000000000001,-0.866025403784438));
#1646=AXIS2_PLACEMENT_3D('',#1643,#1644,#1645);
#1647=PLANE('',#1646);
#1648=ORIENTED_EDGE('',*,*,#1636,.F.);
#1649=CARTESIAN_POINT('',(11.5735039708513,14.8702068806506,3.75595383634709));
#1650=CARTESIAN_POINT('',(11.443142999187,14.6500285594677,3.3745937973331));
#1651=CARTESIAN_POINT('',(11.3171084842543,14.4291853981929,2.99208222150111));
#1652=CARTESIAN_POINT('',(11.0755263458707,13.9859880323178,2.22444186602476));
#1653=CARTESIAN_POINT('',(10.9599825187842,13.7636333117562,1.83931219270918));
#1654=CARTESIAN_POINT('',(10.7408534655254,13.3164534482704,1.06477394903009));
#1655=CARTESIAN_POINT('',(10.6373204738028,13.091621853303,0.675354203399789));
#1656=CARTESIAN_POINT('',(10.445003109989,12.6403980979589,-0.106188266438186));
#1657=CARTESIAN_POINT('',(10.3562172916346,12.4140060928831,-0.498310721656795));
#1658=CARTESIAN_POINT('',(10.1979057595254,11.9658880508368,-1.27447393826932));
#1659=CARTESIAN_POINT('',(10.1279213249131,11.7442028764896,-1.65844392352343));
#1660=CARTESIAN_POINT('',(10.0062196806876,11.299568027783,-2.42857407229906));
#1661=CARTESIAN_POINT('',(9.95450254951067,11.0766183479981,-2.81473424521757));
#1662=CARTESIAN_POINT('',(9.87123699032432,10.6302279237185,-3.58790514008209));
#1663=CARTESIAN_POINT('',(9.83964756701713,10.4067891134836,-3.97491251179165));
#1664=CARTESIAN_POINT('',(9.79770239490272,9.95941155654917,-4.7497931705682));
#1665=CARTESIAN_POINT('',(9.78734623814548,9.73547281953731,-5.13766644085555));
#1666=CARTESIAN_POINT('',(9.78829157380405,9.28836706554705,-5.91207632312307));
#1667=CARTESIAN_POINT('',(9.79951969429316,9.06520000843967,-6.29861300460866));
#1668=CARTESIAN_POINT('',(9.84302911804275,8.61938207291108,-7.07079231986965));
#1669=CARTESIAN_POINT('',(9.87531080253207,8.39673120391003,-7.45643493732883));
#1670=CARTESIAN_POINT('',(9.9597678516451,7.95192777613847,-8.22685707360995));
#1671=CARTESIAN_POINT('',(10.0119836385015,7.72977715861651,-8.6116332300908));
#1672=CARTESIAN_POINT('',(10.1344910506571,7.2867398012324,-9.37899644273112));
#1673=CARTESIAN_POINT('',(10.2047826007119,7.06585305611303,-9.76158350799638));
#1674=CARTESIAN_POINT('',(10.3635332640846,6.61936549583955,-10.5349226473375));
#1675=CARTESIAN_POINT('',(10.4524447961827,6.39380523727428,-10.9256044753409));
#1676=CARTESIAN_POINT('',(10.6448520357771,5.94423447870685,-11.704283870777));
#1677=CARTESIAN_POINT('',(10.7483491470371,5.72022413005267,-12.0922811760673));
#1678=CARTESIAN_POINT('',(10.9672745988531,5.27466865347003,-12.864005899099));
#1679=CARTESIAN_POINT('',(11.0826513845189,5.0531171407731,-13.2477443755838));
#1680=CARTESIAN_POINT('',(11.3237929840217,4.61151258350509,-14.0126259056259));
#1681=CARTESIAN_POINT('',(11.4495541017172,4.39145903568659,-14.3937698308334));
#1682=CARTESIAN_POINT('',(11.5796005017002,4.17206449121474,-14.773772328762));
#1683=B_SPLINE_CURVE_WITH_KNOTS('',3,(#1649,#1650,#1651,#1652,#1653,#1654,#1655,#1656,#1657,
#1658,#1659,#1660,#1661,#1662,#1663,#1664,#1665,#1666,#1667,#1668,#1669,#1670,#1671,#1672,#1673,
#1674,#1675,#1676,#1677,#1678,#1679,#1680,#1681,#1682),.UNSPECIFIED.,.F.,.F.,(4,2,2,2,2,2,2,2,2,
2,2,2,2,2,2,2,4),(0.,1.37778937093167,2.75607536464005,4.1401469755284,5.52408276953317,
6.87032435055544,8.21657171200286,9.56006825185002,10.9035389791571,12.2424508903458,
13.5813870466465,14.9230528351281,16.2647130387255,17.6438299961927,19.0230797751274,
20.3965778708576,21.7695891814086),.UNSPECIFIED.);
#1684=EDGE_CURVE('E580',#1629,#1366,#1683,.T.);
#1685=ORIENTED_EDGE('',*,*,#1684,.T.);
#1686=ORIENTED_EDGE('',*,*,#1367,.T.);
#1687=ORIENTED_EDGE('',*,*,#1261,.F.);
#1688=ORIENTED_EDGE('',*,*,#1088,.F.);
#1689=EDGE_LOOP('',(#1648,#1685,#1686,#1687,#1688));
#1690=FACE_BOUND('',#1689,.T.);
#1691=ADVANCED_FACE('F216',(#1690),#1647,.F.);
#1692=CARTESIAN_POINT('',(10.47250990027,-6.35085296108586,11.));
#1693=CARTESIAN_POINT('',(10.5294657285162,-6.35085115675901,10.9999968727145));
#1694=CARTESIAN_POINT('',(10.5863784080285,-6.35220170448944,11.0023360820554));
#1695=CARTESIAN_POINT('',(10.6996712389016,-6.35749510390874,11.011504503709));
#1696=CARTESIAN_POINT('',(10.7560518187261,-6.36143564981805,11.0183297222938));
#1697=CARTESIAN_POINT('',(10.9230756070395,-6.37690328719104,11.0451204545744));
#1698=CARTESIAN_POINT('',(11.0324297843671,-6.39207979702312,11.0714069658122));
#1699=CARTESIAN_POINT('',(11.2443286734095,-6.43095105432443,11.1387339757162));
#1700=CARTESIAN_POINT('',(11.3468948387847,-6.4546172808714,11.1797250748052));
#1701=CARTESIAN_POINT('',(11.5440443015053,-6.50929897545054,11.2744365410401));
#1702=CARTESIAN_POINT('',(11.6386122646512,-6.5403281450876,11.3281806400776));
#1703=CARTESIAN_POINT('',(11.8296353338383,-6.61287767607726,11.4538401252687));
#1704=CARTESIAN_POINT('',(11.9248301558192,-6.6552269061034,11.5271911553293));
#1705=CARTESIAN_POINT('',(12.1019525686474,-6.74625513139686,11.6848566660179));
#1706=CARTESIAN_POINT('',(12.1838835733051,-6.79493249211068,11.7691683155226));
#1707=CARTESIAN_POINT('',(12.3652693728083,-6.91908898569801,11.9842136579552));
#1708=CARTESIAN_POINT('',(12.4576358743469,-6.99723936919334,12.1195741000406));
#1709=CARTESIAN_POINT('',(12.5356163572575,-7.08015541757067,12.2631889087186));
#1710=CARTESIAN_POINT('',(12.5369176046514,-7.08154484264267,12.2655954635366));
#1711=CARTESIAN_POINT('',(12.5382142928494,-7.08293523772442,12.2680036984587));
#1712=B_SPLINE_CURVE_WITH_KNOTS('',3,(#1692,#1693,#1694,#1695,#1696,#1697,#1698,#1699,#1700,
#1701,#1702,#1703,#1704,#1705,#1706,#1707,#1708,#1709,#1710,#1711),.UNSPECIFIED.,.F.,.F.,(4,2,2,
2,2,2,2,2,2,4),(0.,0.170727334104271,0.34130288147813,0.680002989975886,1.01757574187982,
1.35578167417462,1.73655070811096,2.11722158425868,2.65774198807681,2.66694725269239),.UNSPECIFIED.);
#1713=EDGE_CURVE('E369',#1517,#668,#1712,.T.);
#1714=ORIENTED_EDGE('',*,*,#1713,.F.);
#1715=ORIENTED_EDGE('',*,*,#1518,.F.);
#1716=CARTESIAN_POINT('',(10.4725099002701,-12.7017059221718,0.));
#1717=CARTESIAN_POINT('',(10.5294657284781,-12.7017023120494,-5.73317267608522E-10));
#1718=CARTESIAN_POINT('',(10.5863784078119,-12.7044034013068,-3.24471651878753E-09));
#1719=CARTESIAN_POINT('',(10.6996712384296,-12.7149901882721,-8.37887355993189E-09));
#1720=CARTESIAN_POINT('',(10.7560518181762,-12.7228712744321,-1.08418147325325E-08));
#1721=CARTESIAN_POINT('',(10.9230756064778,-12.7538065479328,-1.13331013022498E-08));
#1722=CARTESIAN_POINT('',(11.0324297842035,-12.7841595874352,-2.59790121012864E-09));
#1723=CARTESIAN_POINT('',(11.2443286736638,-12.8619021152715,2.58925852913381E-09));
#1724=CARTESIAN_POINT('',(11.3468948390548,-12.9092345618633,-9.17994087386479E-10));
#1725=CARTESIAN_POINT('',(11.5440443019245,-13.0185979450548,-5.3543347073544E-09));
#1726=CARTESIAN_POINT('',(11.6386122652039,-13.0806562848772,-6.27857454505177E-09));
#1727=CARTESIAN_POINT('',(11.8296353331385,-13.2257553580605,7.06873690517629E-09));
#1728=CARTESIAN_POINT('',(11.9248301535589,-13.310453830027,2.32673115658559E-08));
#1729=CARTESIAN_POINT('',(12.1019525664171,-13.4925102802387,2.31341755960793E-08));
#1730=CARTESIAN_POINT('',(12.183883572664,-13.5898649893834,6.81084981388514E-09));
#1731=CARTESIAN_POINT('',(12.3652693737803,-13.8381779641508,-9.6708312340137E-09));
#1732=CARTESIAN_POINT('',(12.4576358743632,-13.9944787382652,-1.62994421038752E-10));
#1733=CARTESIAN_POINT('',(12.5356163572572,-14.1603108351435,2.72312534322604E-12));
#1734=CARTESIAN_POINT('',(12.5369176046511,-14.1630896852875,2.78776463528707E-12));
#1735=CARTESIAN_POINT('',(12.5382142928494,-14.1658704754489,0.));
#1736=B_SPLINE_CURVE_WITH_KNOTS('',3,(#1716,#1717,#1718,#1719,#1720,#1721,#1722,#1723,#1724,
#1725,#1726,#1727,#1728,#1729,#1730,#1731,#1732,#1733,#1734,#1735),.UNSPECIFIED.,.F.,.F.,(4,2,2,
2,2,2,2,2,2,4),(0.,0.170727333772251,0.341302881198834,0.680002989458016,1.0175757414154,
1.35578167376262,1.73655070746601,2.11722158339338,2.65774198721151,2.66694725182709),.UNSPECIFIED.);
#1737=EDGE_CURVE('E50',#810,#1461,#1736,.F.);
#1738=ORIENTED_EDGE('',*,*,#1737,.F.);
#1739=ORIENTED_EDGE('',*,*,#811,.F.);
#1740=EDGE_LOOP('',(#1714,#1715,#1738,#1739));
#1741=FACE_BOUND('',#1740,.T.);
#1742=ADVANCED_FACE('F357',(#1741),#773,.F.);
#1743=ORIENTED_EDGE('',*,*,#1737,.T.);
#1744=ORIENTED_EDGE('',*,*,#1462,.F.);
#1745=CARTESIAN_POINT('',(10.4725099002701,-6.3508529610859,-11.));
#1746=CARTESIAN_POINT('',(10.5294657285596,-6.35085115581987,-10.9999968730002));
#1747=CARTESIAN_POINT('',(10.5863784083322,-6.35220169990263,-11.0023360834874));
#1748=CARTESIAN_POINT('',(10.6996712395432,-6.35749509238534,-11.0115045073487));
#1749=CARTESIAN_POINT('',(10.7560518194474,-6.36143563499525,-11.0183297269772));
#1750=CARTESIAN_POINT('',(10.923075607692,-6.37690327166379,-11.0451204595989));
#1751=CARTESIAN_POINT('',(11.0324297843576,-6.39207979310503,-11.0714069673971));
#1752=CARTESIAN_POINT('',(11.2443286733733,-6.43095105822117,-11.1387339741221));
#1753=CARTESIAN_POINT('',(11.3468948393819,-6.45461728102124,-11.1797250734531));
#1754=CARTESIAN_POINT('',(11.5440443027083,-6.50929897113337,-11.2744365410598));
#1755=CARTESIAN_POINT('',(11.6386122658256,-6.54032814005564,-11.328180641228));
#1756=CARTESIAN_POINT('',(11.829635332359,-6.61287768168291,-11.4538401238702));
#1757=CARTESIAN_POINT('',(11.9248301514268,-6.65522692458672,-11.5271911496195));
#1758=CARTESIAN_POINT('',(12.101952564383,-6.74625514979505,-11.6848566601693));
#1759=CARTESIAN_POINT('',(12.1838835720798,-6.794932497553,-11.7691683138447));
#1760=CARTESIAN_POINT('',(12.365269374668,-6.91908897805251,-11.9842136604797));
#1761=CARTESIAN_POINT('',(12.4576358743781,-6.99723936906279,-12.1195741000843));
#1762=CARTESIAN_POINT('',(12.5356163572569,-7.0801554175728,-12.2631889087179));
#1763=CARTESIAN_POINT('',(12.5369176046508,-7.08154484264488,-12.2655954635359));
#1764=CARTESIAN_POINT('',(12.5382142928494,-7.08293523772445,-12.2680036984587));
#1765=B_SPLINE_CURVE_WITH_KNOTS('',3,(#1745,#1746,#1747,#1748,#1749,#1750,#1751,#1752,#1753,
#1754,#1755,#1756,#1757,#1758,#1759,#1760,#1761,#1762,#1763,#1764),.UNSPECIFIED.,.F.,.F.,(4,2,2,
2,2,2,2,2,2,4),(0.,0.170727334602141,0.34130288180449,0.680002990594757,1.01757574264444,
1.35578167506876,1.7365507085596,2.11722158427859,2.65774198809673,2.6669472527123),.UNSPECIFIED.);
#1766=EDGE_CURVE('E349',#240,#1405,#1765,.F.);
#1767=ORIENTED_EDGE('',*,*,#1766,.F.);
#1768=ORIENTED_EDGE('',*,*,#951,.F.);
#1769=EDGE_LOOP('',(#1743,#1744,#1767,#1768));
#1770=FACE_BOUND('',#1769,.T.);
#1771=ADVANCED_FACE('F333',(#1770),#915,.F.);
#1772=ORIENTED_EDGE('',*,*,#1713,.T.);
#1773=ORIENTED_EDGE('',*,*,#669,.F.);
#1774=CARTESIAN_POINT('',(10.4725099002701,6.35085296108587,11.));
#1775=CARTESIAN_POINT('',(10.5294657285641,6.35085115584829,10.9999968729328));
#1776=CARTESIAN_POINT('',(10.5863784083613,6.3522017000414,11.0023360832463));
#1777=CARTESIAN_POINT('',(10.6996712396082,6.35749509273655,11.0115045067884));
#1778=CARTESIAN_POINT('',(10.7560518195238,6.36143563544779,11.01832972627));
#1779=CARTESIAN_POINT('',(10.9230756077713,6.37690327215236,11.0451204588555));
#1780=CARTESIAN_POINT('',(11.0324297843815,6.39207979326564,11.0714069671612));
#1781=CARTESIAN_POINT('',(11.2443286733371,6.43095105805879,11.1387339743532));
#1782=CARTESIAN_POINT('',(11.3468948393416,6.45461728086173,11.1797250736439));
#1783=CARTESIAN_POINT('',(11.544044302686,6.50929897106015,11.274436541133));
#1784=CARTESIAN_POINT('',(11.6386122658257,6.540328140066,11.328180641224));
#1785=CARTESIAN_POINT('',(11.8296353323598,6.6128776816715,11.4538401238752));
#1786=CARTESIAN_POINT('',(11.9248301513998,6.65522692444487,11.5271911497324));
#1787=CARTESIAN_POINT('',(12.1019525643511,6.74625514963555,11.6848566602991));
#1788=CARTESIAN_POINT('',(12.1838835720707,6.79493249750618,11.7691683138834));
#1789=CARTESIAN_POINT('',(12.3652693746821,6.91908897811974,11.9842136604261));
#1790=CARTESIAN_POINT('',(12.4576358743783,6.9972393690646,12.119574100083));
#1791=CARTESIAN_POINT('',(12.5356163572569,7.08015541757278,12.2631889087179));
#1792=CARTESIAN_POINT('',(12.5369176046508,7.08154484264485,12.2655954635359));
#1793=CARTESIAN_POINT('',(12.5382142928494,7.08293523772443,12.2680036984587));
#1794=B_SPLINE_CURVE_WITH_KNOTS('',3,(#1774,#1775,#1776,#1777,#1778,#1779,#1780,#1781,#1782,
#1783,#1784,#1785,#1786,#1787,#1788,#1789,#1790,#1791,#1792,#1793),.UNSPECIFIED.,.F.,.F.,(4,2,2,
2,2,2,2,2,2,4),(0.,0.170727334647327,0.341302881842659,0.68000299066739,1.01757574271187,
1.35578167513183,1.73655070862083,2.11722158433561,2.65774198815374,2.66694725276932),.UNSPECIFIED.);
#1795=EDGE_CURVE('E321',#1573,#526,#1794,.T.);
#1796=ORIENTED_EDGE('',*,*,#1795,.F.);
#1797=ORIENTED_EDGE('',*,*,#1574,.F.);
#1798=EDGE_LOOP('',(#1772,#1773,#1796,#1797));
#1799=FACE_BOUND('',#1798,.T.);
#1800=ADVANCED_FACE('F309',(#1799),#631,.F.);
#1801=ORIENTED_EDGE('',*,*,#1766,.T.);
#1802=ORIENTED_EDGE('',*,*,#1406,.F.);
#1803=CARTESIAN_POINT('',(10.4725099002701,6.35085296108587,-11.));
#1804=CARTESIAN_POINT('',(10.5294657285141,6.35085115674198,-10.9999968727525));
#1805=CARTESIAN_POINT('',(10.5863784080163,6.35220170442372,-11.0023360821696));
#1806=CARTESIAN_POINT('',(10.6996712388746,6.35749510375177,-11.0115045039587));
#1807=CARTESIAN_POINT('',(10.7560518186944,6.36143564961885,-11.0183297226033));
#1808=CARTESIAN_POINT('',(10.9230756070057,6.37690328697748,-11.0451204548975));
#1809=CARTESIAN_POINT('',(11.0324297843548,6.39207979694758,-11.0714069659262));
#1810=CARTESIAN_POINT('',(11.2443286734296,6.43095105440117,-11.1387339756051));
#1811=CARTESIAN_POINT('',(11.3468948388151,6.45461728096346,-11.1797250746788));
#1812=CARTESIAN_POINT('',(11.5440443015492,6.50929897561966,-11.2744365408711));
#1813=CARTESIAN_POINT('',(11.6386122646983,6.5403281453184,-11.3281806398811));
#1814=CARTESIAN_POINT('',(11.82963533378,6.61287767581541,-11.4538401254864));
#1815=CARTESIAN_POINT('',(11.9248301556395,6.65522690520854,-11.5271911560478));
#1816=CARTESIAN_POINT('',(12.1019525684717,6.74625513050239,-11.6848566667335));
#1817=CARTESIAN_POINT('',(12.1838835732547,6.79493249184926,-11.7691683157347));
#1818=CARTESIAN_POINT('',(12.365269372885,6.91908898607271,-11.9842136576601));
#1819=CARTESIAN_POINT('',(12.4576358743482,6.99723936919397,-12.1195741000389));
#1820=CARTESIAN_POINT('',(12.5356163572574,7.08015541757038,-12.2631889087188));
#1821=CARTESIAN_POINT('',(12.5369176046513,7.08154484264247,-12.2655954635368));
#1822=CARTESIAN_POINT('',(12.5382142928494,7.08293523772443,-12.2680036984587));
#1823=B_SPLINE_CURVE_WITH_KNOTS('',3,(#1803,#1804,#1805,#1806,#1807,#1808,#1809,#1810,#1811,
#1812,#1813,#1814,#1815,#1816,#1817,#1818,#1819,#1820,#1821,#1822),.UNSPECIFIED.,.F.,.F.,(4,2,2,
2,2,2,2,2,2,4),(0.,0.17072733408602,0.341302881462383,0.680002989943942,1.01757574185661,
1.3557816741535,1.73655070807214,2.11722158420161,2.65774198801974,2.66694725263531),.UNSPECIFIED.);
#1824=EDGE_CURVE('E296',#242,#1366,#1823,.F.);
#1825=ORIENTED_EDGE('',*,*,#1824,.F.);
#1826=ORIENTED_EDGE('',*,*,#243,.F.);
#1827=EDGE_LOOP('',(#1801,#1802,#1825,#1826));
#1828=FACE_BOUND('',#1827,.T.);
#1829=ADVANCED_FACE('F273',(#1828),#203,.F.);
#1830=ORIENTED_EDGE('',*,*,#1795,.T.);
#1831=ORIENTED_EDGE('',*,*,#527,.F.);
#1832=CARTESIAN_POINT('',(10.4725099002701,12.7017059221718,0.));
#1833=CARTESIAN_POINT('',(10.529465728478,12.7017023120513,5.6991735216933E-10));
#1834=CARTESIAN_POINT('',(10.5863784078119,12.7044034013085,3.24177615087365E-09));
#1835=CARTESIAN_POINT('',(10.6996712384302,12.7149901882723,8.37907327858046E-09));
#1836=CARTESIAN_POINT('',(10.7560518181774,12.7228712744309,1.08446930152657E-08));
#1837=CARTESIAN_POINT('',(10.9230756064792,12.7538065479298,1.13391045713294E-08));
#1838=CARTESIAN_POINT('',(11.0324297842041,12.7841595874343,2.59954869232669E-09));
#1839=CARTESIAN_POINT('',(11.2443286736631,12.8619021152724,-2.59089888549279E-09));
#1840=CARTESIAN_POINT('',(11.3468948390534,12.9092345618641,9.1740367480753E-10));
#1841=CARTESIAN_POINT('',(11.5440443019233,13.0185979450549,5.35457675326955E-09));
#1842=CARTESIAN_POINT('',(11.6386122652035,13.0806562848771,6.27859672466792E-09));
#1843=CARTESIAN_POINT('',(11.8296353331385,13.2257553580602,-7.06876377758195E-09));
#1844=CARTESIAN_POINT('',(11.9248301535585,13.3104538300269,-2.32671149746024E-08));
#1845=CARTESIAN_POINT('',(12.1019525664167,13.4925102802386,-2.31336885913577E-08));
#1846=CARTESIAN_POINT('',(12.1838835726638,13.5898649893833,-6.81029581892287E-09));
#1847=CARTESIAN_POINT('',(12.3652693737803,13.8381779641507,9.67004450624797E-09));
#1848=CARTESIAN_POINT('',(12.4576358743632,13.9944787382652,1.60168917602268E-10));
#1849=CARTESIAN_POINT('',(12.5356163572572,14.1603108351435,-2.82114350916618E-12));
#1850=CARTESIAN_POINT('',(12.5369176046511,14.1630896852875,-2.83874139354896E-12));
#1851=CARTESIAN_POINT('',(12.5382142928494,14.1658704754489,0.));
#1852=B_SPLINE_CURVE_WITH_KNOTS('',3,(#1832,#1833,#1834,#1835,#1836,#1837,#1838,#1839,#1840,
#1841,#1842,#1843,#1844,#1845,#1846,#1847,#1848,#1849,#1850,#1851),.UNSPECIFIED.,.F.,.F.,(4,2,2,
2,2,2,2,2,2,4),(0.,0.170727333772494,0.341302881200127,0.680002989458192,1.01757574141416,
1.35578167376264,1.73655070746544,2.11722158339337,2.65774198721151,2.66694725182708),.UNSPECIFIED.);
#1853=EDGE_CURVE('E425',#1629,#384,#1852,.T.);
#1854=ORIENTED_EDGE('',*,*,#1853,.F.);
#1855=ORIENTED_EDGE('',*,*,#1630,.F.);
#1856=EDGE_LOOP('',(#1830,#1831,#1854,#1855));
#1857=FACE_BOUND('',#1856,.T.);
#1858=ADVANCED_FACE('F269',(#1857),#489,.F.);
#1859=ORIENTED_EDGE('',*,*,#1824,.T.);
#1860=ORIENTED_EDGE('',*,*,#1684,.F.);
#1861=ORIENTED_EDGE('',*,*,#1853,.T.);
#1862=ORIENTED_EDGE('',*,*,#385,.F.);
#1863=EDGE_LOOP('',(#1859,#1860,#1861,#1862));
#1864=FACE_BOUND('',#1863,.T.);
#1865=ADVANCED_FACE('F274',(#1864),#347,.F.);
#1866=CLOSED_SHELL('',(#46,#66,#86,#95,#966,#978,#1020,#1093,#1180,#1219,#1258,#1345,#1355,
#1418,#1474,#1530,#1586,#1642,#1691,#1742,#1771,#1800,#1829,#1858,#1865));
#1867=MANIFOLD_SOLID_BREP('B2',#1866);
#1868=ADVANCED_BREP_SHAPE_REPRESENTATION('',(#18,#1867),#14);
#1869=SHAPE_DEFINITION_REPRESENTATION(#9,#1868);
ENDSEC;
END-ISO-10303-21;
